// Mitsubishi GX Works2 project: L06-PLC   PLC: L06

// task 1# (event TRUE, interval 0, priority 31): 
// task 10# (event TRUE, interval 0, priority 31): 
// task 工位6（点胶A面） (event TRUE, interval 0, priority 31): 
// task 工位7（点胶B面） (event TRUE, interval 0, priority 31): 
// task 工位8 (event TRUE, interval 0, priority 31): 
// task 工位9（出料及载座升降） (event TRUE, interval 0, priority 31): 
// task 工站5（排不良） (event TRUE, interval 0, priority 31): 
// task 手动 (event TRUE, interval 0, priority 31): 手动
// task 报警 (event TRUE, interval 0, priority 31): 报警
// task 输出1 (event TRUE, interval 0, priority 31): 输出
// task 降载座工位 (event TRUE, interval 0, priority 31): 
// task 马达初始化 (event TRUE, interval 0, priority 31): 
// task 5# (event TRUE, interval 0, priority 31): 
// task 工站2（AOI测试） (event TRUE, interval 0, priority 31): 
// task 工站3（开短路测试） (event TRUE, interval 0, priority 31): 
// task 工站4（开短路测试） (event TRUE, interval 0, priority 31): 
// task 测试程序 (event TRUE, interval 0, priority 31): 
// task 4# (event TRUE, interval 0, priority 31): 
// task 1#1 (event TRUE, interval 0, priority 31): 1#主轴1
// task 2# (event TRUE, interval 0, priority 31): 2#主轴2
// task 3# (event TRUE, interval 0, priority 31): 3#模块轴3
// task 4#1 (event TRUE, interval 0, priority 31): 4#模块轴4
// task 5#1 (event TRUE, interval 0, priority 31): 5#模块轴5
// task 6# (event TRUE, interval 0, priority 31): 
// task 6#1 (event TRUE, interval 0, priority 31): 6#模块轴6
// task 7#1 (event TRUE, interval 0, priority 31): 7#模块轴7
// task 8#1 (event TRUE, interval 0, priority 31): 8#模块轴8
// task 9#1 (event TRUE, interval 0, priority 31): 9#模块轴9
// task 10#1 (event TRUE, interval 0, priority 31): 10#模块轴10
// task 11# (event TRUE, interval 0, priority 31): 
// task 12# (event TRUE, interval 0, priority 31): 
// task 马达初始化1 (event TRUE, interval 0, priority 31): 马达初始化
// task 工位10 (event TRUE, interval 0, priority 31): 
// task 7# (event TRUE, interval 0, priority 31): 
// task 8# (event TRUE, interval 0, priority 31): 
// task 9# (event TRUE, interval 0, priority 31): 
// task 初始化及工位控制 (event TRUE, interval 0, priority 31): 初始化
// task 升载座 (event TRUE, interval 0, priority 31): 
// task 工位1 (event TRUE, interval 0, priority 31): 
// task 放料马达 (event TRUE, interval 0, priority 31): 放料马达
// task 效率统计 (event TRUE, interval 0, priority 31): 效率统计
// task 易损件 (event TRUE, interval 0, priority 31): 易损件
// task 短路预警 (event TRUE, interval 0, priority 31): 
// task 短路预警1 (event TRUE, interval 0, priority 31): 
// task 短路管制 (event TRUE, interval 0, priority 31): 短路管制
// task 试机品点检 (event TRUE, interval 0, priority 31): 试机品点检
// task 11#模块轴11 (event TRUE, interval 0, priority 31): 11#模块轴11
// task 12#模块轴12 (event TRUE, interval 0, priority 31): 12#模块轴12

PROGRAM 1#主轴1
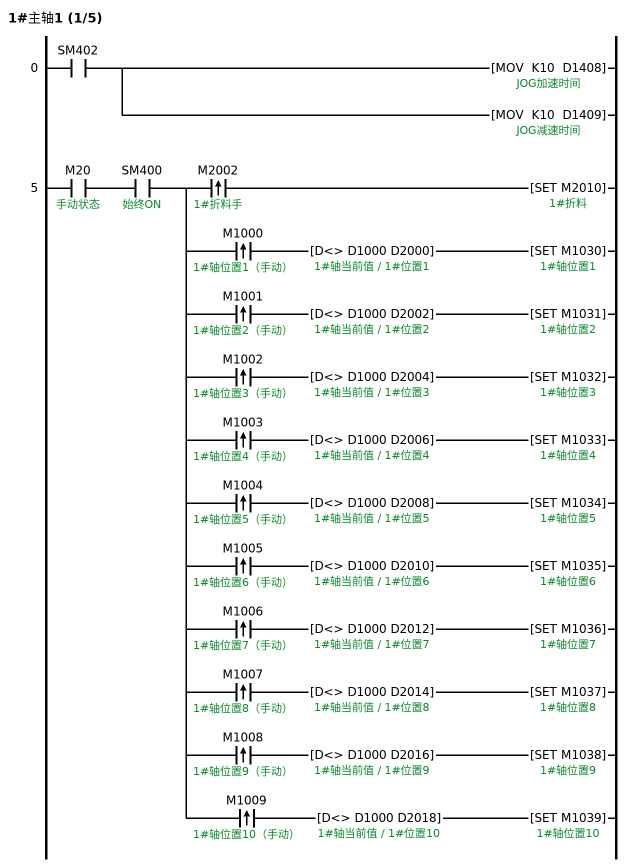
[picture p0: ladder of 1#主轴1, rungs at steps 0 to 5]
0     LD      SM402
      MOV     K10 D1408  ; JOG加速时间
      MOV     K10 D1409  ; JOG减速时间
5     LD      M20  ; 手动状态
      AND     SM400  ; 始终ON
      MPS
      ANDP    M2002  ; 1#折料手
      SET     M2010  ; 1#折料
      MRD
      ANDP    M1000  ; 1#轴位置1（手动）
      ANDD<>  D1000 D2000  ; 1#轴当前值 / 1#位置1
      SET     M1030  ; 1#轴位置1
      MRD
      ANDP    M1001  ; 1#轴位置2（手动）
      ANDD<>  D1000 D2002  ; 1#轴当前值 / 1#位置2
      SET     M1031  ; 1#轴位置2
      MRD
      ANDP    M1002  ; 1#轴位置3（手动）
      ANDD<>  D1000 D2004  ; 1#轴当前值 / 1#位置3
      SET     M1032  ; 1#轴位置3
      MRD
      ANDP    M1003  ; 1#轴位置4（手动）
      ANDD<>  D1000 D2006  ; 1#轴当前值 / 1#位置4
      SET     M1033  ; 1#轴位置4
      MRD
      ANDP    M1004  ; 1#轴位置5（手动）
      ANDD<>  D1000 D2008  ; 1#轴当前值 / 1#位置5
      SET     M1034  ; 1#轴位置5
      MRD
      ANDP    M1005  ; 1#轴位置6（手动）
      ANDD<>  D1000 D2010  ; 1#轴当前值 / 1#位置6
      SET     M1035  ; 1#轴位置6
      MRD
      ANDP    M1006  ; 1#轴位置7（手动）
      ANDD<>  D1000 D2012  ; 1#轴当前值 / 1#位置7
      SET     M1036  ; 1#轴位置7
      MRD
      ANDP    M1007  ; 1#轴位置8（手动）
      ANDD<>  D1000 D2014  ; 1#轴当前值 / 1#位置8
      SET     M1037  ; 1#轴位置8
      MRD
      ANDP    M1008  ; 1#轴位置9（手动）
      ANDD<>  D1000 D2016  ; 1#轴当前值 / 1#位置9
      SET     M1038  ; 1#轴位置9
      MPP
      ANDP    M1009  ; 1#轴位置10（手动）
      ANDD<>  D1000 D2018  ; 1#轴当前值 / 1#位置10
      SET     M1039  ; 1#轴位置10
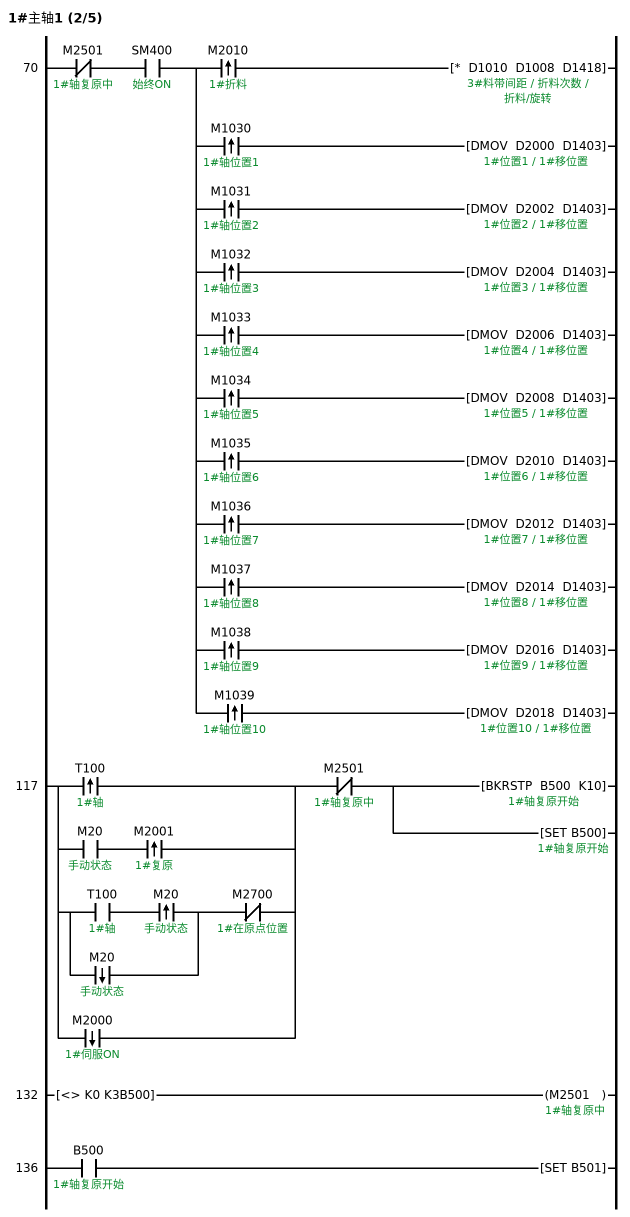
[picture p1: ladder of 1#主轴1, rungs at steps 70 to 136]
70    LDI     M2501  ; 1#轴复原中
      AND     SM400  ; 始终ON
      MPS
      ANDP    M2010  ; 1#折料
      *       D1010 D1008 D1418  ; 3#料带间距 / 折料次数 / 折料/旋转
      MRD
      ANDP    M1030  ; 1#轴位置1
      DMOV    D2000 D1403  ; 1#移位置
      MRD
      ANDP    M1031  ; 1#轴位置2
      DMOV    D2002 D1403
      MRD
      ANDP    M1032  ; 1#轴位置3
      DMOV    D2004 D1403
      MRD
      ANDP    M1033  ; 1#轴位置4
      DMOV    D2006 D1403
      MRD
      ANDP    M1034  ; 1#轴位置5
      DMOV    D2008 D1403
      MRD
      ANDP    M1035  ; 1#轴位置6
      DMOV    D2010 D1403
      MRD
      ANDP    M1036  ; 1#轴位置7
      DMOV    D2012 D1403
      MRD
      ANDP    M1037  ; 1#轴位置8
      DMOV    D2014 D1403
      MRD
      ANDP    M1038  ; 1#轴位置9
      DMOV    D2016 D1403
      MPP
      ANDP    M1039  ; 1#轴位置10
      DMOV    D2018 D1403
117   LDP     T100  ; 1#轴
      LD      M20  ; 手动状态
      ANDP    M2001  ; 1#复原
      ORB
      LD      T100  ; 1#轴
      ANDP    M20  ; 手动状态
      ORF     M20  ; 手动状态
      ANI     M2700  ; 1#在原点位置
      ORB
      ORF     M2000  ; 1#伺服ON
      ANI     M2501  ; 1#轴复原中
      BKRSTP  B500 K10  ; 1#轴复原开始
      SET     B500  ; 1#轴复原开始
132   LD<>    K0 K3B500  ; 1#轴复原开始
      OUT     M2501  ; 1#轴复原中
136   LD      B500  ; 1#轴复原开始
      SET     B501
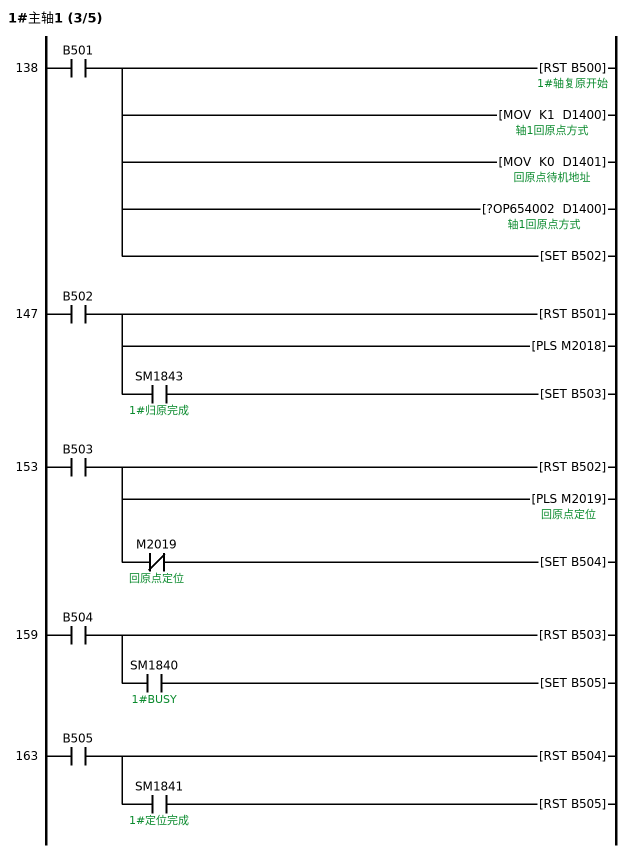
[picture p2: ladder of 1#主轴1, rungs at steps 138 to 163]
138   LD      B501
      RST     B500  ; 1#轴复原开始
      MOV     K1 D1400  ; 轴1回原点方式
      MOV     K0 D1401  ; 回原点待机地址
      ?OP654002 D1400
      SET     B502
147   LD      B502
      RST     B501
      PLS     M2018
      AND     SM1843  ; 1#归原完成
      SET     B503
153   LD      B503
      RST     B502
      PLS     M2019  ; 回原点定位
      ANI     M2019  ; 回原点定位
      SET     B504
159   LD      B504
      RST     B503
      AND     SM1840  ; 1#BUSY
      SET     B505
163   LD      B505
      RST     B504
      AND     SM1841  ; 1#定位完成
      RST     B505
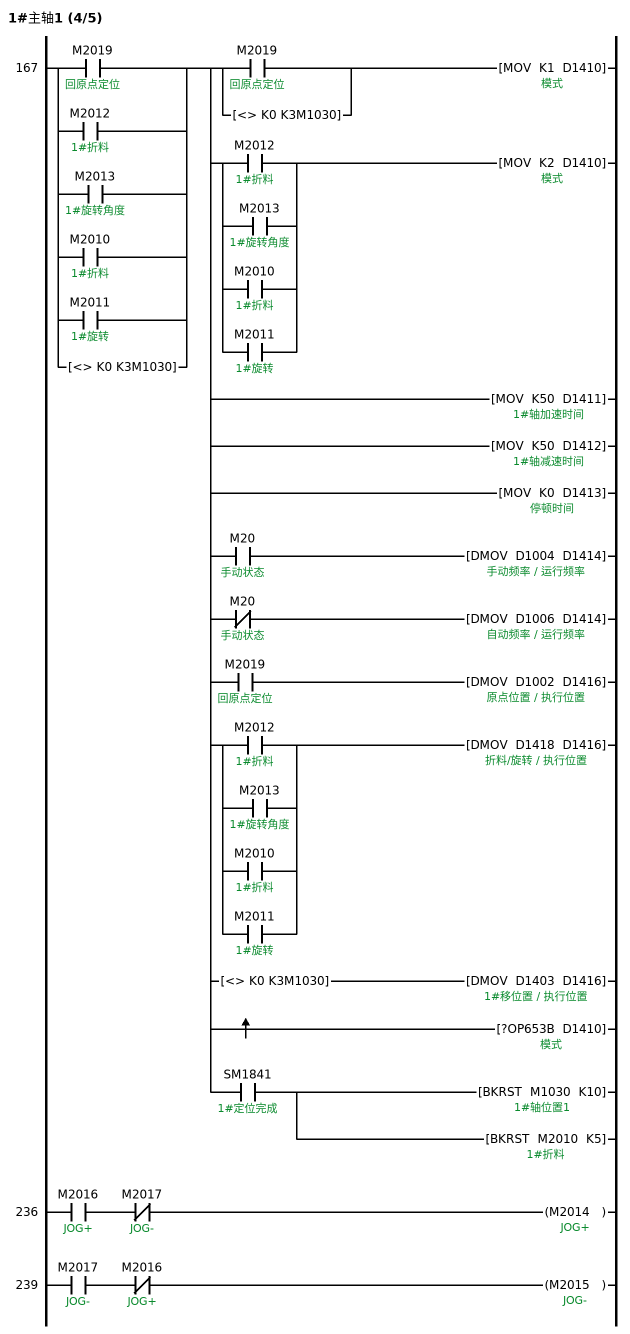
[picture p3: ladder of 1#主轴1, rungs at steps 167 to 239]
167   LD      M2019  ; 回原点定位
      OR      M2012  ; 1#折料
      OR      M2013  ; 1#旋转角度
      OR      M2010  ; 1#折料
      OR      M2011  ; 1#旋转
      OR<>    K0 K3M1030  ; 1#轴位置1
      MPS
      LD      M2019  ; 回原点定位
      OR<>    K0 K3M1030  ; 1#轴位置1
      ANB
      MOV     K1 D1410  ; 模式
      MRD
      LD      M2012  ; 1#折料
      OR      M2013  ; 1#旋转角度
      OR      M2010  ; 1#折料
      OR      M2011  ; 1#旋转
      ANB
      MOV     K2 D1410
      MPP
      MOV     K50 D1411  ; 1#轴加速时间
      MOV     K50 D1412  ; 1#轴减速时间
      MOV     K0 D1413  ; 停顿时间
      MPS
      AND     M20  ; 手动状态
      DMOV    D1004 D1414  ; 手动频率 / 运行频率
      MRD
      ANI     M20  ; 手动状态
      DMOV    D1006 D1414  ; 自动频率
      MRD
      AND     M2019  ; 回原点定位
      DMOV    D1002 D1416  ; 原点位置 / 执行位置
      MRD
      LD      M2012  ; 1#折料
      OR      M2013  ; 1#旋转角度
      OR      M2010  ; 1#折料
      OR      M2011  ; 1#旋转
      ANB
      DMOV    D1418 D1416
      MRD
      AND<>   K0 K3M1030  ; 1#轴位置1
      DMOV    D1403 D1416
      MRD
      MEP
      ?OP653B D1410
      MPP
      AND     SM1841  ; 1#定位完成
      BKRST   M1030 K10
      BKRST   M2010 K5
236   LD      M2016  ; JOG+
      ANI     M2017  ; JOG-
      OUT     M2014  ; JOG+
239   LD      M2017  ; JOG-
      ANI     M2016  ; JOG+
      OUT     M2015  ; JOG-
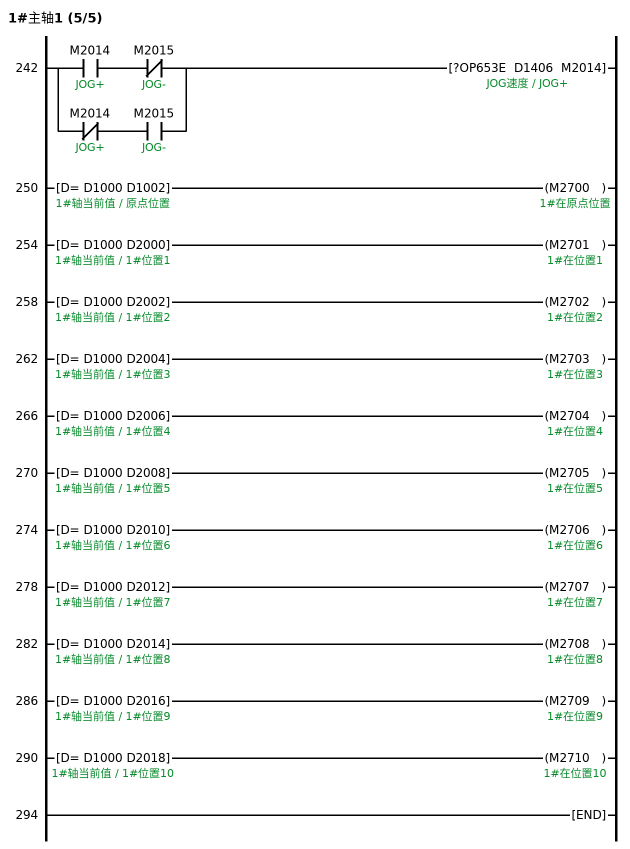
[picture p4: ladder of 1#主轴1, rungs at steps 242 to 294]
242   LD      M2014  ; JOG+
      ANI     M2015  ; JOG-
      LDI     M2014  ; JOG+
      AND     M2015  ; JOG-
      ORB
      ?OP653E D1406 M2014  ; JOG速度
250   LDD=    D1000 D1002  ; 1#轴当前值 / 原点位置
      OUT     M2700  ; 1#在原点位置
254   LDD=    D1000 D2000  ; 1#轴当前值 / 1#位置1
      OUT     M2701  ; 1#在位置1
258   LDD=    D1000 D2002  ; 1#轴当前值 / 1#位置2
      OUT     M2702  ; 1#在位置2
262   LDD=    D1000 D2004  ; 1#轴当前值 / 1#位置3
      OUT     M2703  ; 1#在位置3
266   LDD=    D1000 D2006  ; 1#轴当前值 / 1#位置4
      OUT     M2704  ; 1#在位置4
270   LDD=    D1000 D2008  ; 1#轴当前值 / 1#位置5
      OUT     M2705  ; 1#在位置5
274   LDD=    D1000 D2010  ; 1#轴当前值 / 1#位置6
      OUT     M2706  ; 1#在位置6
278   LDD=    D1000 D2012  ; 1#轴当前值 / 1#位置7
      OUT     M2707  ; 1#在位置7
282   LDD=    D1000 D2014  ; 1#轴当前值 / 1#位置8
      OUT     M2708  ; 1#在位置8
286   LDD=    D1000 D2016  ; 1#轴当前值 / 1#位置9
      OUT     M2709  ; 1#在位置9
290   LDD=    D1000 D2018  ; 1#轴当前值 / 1#位置10
      OUT     M2710  ; 1#在位置10
294   END
END_PROGRAM

PROGRAM 10#模块轴10
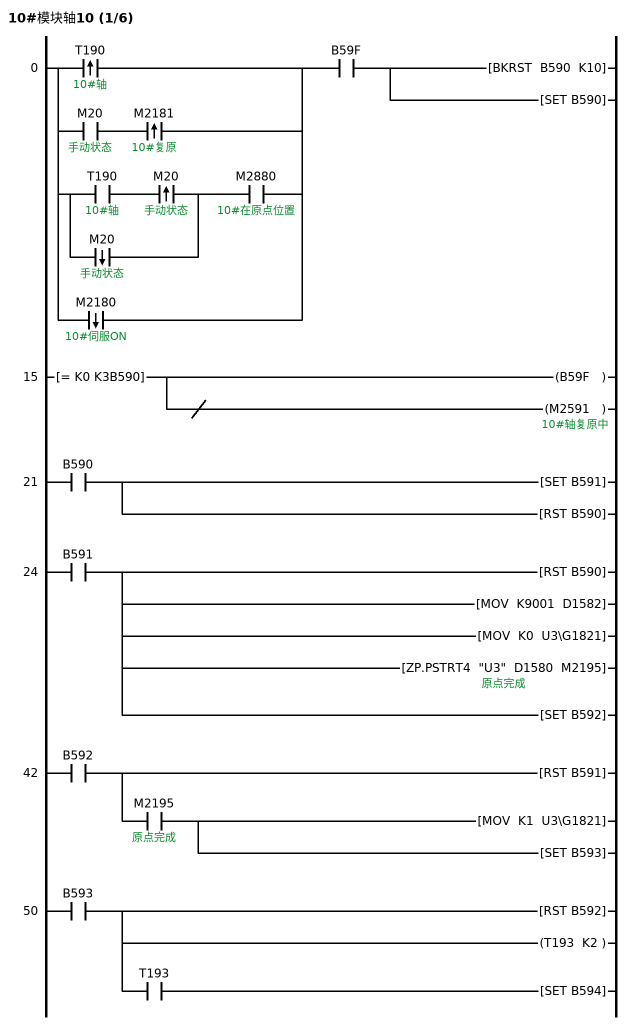
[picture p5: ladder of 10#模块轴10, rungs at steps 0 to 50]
0     LDP     T190  ; 10#轴
      LD      M20  ; 手动状态
      ANDP    M2181  ; 10#复原
      ORB
      LD      T190  ; 10#轴
      ANDP    M20  ; 手动状态
      ORF     M20  ; 手动状态
      AND     M2880  ; 10#在原点位置
      ORB
      ORF     M2180  ; 10#伺服ON
      AND     B59F
      BKRST   B590 K10
      SET     B590
15    LD=     K0 K3B590
      OUT     B59F
      INV
      OUT     M2591  ; 10#轴复原中
21    LD      B590
      SET     B591
      RST     B590
24    LD      B591
      RST     B590
      MOV     K9001 D1582
      MOV     K0 U3\G1821
      ZP.PSTRT4 "U3" D1580 M2195  ; 原点完成
      SET     B592
42    LD      B592
      RST     B591
      AND     M2195  ; 原点完成
      MOV     K1 U3\G1821
      SET     B593
50    LD      B593
      RST     B592
      OUT     T193 K2
      AND     T193
      SET     B594
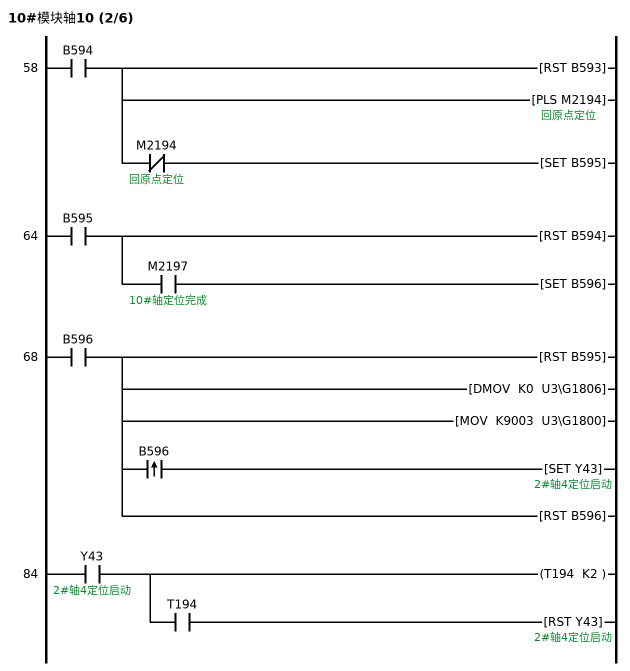
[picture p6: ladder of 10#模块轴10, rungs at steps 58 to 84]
58    LD      B594
      RST     B593
      PLS     M2194  ; 回原点定位
      ANI     M2194  ; 回原点定位
      SET     B595
64    LD      B595
      RST     B594
      AND     M2197  ; 10#轴定位完成
      SET     B596
68    LD      B596
      RST     B595
      DMOV    K0 U3\G1806
      MOV     K9003 U3\G1800
      MPS
      ANDP    B596
      SET     Y43  ; 2#轴4定位启动
      MPP
      RST     B596
84    LD      Y43  ; 2#轴4定位启动
      OUT     T194 K2
      AND     T194
      RST     Y43  ; 2#轴4定位启动
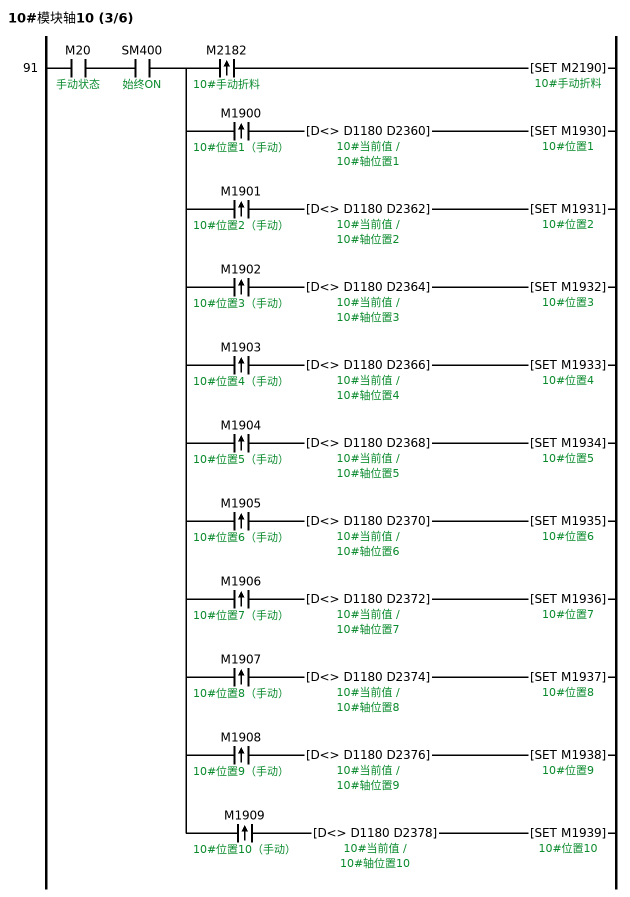
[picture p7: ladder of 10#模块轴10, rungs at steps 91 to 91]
91    LD      M20  ; 手动状态
      AND     SM400  ; 始终ON
      MPS
      ANDP    M2182  ; 10#手动折料
      SET     M2190  ; 10#手动折料
      MRD
      ANDP    M1900  ; 10#位置1（手动）
      ANDD<>  D1180 D2360  ; 10#当前值 / 10#轴位置1
      SET     M1930  ; 10#位置1
      MRD
      ANDP    M1901  ; 10#位置2（手动）
      ANDD<>  D1180 D2362  ; 10#当前值 / 10#轴位置2
      SET     M1931  ; 10#位置2
      MRD
      ANDP    M1902  ; 10#位置3（手动）
      ANDD<>  D1180 D2364  ; 10#当前值 / 10#轴位置3
      SET     M1932  ; 10#位置3
      MRD
      ANDP    M1903  ; 10#位置4（手动）
      ANDD<>  D1180 D2366  ; 10#当前值 / 10#轴位置4
      SET     M1933  ; 10#位置4
      MRD
      ANDP    M1904  ; 10#位置5（手动）
      ANDD<>  D1180 D2368  ; 10#当前值 / 10#轴位置5
      SET     M1934  ; 10#位置5
      MRD
      ANDP    M1905  ; 10#位置6（手动）
      ANDD<>  D1180 D2370  ; 10#当前值 / 10#轴位置6
      SET     M1935  ; 10#位置6
      MRD
      ANDP    M1906  ; 10#位置7（手动）
      ANDD<>  D1180 D2372  ; 10#当前值 / 10#轴位置7
      SET     M1936  ; 10#位置7
      MRD
      ANDP    M1907  ; 10#位置8（手动）
      ANDD<>  D1180 D2374  ; 10#当前值 / 10#轴位置8
      SET     M1937  ; 10#位置8
      MRD
      ANDP    M1908  ; 10#位置9（手动）
      ANDD<>  D1180 D2376  ; 10#当前值 / 10#轴位置9
      SET     M1938  ; 10#位置9
      MPP
      ANDP    M1909  ; 10#位置10（手动）
      ANDD<>  D1180 D2378  ; 10#当前值 / 10#轴位置10
      SET     M1939  ; 10#位置10
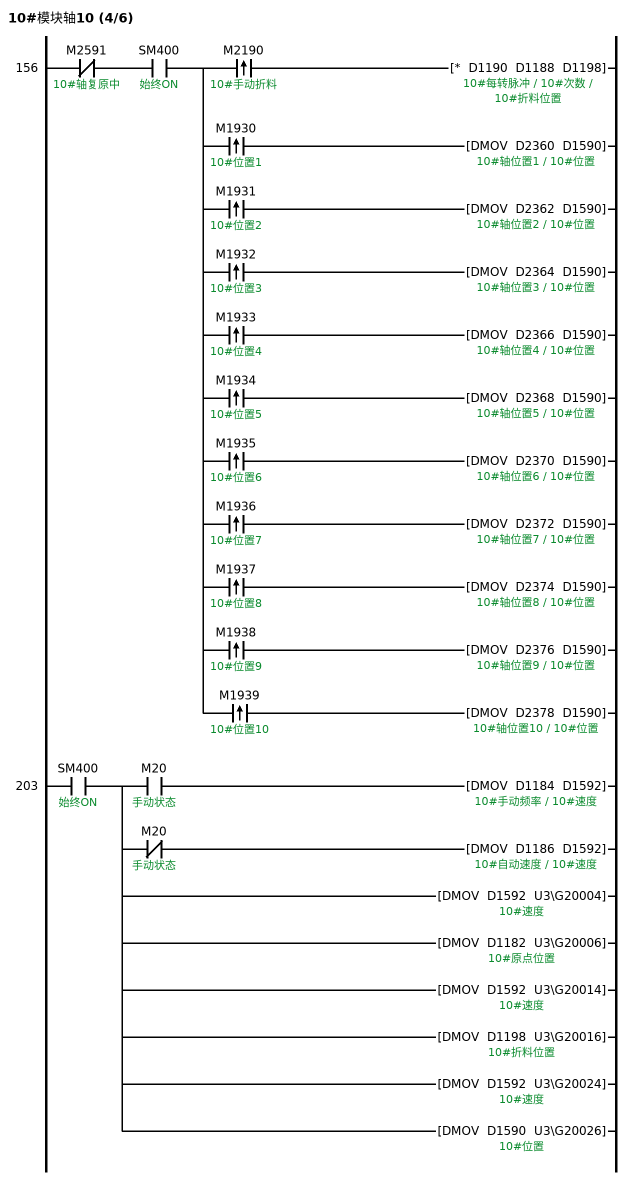
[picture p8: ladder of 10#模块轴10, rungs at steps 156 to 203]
156   LDI     M2591  ; 10#轴复原中
      AND     SM400  ; 始终ON
      MPS
      ANDP    M2190  ; 10#手动折料
      *       D1190 D1188 D1198  ; 10#每转脉冲 / 10#次数 / 10#折料位置
      MRD
      ANDP    M1930  ; 10#位置1
      DMOV    D2360 D1590  ; 10#位置
      MRD
      ANDP    M1931  ; 10#位置2
      DMOV    D2362 D1590
      MRD
      ANDP    M1932  ; 10#位置3
      DMOV    D2364 D1590
      MRD
      ANDP    M1933  ; 10#位置4
      DMOV    D2366 D1590
      MRD
      ANDP    M1934  ; 10#位置5
      DMOV    D2368 D1590
      MRD
      ANDP    M1935  ; 10#位置6
      DMOV    D2370 D1590
      MRD
      ANDP    M1936  ; 10#位置7
      DMOV    D2372 D1590
      MRD
      ANDP    M1937  ; 10#位置8
      DMOV    D2374 D1590
      MRD
      ANDP    M1938  ; 10#位置9
      DMOV    D2376 D1590
      MPP
      ANDP    M1939  ; 10#位置10
      DMOV    D2378 D1590
203   LD      SM400  ; 始终ON
      MPS
      AND     M20  ; 手动状态
      DMOV    D1184 D1592  ; 10#手动频率 / 10#速度
      MRD
      ANI     M20  ; 手动状态
      DMOV    D1186 D1592  ; 10#自动速度
      MPP
      DMOV    D1592 U3\G20004
      DMOV    D1182 U3\G20006  ; 10#原点位置
      DMOV    D1592 U3\G20014
      DMOV    D1198 U3\G20016
      DMOV    D1592 U3\G20024
      DMOV    D1590 U3\G20026
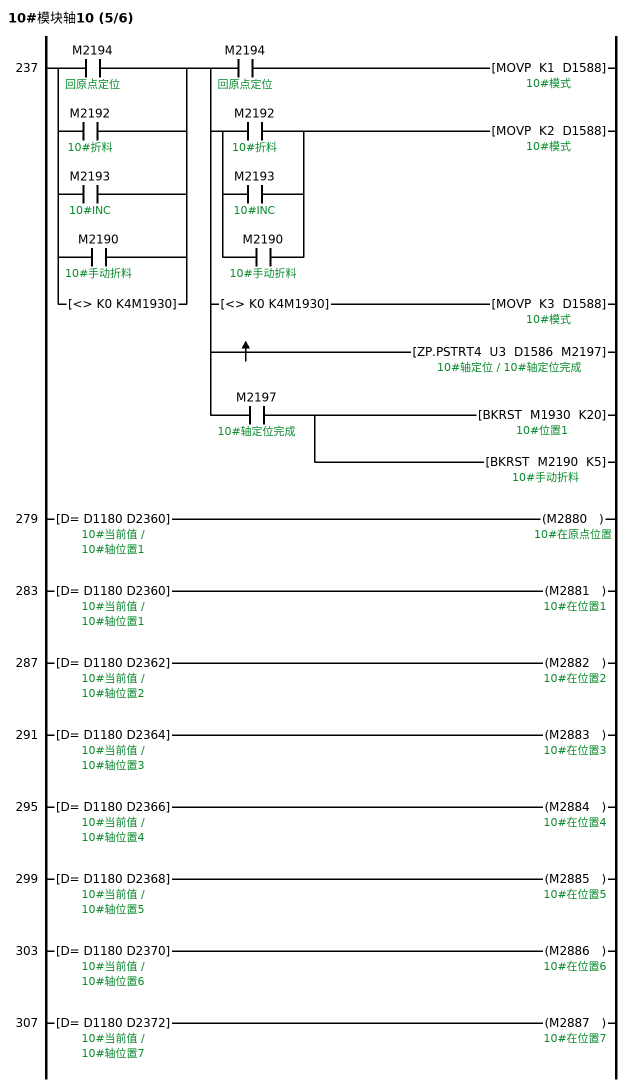
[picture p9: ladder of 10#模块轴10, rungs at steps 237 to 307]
237   LD      M2194  ; 回原点定位
      OR      M2192  ; 10#折料
      OR      M2193  ; 10#INC
      OR      M2190  ; 10#手动折料
      OR<>    K0 K4M1930  ; 10#位置1
      MPS
      AND     M2194  ; 回原点定位
      MOVP    K1 D1588  ; 10#模式
      MRD
      LD      M2192  ; 10#折料
      OR      M2193  ; 10#INC
      OR      M2190  ; 10#手动折料
      ANB
      MOVP    K2 D1588
      MRD
      AND<>   K0 K4M1930  ; 10#位置1
      MOVP    K3 D1588
      MRD
      MEP
      ZP.PSTRT4 U3 D1586 M2197  ; 10#轴定位
      MPP
      AND     M2197  ; 10#轴定位完成
      BKRST   M1930 K20
      BKRST   M2190 K5
279   LDD=    D1180 D2360  ; 10#当前值 / 10#轴位置1
      OUT     M2880  ; 10#在原点位置
283   LDD=    D1180 D2360  ; 10#当前值 / 10#轴位置1
      OUT     M2881  ; 10#在位置1
287   LDD=    D1180 D2362  ; 10#当前值 / 10#轴位置2
      OUT     M2882  ; 10#在位置2
291   LDD=    D1180 D2364  ; 10#当前值 / 10#轴位置3
      OUT     M2883  ; 10#在位置3
295   LDD=    D1180 D2366  ; 10#当前值 / 10#轴位置4
      OUT     M2884  ; 10#在位置4
299   LDD=    D1180 D2368  ; 10#当前值 / 10#轴位置5
      OUT     M2885  ; 10#在位置5
303   LDD=    D1180 D2370  ; 10#当前值 / 10#轴位置6
      OUT     M2886  ; 10#在位置6
307   LDD=    D1180 D2372  ; 10#当前值 / 10#轴位置7
      OUT     M2887  ; 10#在位置7
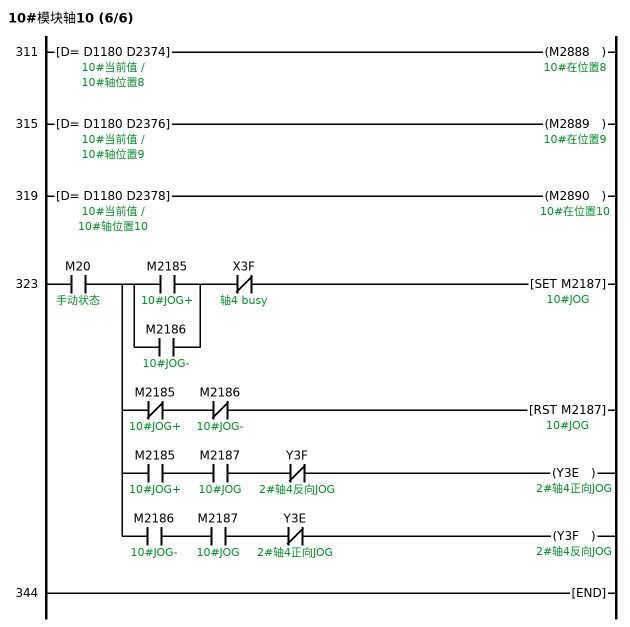
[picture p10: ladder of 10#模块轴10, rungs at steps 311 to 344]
311   LDD=    D1180 D2374  ; 10#当前值 / 10#轴位置8
      OUT     M2888  ; 10#在位置8
315   LDD=    D1180 D2376  ; 10#当前值 / 10#轴位置9
      OUT     M2889  ; 10#在位置9
319   LDD=    D1180 D2378  ; 10#当前值 / 10#轴位置10
      OUT     M2890  ; 10#在位置10
323   LD      M20  ; 手动状态
      MPS
      LD      M2185  ; 10#JOG+
      OR      M2186  ; 10#JOG-
      ANB
      ANI     X3F  ; 轴4 busy
      SET     M2187  ; 10#JOG
      MRD
      ANI     M2185  ; 10#JOG+
      ANI     M2186  ; 10#JOG-
      RST     M2187  ; 10#JOG
      MRD
      AND     M2185  ; 10#JOG+
      AND     M2187  ; 10#JOG
      ANI     Y3F  ; 2#轴4反向JOG
      OUT     Y3E  ; 2#轴4正向JOG
      MPP
      AND     M2186  ; 10#JOG-
      AND     M2187  ; 10#JOG
      ANI     Y3E  ; 2#轴4正向JOG
      OUT     Y3F  ; 2#轴4反向JOG
344   END
END_PROGRAM

PROGRAM 2#主轴2
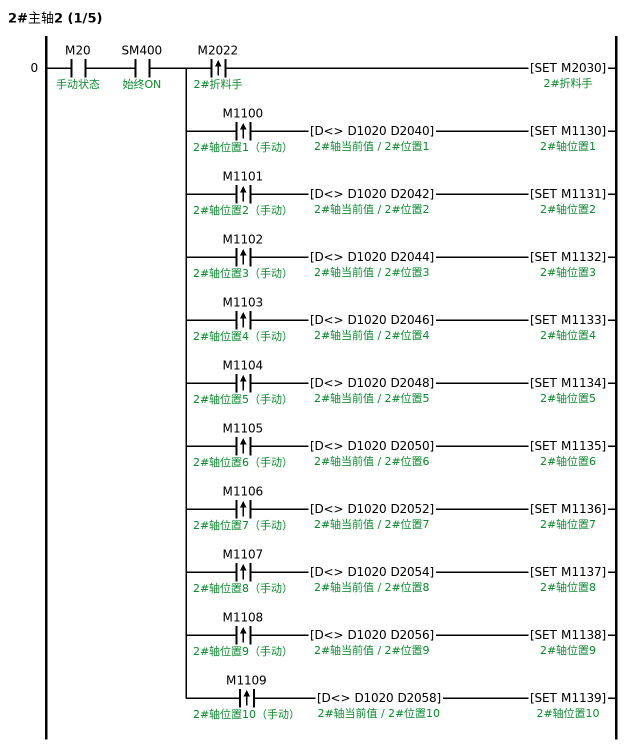
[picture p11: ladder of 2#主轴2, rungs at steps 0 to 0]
0     LD      M20  ; 手动状态
      AND     SM400  ; 始终ON
      MPS
      ANDP    M2022  ; 2#折料手
      SET     M2030  ; 2#折料手
      MRD
      ANDP    M1100  ; 2#轴位置1（手动）
      ANDD<>  D1020 D2040  ; 2#轴当前值 / 2#位置1
      SET     M1130  ; 2#轴位置1
      MRD
      ANDP    M1101  ; 2#轴位置2（手动）
      ANDD<>  D1020 D2042  ; 2#轴当前值 / 2#位置2
      SET     M1131  ; 2#轴位置2
      MRD
      ANDP    M1102  ; 2#轴位置3（手动）
      ANDD<>  D1020 D2044  ; 2#轴当前值 / 2#位置3
      SET     M1132  ; 2#轴位置3
      MRD
      ANDP    M1103  ; 2#轴位置4（手动）
      ANDD<>  D1020 D2046  ; 2#轴当前值 / 2#位置4
      SET     M1133  ; 2#轴位置4
      MRD
      ANDP    M1104  ; 2#轴位置5（手动）
      ANDD<>  D1020 D2048  ; 2#轴当前值 / 2#位置5
      SET     M1134  ; 2#轴位置5
      MRD
      ANDP    M1105  ; 2#轴位置6（手动）
      ANDD<>  D1020 D2050  ; 2#轴当前值 / 2#位置6
      SET     M1135  ; 2#轴位置6
      MRD
      ANDP    M1106  ; 2#轴位置7（手动）
      ANDD<>  D1020 D2052  ; 2#轴当前值 / 2#位置7
      SET     M1136  ; 2#轴位置7
      MRD
      ANDP    M1107  ; 2#轴位置8（手动）
      ANDD<>  D1020 D2054  ; 2#轴当前值 / 2#位置8
      SET     M1137  ; 2#轴位置8
      MRD
      ANDP    M1108  ; 2#轴位置9（手动）
      ANDD<>  D1020 D2056  ; 2#轴当前值 / 2#位置9
      SET     M1138  ; 2#轴位置9
      MPP
      ANDP    M1109  ; 2#轴位置10（手动）
      ANDD<>  D1020 D2058  ; 2#轴当前值 / 2#位置10
      SET     M1139  ; 2#轴位置10
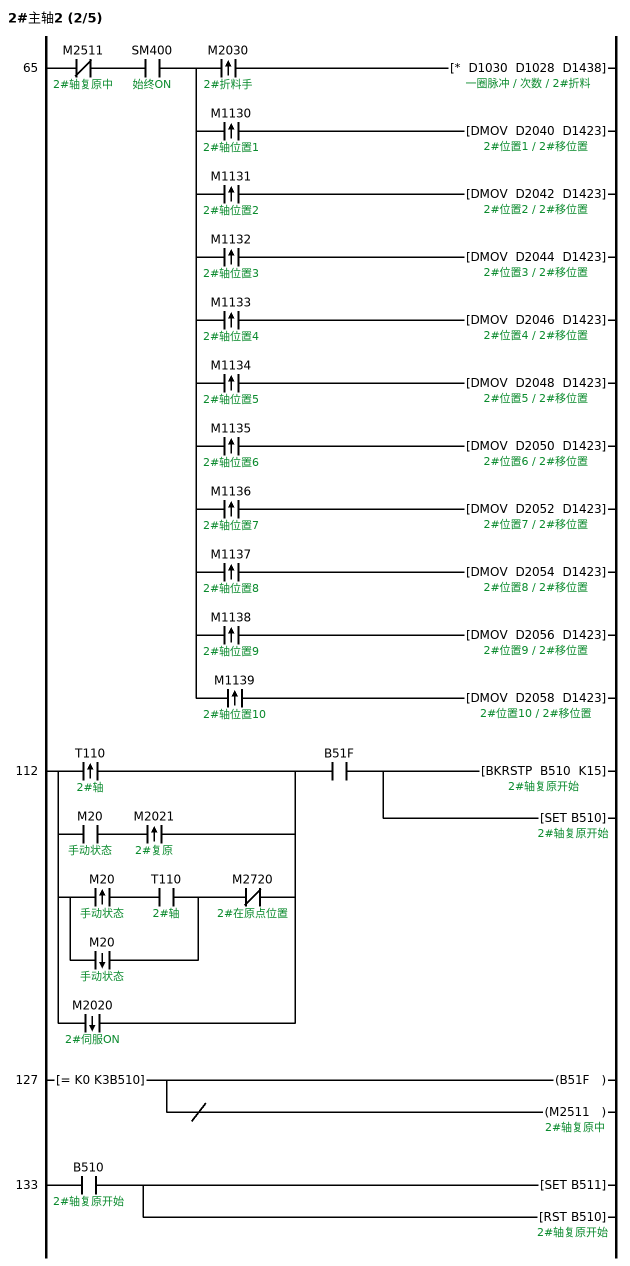
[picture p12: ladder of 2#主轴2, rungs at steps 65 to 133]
65    LDI     M2511  ; 2#轴复原中
      AND     SM400  ; 始终ON
      MPS
      ANDP    M2030  ; 2#折料手
      *       D1030 D1028 D1438  ; 一圈脉冲 / 次数 / 2#折料
      MRD
      ANDP    M1130  ; 2#轴位置1
      DMOV    D2040 D1423  ; 2#移位置
      MRD
      ANDP    M1131  ; 2#轴位置2
      DMOV    D2042 D1423
      MRD
      ANDP    M1132  ; 2#轴位置3
      DMOV    D2044 D1423
      MRD
      ANDP    M1133  ; 2#轴位置4
      DMOV    D2046 D1423
      MRD
      ANDP    M1134  ; 2#轴位置5
      DMOV    D2048 D1423
      MRD
      ANDP    M1135  ; 2#轴位置6
      DMOV    D2050 D1423
      MRD
      ANDP    M1136  ; 2#轴位置7
      DMOV    D2052 D1423
      MRD
      ANDP    M1137  ; 2#轴位置8
      DMOV    D2054 D1423
      MRD
      ANDP    M1138  ; 2#轴位置9
      DMOV    D2056 D1423
      MPP
      ANDP    M1139  ; 2#轴位置10
      DMOV    D2058 D1423
112   LDP     T110  ; 2#轴
      LD      M20  ; 手动状态
      ANDP    M2021  ; 2#复原
      ORB
      LDP     M20  ; 手动状态
      AND     T110  ; 2#轴
      ORF     M20  ; 手动状态
      ANI     M2720  ; 2#在原点位置
      ORB
      ORF     M2020  ; 2#伺服ON
      AND     B51F
      BKRSTP  B510 K15  ; 2#轴复原开始
      SET     B510  ; 2#轴复原开始
127   LD=     K0 K3B510  ; 2#轴复原开始
      OUT     B51F
      INV
      OUT     M2511  ; 2#轴复原中
133   LD      B510  ; 2#轴复原开始
      SET     B511
      RST     B510  ; 2#轴复原开始
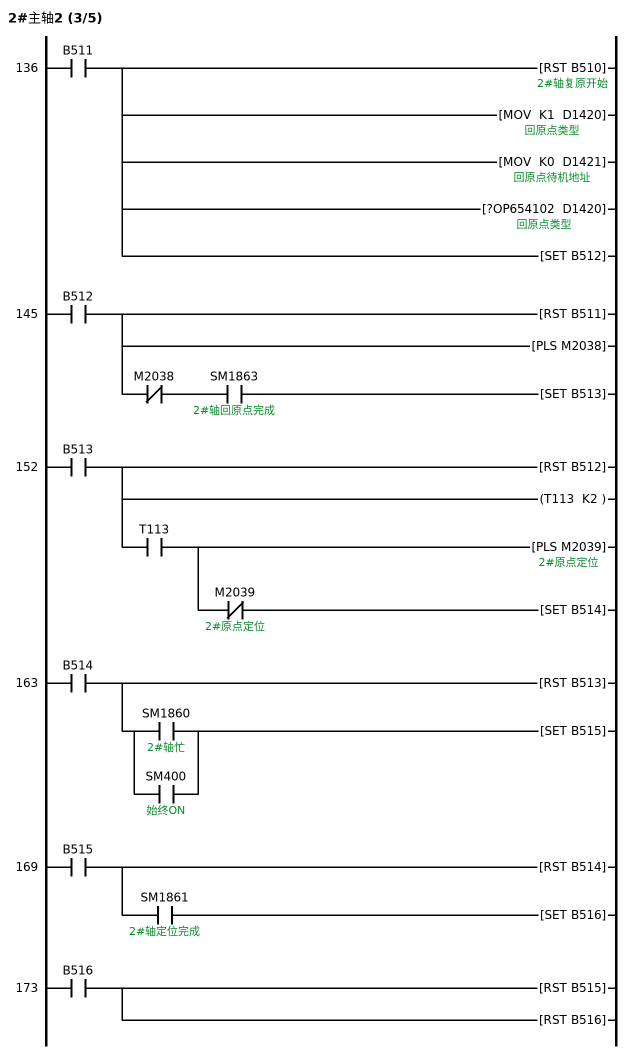
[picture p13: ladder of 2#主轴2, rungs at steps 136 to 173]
136   LD      B511
      RST     B510  ; 2#轴复原开始
      MOV     K1 D1420  ; 回原点类型
      MOV     K0 D1421  ; 回原点待机地址
      ?OP654102 D1420
      SET     B512
145   LD      B512
      RST     B511
      PLS     M2038
      ANI     M2038
      AND     SM1863  ; 2#轴回原点完成
      SET     B513
152   LD      B513
      RST     B512
      OUT     T113 K2
      AND     T113
      PLS     M2039  ; 2#原点定位
      ANI     M2039  ; 2#原点定位
      SET     B514
163   LD      B514
      RST     B513
      LD      SM1860  ; 2#轴忙
      OR      SM400  ; 始终ON
      ANB
      SET     B515
169   LD      B515
      RST     B514
      AND     SM1861  ; 2#轴定位完成
      SET     B516
173   LD      B516
      RST     B515
      RST     B516
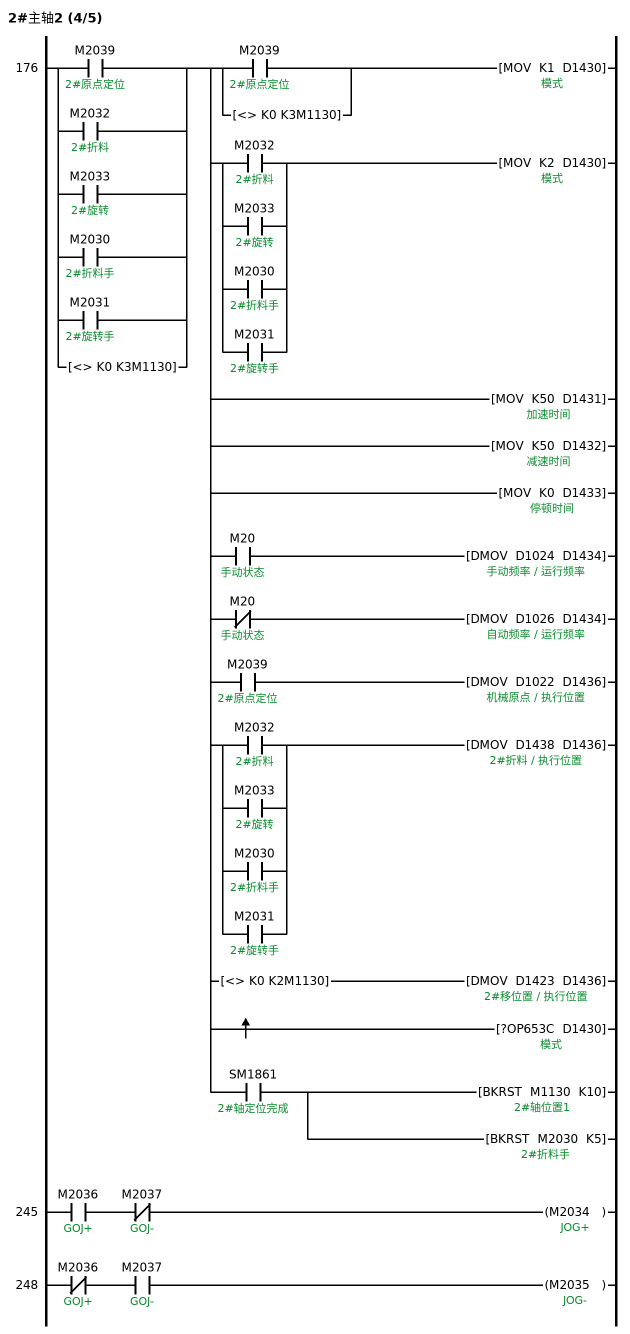
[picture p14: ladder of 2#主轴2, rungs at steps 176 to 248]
176   LD      M2039  ; 2#原点定位
      OR      M2032  ; 2#折料
      OR      M2033  ; 2#旋转
      OR      M2030  ; 2#折料手
      OR      M2031  ; 2#旋转手
      OR<>    K0 K3M1130  ; 2#轴位置1
      MPS
      LD      M2039  ; 2#原点定位
      OR<>    K0 K3M1130  ; 2#轴位置1
      ANB
      MOV     K1 D1430  ; 模式
      MRD
      LD      M2032  ; 2#折料
      OR      M2033  ; 2#旋转
      OR      M2030  ; 2#折料手
      OR      M2031  ; 2#旋转手
      ANB
      MOV     K2 D1430
      MPP
      MOV     K50 D1431  ; 加速时间
      MOV     K50 D1432  ; 减速时间
      MOV     K0 D1433  ; 停顿时间
      MPS
      AND     M20  ; 手动状态
      DMOV    D1024 D1434  ; 手动频率 / 运行频率
      MRD
      ANI     M20  ; 手动状态
      DMOV    D1026 D1434  ; 自动频率
      MRD
      AND     M2039  ; 2#原点定位
      DMOV    D1022 D1436  ; 机械原点 / 执行位置
      MRD
      LD      M2032  ; 2#折料
      OR      M2033  ; 2#旋转
      OR      M2030  ; 2#折料手
      OR      M2031  ; 2#旋转手
      ANB
      DMOV    D1438 D1436
      MRD
      AND<>   K0 K2M1130  ; 2#轴位置1
      DMOV    D1423 D1436
      MRD
      MEP
      ?OP653C D1430
      MPP
      AND     SM1861  ; 2#轴定位完成
      BKRST   M1130 K10
      BKRST   M2030 K5
245   LD      M2036  ; GOJ+
      ANI     M2037  ; GOJ-
      OUT     M2034  ; JOG+
248   LDI     M2036  ; GOJ+
      AND     M2037  ; GOJ-
      OUT     M2035  ; JOG-
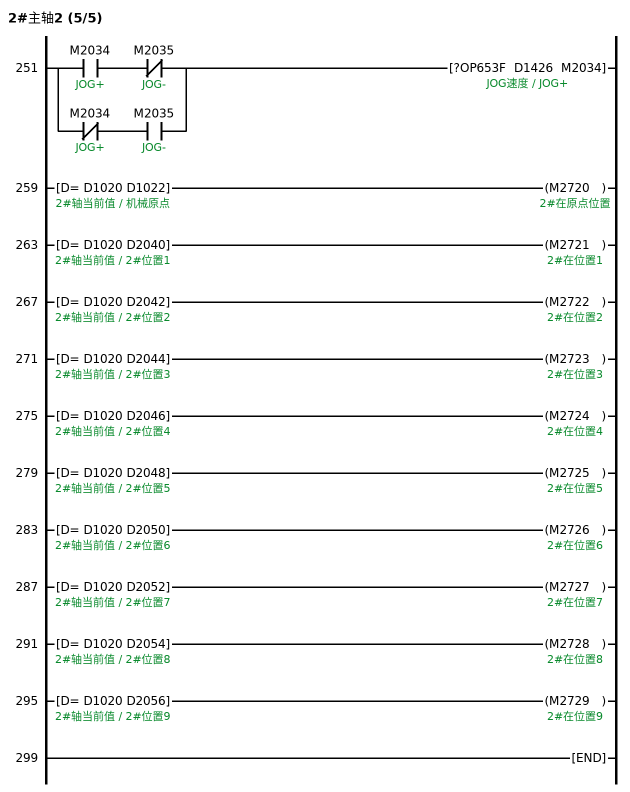
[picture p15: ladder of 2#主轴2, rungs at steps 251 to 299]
251   LD      M2034  ; JOG+
      ANI     M2035  ; JOG-
      LDI     M2034  ; JOG+
      AND     M2035  ; JOG-
      ORB
      ?OP653F D1426 M2034  ; JOG速度
259   LDD=    D1020 D1022  ; 2#轴当前值 / 机械原点
      OUT     M2720  ; 2#在原点位置
263   LDD=    D1020 D2040  ; 2#轴当前值 / 2#位置1
      OUT     M2721  ; 2#在位置1
267   LDD=    D1020 D2042  ; 2#轴当前值 / 2#位置2
      OUT     M2722  ; 2#在位置2
271   LDD=    D1020 D2044  ; 2#轴当前值 / 2#位置3
      OUT     M2723  ; 2#在位置3
275   LDD=    D1020 D2046  ; 2#轴当前值 / 2#位置4
      OUT     M2724  ; 2#在位置4
279   LDD=    D1020 D2048  ; 2#轴当前值 / 2#位置5
      OUT     M2725  ; 2#在位置5
283   LDD=    D1020 D2050  ; 2#轴当前值 / 2#位置6
      OUT     M2726  ; 2#在位置6
287   LDD=    D1020 D2052  ; 2#轴当前值 / 2#位置7
      OUT     M2727  ; 2#在位置7
291   LDD=    D1020 D2054  ; 2#轴当前值 / 2#位置8
      OUT     M2728  ; 2#在位置8
295   LDD=    D1020 D2056  ; 2#轴当前值 / 2#位置9
      OUT     M2729  ; 2#在位置9
299   END
END_PROGRAM

PROGRAM 3#模块轴3
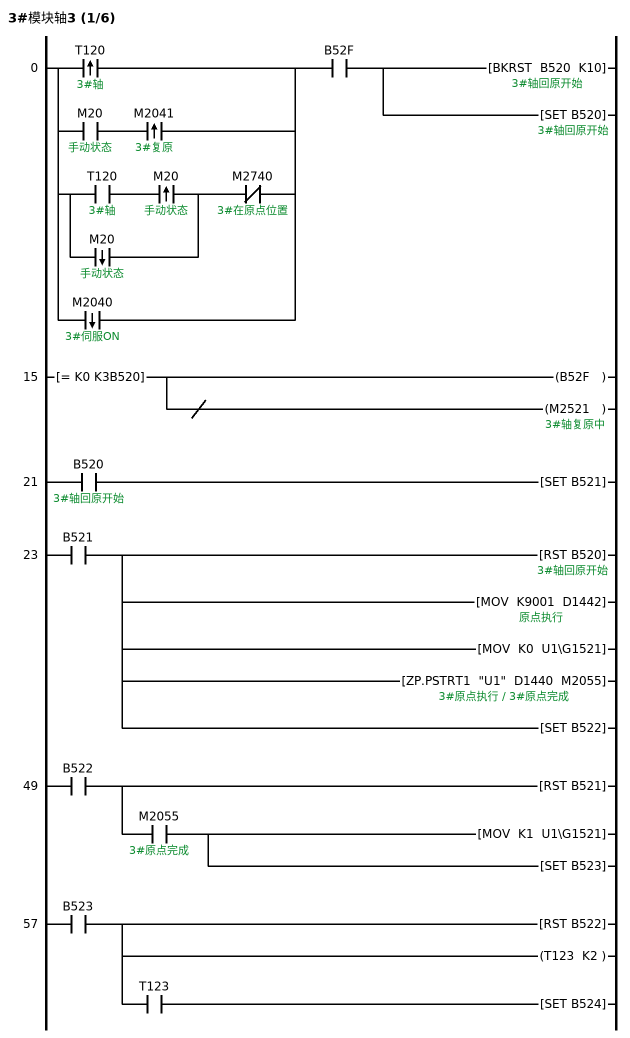
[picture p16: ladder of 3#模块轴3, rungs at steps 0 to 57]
0     LDP     T120  ; 3#轴
      LD      M20  ; 手动状态
      ANDP    M2041  ; 3#复原
      ORB
      LD      T120  ; 3#轴
      ANDP    M20  ; 手动状态
      ORF     M20  ; 手动状态
      ANI     M2740  ; 3#在原点位置
      ORB
      ORF     M2040  ; 3#伺服ON
      AND     B52F
      BKRST   B520 K10  ; 3#轴回原开始
      SET     B520  ; 3#轴回原开始
15    LD=     K0 K3B520  ; 3#轴回原开始
      OUT     B52F
      INV
      OUT     M2521  ; 3#轴复原中
21    LD      B520  ; 3#轴回原开始
      SET     B521
23    LD      B521
      RST     B520  ; 3#轴回原开始
      MOV     K9001 D1442  ; 原点执行
      MOV     K0 U1\G1521
      ZP.PSTRT1 "U1" D1440 M2055  ; 3#原点执行 / 3#原点完成
        [note] 3#轴定位启动
      SET     B522
49    LD      B522
      RST     B521
      AND     M2055  ; 3#原点完成
      MOV     K1 U1\G1521
      SET     B523
57    LD      B523
      RST     B522
      OUT     T123 K2
      AND     T123
      SET     B524
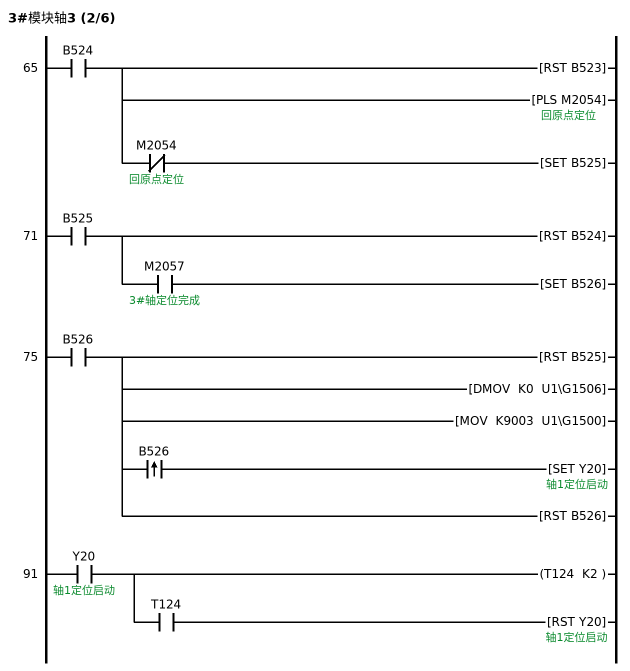
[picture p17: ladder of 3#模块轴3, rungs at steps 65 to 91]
65    LD      B524
      RST     B523
      PLS     M2054  ; 回原点定位
      ANI     M2054  ; 回原点定位
      SET     B525
71    LD      B525
      RST     B524
      AND     M2057  ; 3#轴定位完成
      SET     B526
75    LD      B526
      RST     B525
      DMOV    K0 U1\G1506
      MOV     K9003 U1\G1500
      MPS
      ANDP    B526
      SET     Y20  ; 轴1定位启动
      MPP
      RST     B526
91    LD      Y20  ; 轴1定位启动
      OUT     T124 K2
      AND     T124
      RST     Y20  ; 轴1定位启动
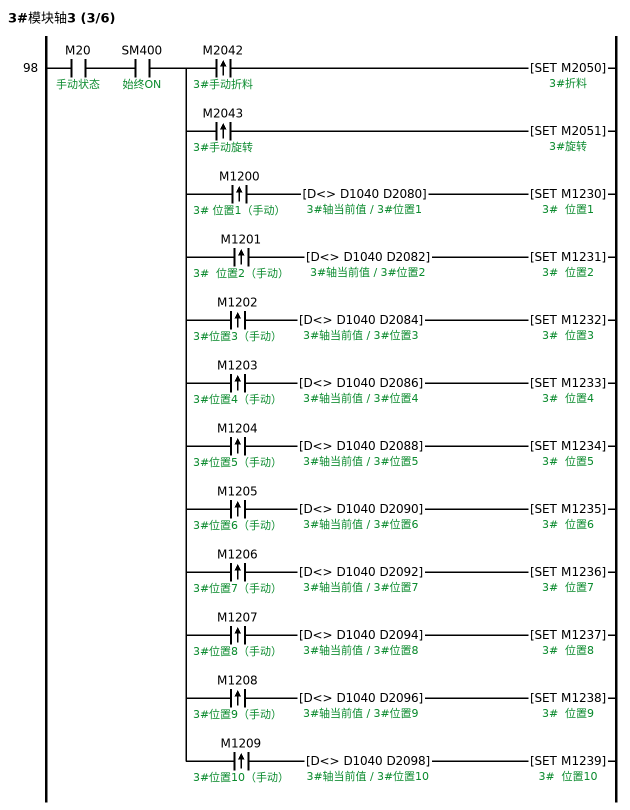
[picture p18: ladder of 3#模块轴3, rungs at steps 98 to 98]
98    LD      M20  ; 手动状态
      AND     SM400  ; 始终ON
      MPS
      ANDP    M2042  ; 3#手动折料
      SET     M2050  ; 3#折料
      MRD
      ANDP    M2043  ; 3#手动旋转
      SET     M2051  ; 3#旋转
      MRD
      ANDP    M1200  ; 3# 位置1（手动）
      ANDD<>  D1040 D2080  ; 3#轴当前值 / 3#位置1
      SET     M1230  ; 3#  位置1
      MRD
      ANDP    M1201  ; 3#  位置2（手动）
      ANDD<>  D1040 D2082  ; 3#轴当前值 / 3#位置2
      SET     M1231  ; 3#  位置2
      MRD
      ANDP    M1202  ; 3#位置3（手动）
      ANDD<>  D1040 D2084  ; 3#轴当前值 / 3#位置3
      SET     M1232  ; 3#  位置3
      MRD
      ANDP    M1203  ; 3#位置4（手动）
      ANDD<>  D1040 D2086  ; 3#轴当前值 / 3#位置4
      SET     M1233  ; 3#  位置4
      MRD
      ANDP    M1204  ; 3#位置5（手动）
      ANDD<>  D1040 D2088  ; 3#轴当前值 / 3#位置5
      SET     M1234  ; 3#  位置5
      MRD
      ANDP    M1205  ; 3#位置6（手动）
      ANDD<>  D1040 D2090  ; 3#轴当前值 / 3#位置6
      SET     M1235  ; 3#  位置6
      MRD
      ANDP    M1206  ; 3#位置7（手动）
      ANDD<>  D1040 D2092  ; 3#轴当前值 / 3#位置7
      SET     M1236  ; 3#  位置7
      MRD
      ANDP    M1207  ; 3#位置8（手动）
      ANDD<>  D1040 D2094  ; 3#轴当前值 / 3#位置8
      SET     M1237  ; 3#  位置8
      MRD
      ANDP    M1208  ; 3#位置9（手动）
      ANDD<>  D1040 D2096  ; 3#轴当前值 / 3#位置9
      SET     M1238  ; 3#  位置9
      MPP
      ANDP    M1209  ; 3#位置10（手动）
      ANDD<>  D1040 D2098  ; 3#轴当前值 / 3#位置10
      SET     M1239  ; 3#  位置10
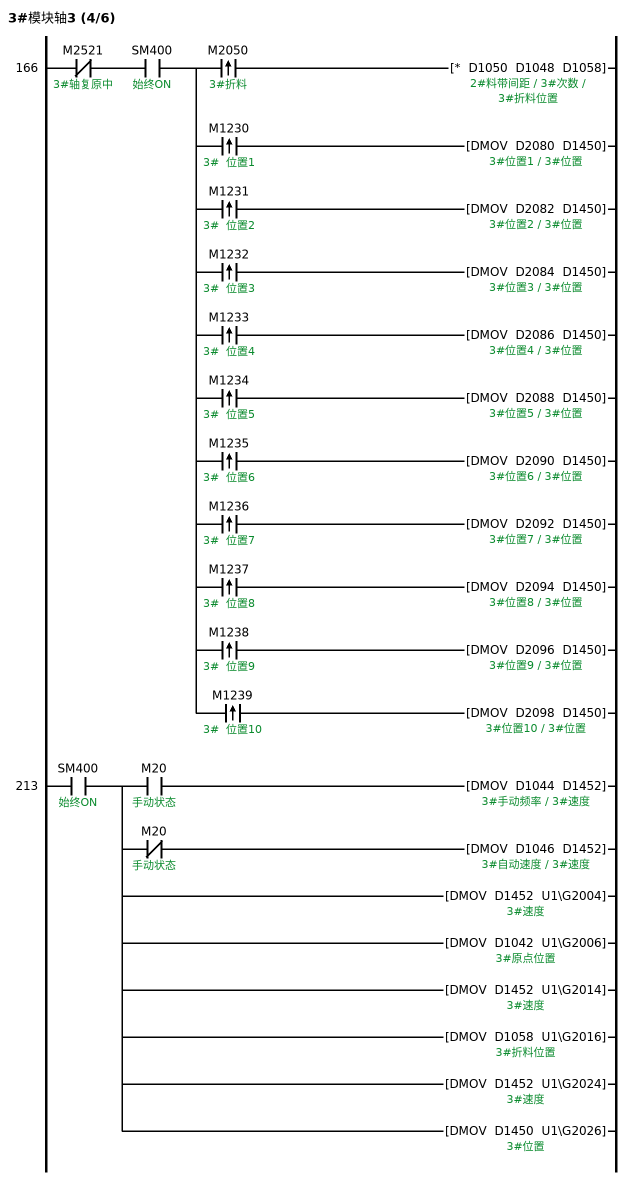
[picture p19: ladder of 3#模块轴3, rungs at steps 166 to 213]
166   LDI     M2521  ; 3#轴复原中
      AND     SM400  ; 始终ON
      MPS
      ANDP    M2050  ; 3#折料
      *       D1050 D1048 D1058  ; 2#料带间距 / 3#次数 / 3#折料位置
      MRD
      ANDP    M1230  ; 3#  位置1
      DMOV    D2080 D1450  ; 3#位置
      MRD
      ANDP    M1231  ; 3#  位置2
      DMOV    D2082 D1450
      MRD
      ANDP    M1232  ; 3#  位置3
      DMOV    D2084 D1450
      MRD
      ANDP    M1233  ; 3#  位置4
      DMOV    D2086 D1450
      MRD
      ANDP    M1234  ; 3#  位置5
      DMOV    D2088 D1450
      MRD
      ANDP    M1235  ; 3#  位置6
      DMOV    D2090 D1450
      MRD
      ANDP    M1236  ; 3#  位置7
      DMOV    D2092 D1450
      MRD
      ANDP    M1237  ; 3#  位置8
      DMOV    D2094 D1450
      MRD
      ANDP    M1238  ; 3#  位置9
      DMOV    D2096 D1450
      MPP
      ANDP    M1239  ; 3#  位置10
      DMOV    D2098 D1450
213   LD      SM400  ; 始终ON
      MPS
      AND     M20  ; 手动状态
      DMOV    D1044 D1452  ; 3#手动频率 / 3#速度
      MRD
      ANI     M20  ; 手动状态
      DMOV    D1046 D1452  ; 3#自动速度
      MPP
      DMOV    D1452 U1\G2004
      DMOV    D1042 U1\G2006  ; 3#原点位置
      DMOV    D1452 U1\G2014
      DMOV    D1058 U1\G2016
      DMOV    D1452 U1\G2024
      DMOV    D1450 U1\G2026
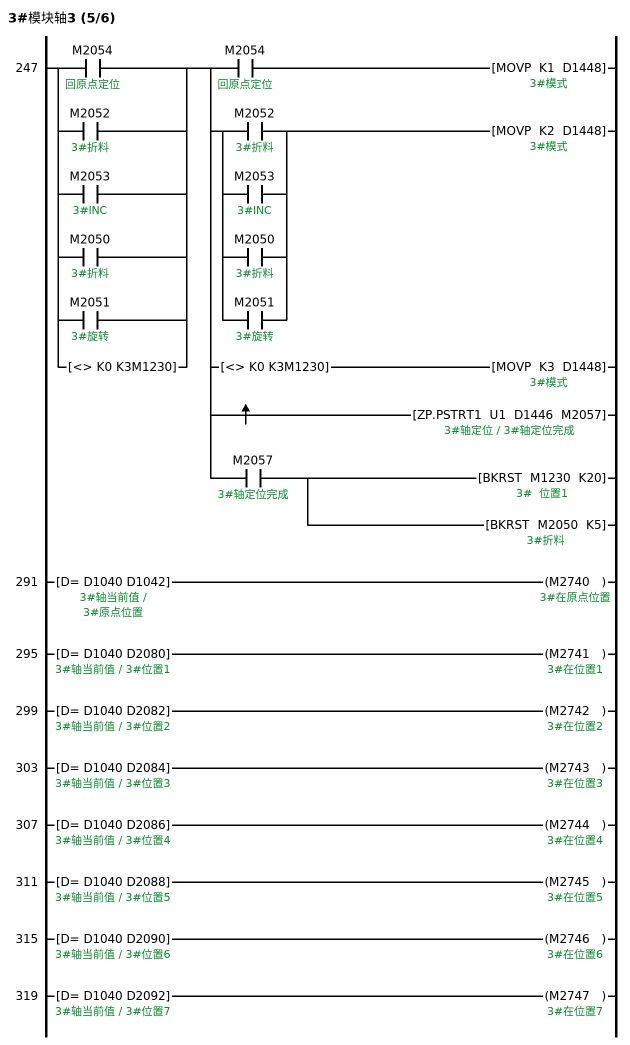
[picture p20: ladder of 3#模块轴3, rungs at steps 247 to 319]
247   LD      M2054  ; 回原点定位
      OR      M2052  ; 3#折料
      OR      M2053  ; 3#INC
      OR      M2050  ; 3#折料
      OR      M2051  ; 3#旋转
      OR<>    K0 K3M1230  ; 3#  位置1
      MPS
      AND     M2054  ; 回原点定位
      MOVP    K1 D1448  ; 3#模式
      MRD
      LD      M2052  ; 3#折料
      OR      M2053  ; 3#INC
      OR      M2050  ; 3#折料
      OR      M2051  ; 3#旋转
      ANB
      MOVP    K2 D1448
      MRD
      AND<>   K0 K3M1230  ; 3#  位置1
      MOVP    K3 D1448
      MRD
      MEP
      ZP.PSTRT1 U1 D1446 M2057  ; 3#轴定位
      MPP
      AND     M2057  ; 3#轴定位完成
      BKRST   M1230 K20
      BKRST   M2050 K5
291   LDD=    D1040 D1042  ; 3#轴当前值 / 3#原点位置
      OUT     M2740  ; 3#在原点位置
295   LDD=    D1040 D2080  ; 3#轴当前值 / 3#位置1
      OUT     M2741  ; 3#在位置1
299   LDD=    D1040 D2082  ; 3#轴当前值 / 3#位置2
      OUT     M2742  ; 3#在位置2
303   LDD=    D1040 D2084  ; 3#轴当前值 / 3#位置3
      OUT     M2743  ; 3#在位置3
307   LDD=    D1040 D2086  ; 3#轴当前值 / 3#位置4
      OUT     M2744  ; 3#在位置4
311   LDD=    D1040 D2088  ; 3#轴当前值 / 3#位置5
      OUT     M2745  ; 3#在位置5
315   LDD=    D1040 D2090  ; 3#轴当前值 / 3#位置6
      OUT     M2746  ; 3#在位置6
319   LDD=    D1040 D2092  ; 3#轴当前值 / 3#位置7
      OUT     M2747  ; 3#在位置7
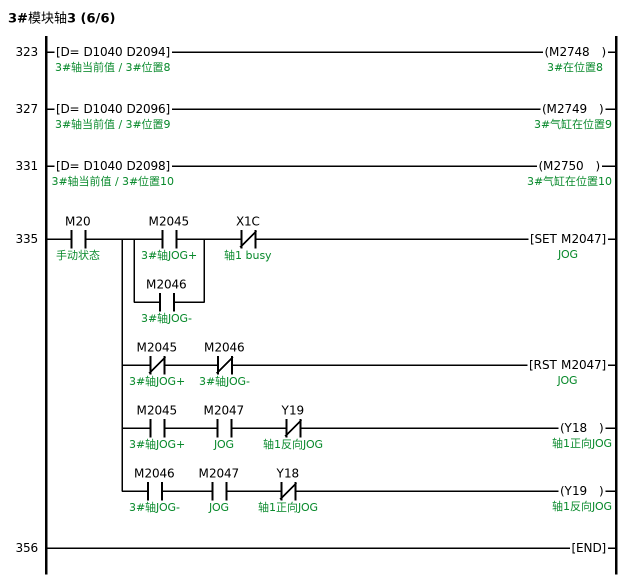
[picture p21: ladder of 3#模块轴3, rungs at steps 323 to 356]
323   LDD=    D1040 D2094  ; 3#轴当前值 / 3#位置8
      OUT     M2748  ; 3#在位置8
327   LDD=    D1040 D2096  ; 3#轴当前值 / 3#位置9
      OUT     M2749  ; 3#气缸在位置9
331   LDD=    D1040 D2098  ; 3#轴当前值 / 3#位置10
      OUT     M2750  ; 3#气缸在位置10
335   LD      M20  ; 手动状态
      MPS
      LD      M2045  ; 3#轴JOG+
      OR      M2046  ; 3#轴JOG-
      ANB
      ANI     X1C  ; 轴1 busy
      SET     M2047  ; JOG
      MRD
      ANI     M2045  ; 3#轴JOG+
      ANI     M2046  ; 3#轴JOG-
      RST     M2047  ; JOG
      MRD
      AND     M2045  ; 3#轴JOG+
      AND     M2047  ; JOG
      ANI     Y19  ; 轴1反向JOG
      OUT     Y18  ; 轴1正向JOG
      MPP
      AND     M2046  ; 3#轴JOG-
      AND     M2047  ; JOG
      ANI     Y18  ; 轴1正向JOG
      OUT     Y19  ; 轴1反向JOG
356   END
END_PROGRAM

PROGRAM 4#模块轴4
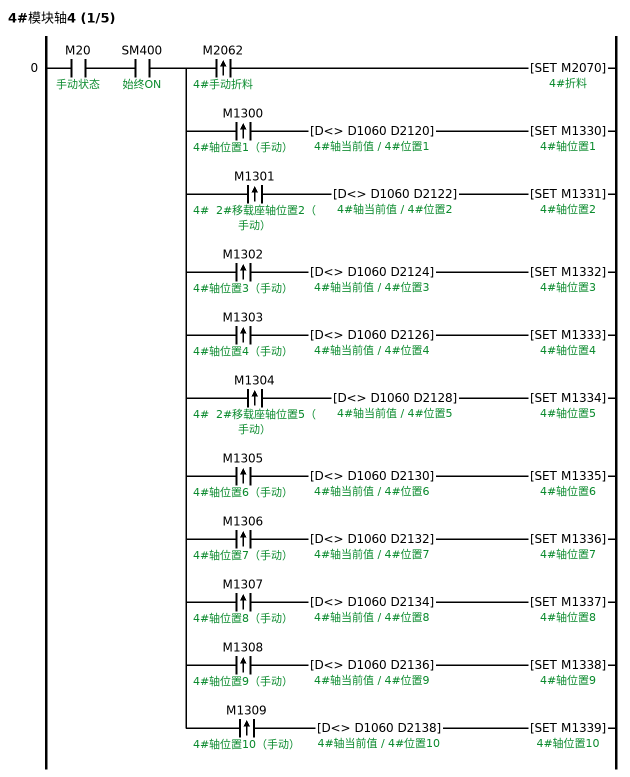
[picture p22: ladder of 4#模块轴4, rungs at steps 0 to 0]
0     LD      M20  ; 手动状态
      AND     SM400  ; 始终ON
      MPS
      ANDP    M2062  ; 4#手动折料
      SET     M2070  ; 4#折料
      MRD
      ANDP    M1300  ; 4#轴位置1（手动）
      ANDD<>  D1060 D2120  ; 4#轴当前值 / 4#位置1
      SET     M1330  ; 4#轴位置1
      MRD
      ANDP    M1301  ; 4#  2#移载座轴位置2（手动）
      ANDD<>  D1060 D2122  ; 4#轴当前值 / 4#位置2
      SET     M1331  ; 4#轴位置2
      MRD
      ANDP    M1302  ; 4#轴位置3（手动）
      ANDD<>  D1060 D2124  ; 4#轴当前值 / 4#位置3
      SET     M1332  ; 4#轴位置3
      MRD
      ANDP    M1303  ; 4#轴位置4（手动）
      ANDD<>  D1060 D2126  ; 4#轴当前值 / 4#位置4
      SET     M1333  ; 4#轴位置4
      MRD
      ANDP    M1304  ; 4#  2#移载座轴位置5（手动）
      ANDD<>  D1060 D2128  ; 4#轴当前值 / 4#位置5
      SET     M1334  ; 4#轴位置5
      MRD
      ANDP    M1305  ; 4#轴位置6（手动）
      ANDD<>  D1060 D2130  ; 4#轴当前值 / 4#位置6
      SET     M1335  ; 4#轴位置6
      MRD
      ANDP    M1306  ; 4#轴位置7（手动）
      ANDD<>  D1060 D2132  ; 4#轴当前值 / 4#位置7
      SET     M1336  ; 4#轴位置7
      MRD
      ANDP    M1307  ; 4#轴位置8（手动）
      ANDD<>  D1060 D2134  ; 4#轴当前值 / 4#位置8
      SET     M1337  ; 4#轴位置8
      MRD
      ANDP    M1308  ; 4#轴位置9（手动）
      ANDD<>  D1060 D2136  ; 4#轴当前值 / 4#位置9
      SET     M1338  ; 4#轴位置9
      MPP
      ANDP    M1309  ; 4#轴位置10（手动）
      ANDD<>  D1060 D2138  ; 4#轴当前值 / 4#位置10
      SET     M1339  ; 4#轴位置10
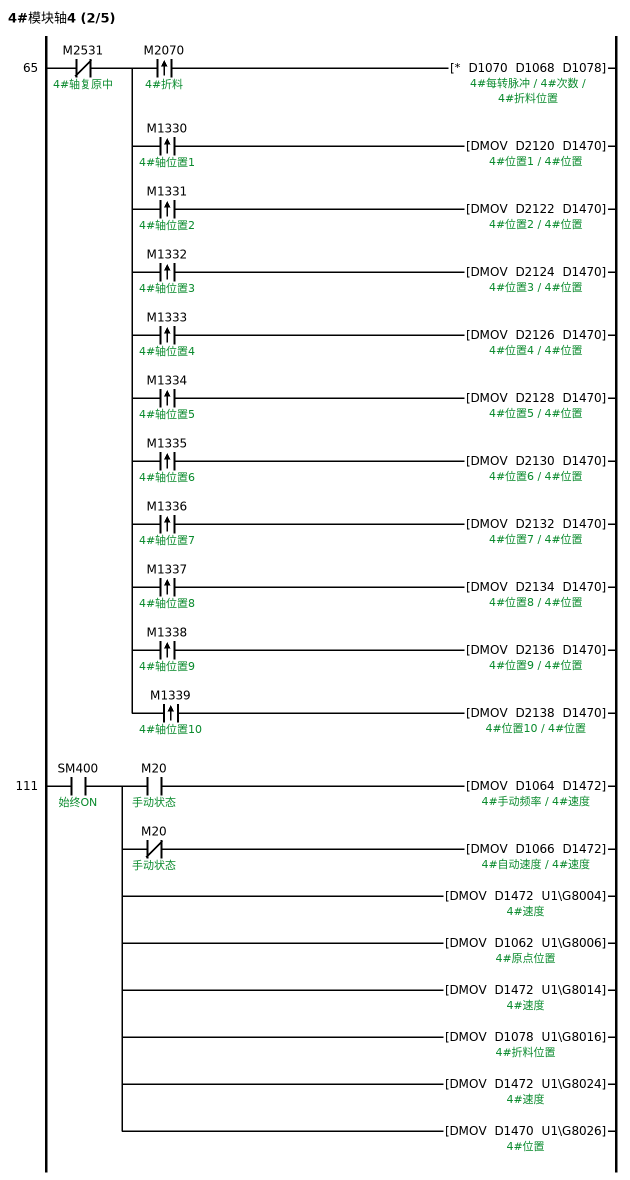
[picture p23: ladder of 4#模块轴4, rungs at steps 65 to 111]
65    LDI     M2531  ; 4#轴复原中
      MPS
      ANDP    M2070  ; 4#折料
      *       D1070 D1068 D1078  ; 4#每转脉冲 / 4#次数 / 4#折料位置
      MRD
      ANDP    M1330  ; 4#轴位置1
      DMOV    D2120 D1470  ; 4#位置
      MRD
      ANDP    M1331  ; 4#轴位置2
      DMOV    D2122 D1470
      MRD
      ANDP    M1332  ; 4#轴位置3
      DMOV    D2124 D1470
      MRD
      ANDP    M1333  ; 4#轴位置4
      DMOV    D2126 D1470
      MRD
      ANDP    M1334  ; 4#轴位置5
      DMOV    D2128 D1470
      MRD
      ANDP    M1335  ; 4#轴位置6
      DMOV    D2130 D1470
      MRD
      ANDP    M1336  ; 4#轴位置7
      DMOV    D2132 D1470
      MRD
      ANDP    M1337  ; 4#轴位置8
      DMOV    D2134 D1470
      MRD
      ANDP    M1338  ; 4#轴位置9
      DMOV    D2136 D1470
      MPP
      ANDP    M1339  ; 4#轴位置10
      DMOV    D2138 D1470
111   LD      SM400  ; 始终ON
      MPS
      AND     M20  ; 手动状态
      DMOV    D1064 D1472  ; 4#手动频率 / 4#速度
      MRD
      ANI     M20  ; 手动状态
      DMOV    D1066 D1472  ; 4#自动速度
      MPP
      DMOV    D1472 U1\G8004
      DMOV    D1062 U1\G8006  ; 4#原点位置
      DMOV    D1472 U1\G8014
      DMOV    D1078 U1\G8016
      DMOV    D1472 U1\G8024
      DMOV    D1470 U1\G8026
145   LDP     T130  ; 4#轴
      LD      M20  ; 手动状态
      ANDP    M2061  ; 4#复原
      ORB
      LDP     M20  ; 手动状态
      AND     T130  ; 4#轴
      ORF     M20  ; 手动状态
      ANI     M2760  ; 4#在原点位置
      ORB
      ORF     M2060  ; 4#伺服ON
      AND     B53F
      BKRST   B530 K10  ; 4#轴复原开始
      SET     B530  ; 4#轴复原开始
160   LD=     K0 K3B530  ; 4#轴复原开始
      OUT     B53F
      INV
      OUT     M2531  ; 4#轴复原中
166   LD      B530  ; 4#轴复原开始
      SET     B531
168   LD      B531
      RST     B530  ; 4#轴复原开始
      MOV     K9001 D1462
      MOV     K0 U1\G1621
      ZP.PSTRT2 "U1" D1460 M2075  ; 原点完成
      SET     B532
186   LD      B532
      RST     B531
      AND     M2075  ; 原点完成
      MOV     K1 U1\G1621
      SET     B533
194   LD      B533
      RST     B532
      OUT     T133 K2
      AND     T133
      SET     B534
202   LD      B534
      RST     B533
      PLS     M2074  ; 回原点定位
      ANI     M2074  ; 回原点定位
      SET     B535
208   LD      B535
      RST     B534
      AND     M2077  ; 4#定位完成
      SET     B536
212   LD      B536
      RST     B535
      DMOV    K0 U1\G1606
      MOV     K9003 U1\G1600
      MPS
      ANDP    B536
      SET     Y21  ; 轴2定位启动
      MPP
      RST     B536
228   LD      Y21  ; 轴2定位启动
      OUT     T134 K2
      AND     T134
      RST     Y21  ; 轴2定位启动
235   LD      M2074  ; 回原点定位
      OR      M2072  ; 4#折料
      OR      M2073  ; 4#INC
      OR      M2070  ; 4#折料
      OR      M2071  ; 4#旋转
      OR<>    K0 K3M1330  ; 4#轴位置1
      MPS
      AND     M2074  ; 回原点定位
      MOVP    K1 D1468  ; 4#模式
      MRD
      LD      M2072  ; 4#折料
      OR      M2073  ; 4#INC
      OR      M2070  ; 4#折料
      OR      M2071  ; 4#旋转
      ANB
      MOVP    K2 D1468
      MRD
      AND<>   K0 K3M1330  ; 4#轴位置1
      MOVP    K3 D1468
      MRD
      MEP
      ZP.PSTRT2 U1 D1466 M2077  ; 4#轴定位
      MPP
      AND     M2077  ; 4#定位完成
      BKRST   M2070 K5
      BKRST   M1330 K20
279   LDD=    D1060 D1062  ; 4#轴当前值 / 4#原点位置
      OUT     M2760  ; 4#在原点位置
283   LDD=    D1060 D2120  ; 4#轴当前值 / 4#位置1
      OUT     M2761  ; 4#在位置1
287   LDD=    D1060 D2122  ; 4#轴当前值 / 4#位置2
      OUT     M2762  ; 4#在位置2
291   LDD=    D1060 D2124  ; 4#轴当前值 / 4#位置3
      OUT     M2763  ; 4#在位置3
295   LDD=    D1060 D2126  ; 4#轴当前值 / 4#位置4
      OUT     M2764  ; 4#在位置4
299   LDD=    D1060 D2128  ; 4#轴当前值 / 4#位置5
      OUT     M2765  ; 4#在位置5
303   LDD=    D1060 D2130  ; 4#轴当前值 / 4#位置6
      OUT     M2766  ; 4#在位置6
307   LDD=    D1060 D2132  ; 4#轴当前值 / 4#位置7
      OUT     M2767  ; 4#在位置7
311   LDD=    D1060 D2134  ; 4#轴当前值 / 4#位置8
      OUT     M2768  ; 4#在位置8
315   LDD=    D1060 D2136  ; 4#轴当前值 / 4#位置9
      OUT     M2769  ; 4#在位置9
319   LDD=    D1060 D2138  ; 4#轴当前值 / 4#位置10
      OUT     M2770  ; 4#在位置10
323   LD      M20  ; 手动状态
      MPS
      LD      M2065  ; 4#轴JOG+
      OR      M2066  ; 4#轴JOG-
      ANB
      ANI     X1D  ; 轴2 busy
      SET     M2067  ; 4#JOG
      MRD
      ANI     M2065  ; 4#轴JOG+
      ANI     M2066  ; 4#轴JOG-
      RST     M2067  ; 4#JOG
      MRD
      AND     M2065  ; 4#轴JOG+
      AND     M2067  ; 4#JOG
      ANI     Y1B  ; 轴2反向JOG
      OUT     Y1A  ; 轴2正向JOG
      MPP
      AND     M2066  ; 4#轴JOG-
      AND     M2067  ; 4#JOG
      ANI     Y1A  ; 轴2正向JOG
      OUT     Y1B  ; 轴2反向JOG
344   END
END_PROGRAM

PROGRAM 5#模块轴5
0     LD      M20  ; 手动状态
      MPS
      ANDP    M2082  ; 5#手动折料
      SET     M2090  ; 5#折料
      MRD
      ANDP    M1400  ; 5#位置1（手动）
      ANDD<>  D1080 D2160  ; 5#轴当前值 / 5#轴位置1
      SET     M1430  ; 5#轴位置1
      MRD
      ANDP    M1401  ; 5#位置2（手动）
      ANDD<>  D1080 D2162  ; 5#轴当前值 / 5#轴位置2
      SET     M1431  ; 5#轴位置2
      MRD
      ANDP    M1402  ; 5#位置3（手动）
      ANDD<>  D1080 D2164  ; 5#轴当前值 / 5#轴位置3
      SET     M1432  ; 5#轴位置3
      MRD
      ANDP    M1403  ; 5#位置4（手动）
      ANDD<>  D1080 D2166  ; 5#轴当前值 / 5#轴位置4
      SET     M1433  ; 5#轴位置4
      MRD
      ANDP    M1404  ; 5#位置5（手动）
      ANDD<>  D1080 D2168  ; 5#轴当前值 / 5#轴位置5
      SET     M1434  ; 5#轴位置5
      MRD
      ANDP    M1405  ; 5#位置6（手动）
      ANDD<>  D1080 D2170  ; 5#轴当前值 / 5#轴位置6
      SET     M1435  ; 5#轴位置6
      MRD
      ANDP    M1406  ; 5#位置7（手动）
      ANDD<>  D1080 D2172  ; 5#轴当前值 / 5#轴位置7
      SET     M1436  ; 5#轴位置7
      MRD
      ANDP    M1407  ; 5#位置8（手动）
      ANDD<>  D1080 D2174  ; 5#轴当前值 / 5#轴位置8
      SET     M1437  ; 5#轴位置8
      MRD
      ANDP    M1408  ; 5#位置9（手动）
      ANDD<>  D1080 D2176  ; 5#轴当前值 / 5#轴位置9
      SET     M1438  ; 5#轴位置9
      MPP
      ANDP    M1409  ; 5#位置10（手动）
      ANDD<>  D1080 D2178  ; 5#轴当前值 / 5#轴位置10
      SET     M1439  ; 5#轴位置10
64    LDI     M2541  ; 5#轴复原中
      MPS
      ANDP    M2090  ; 5#折料
      *       D1090 D1088 D1098  ; 5#每转脉冲 / 5#次数 / 5#折料
      MRD
      ANDP    M1430  ; 5#轴位置1
      DMOV    D2160 D1490  ; 5#位置
      MRD
      ANDP    M1431  ; 5#轴位置2
      DMOV    D2162 D1490
      MRD
      ANDP    M1432  ; 5#轴位置3
      DMOV    D2164 D1490
      MRD
      ANDP    M1433  ; 5#轴位置4
      DMOV    D2166 D1490
      MRD
      ANDP    M1434  ; 5#轴位置5
      DMOV    D2168 D1490
      MRD
      ANDP    M1435  ; 5#轴位置6
      DMOV    D2170 D1490
      MRD
      ANDP    M1436  ; 5#轴位置7
      DMOV    D2172 D1490
      MRD
      ANDP    M1437  ; 5#轴位置8
      DMOV    D2174 D1490
      MRD
      ANDP    M1438  ; 5#轴位置9
      DMOV    D2176 D1490
      MPP
      ANDP    M1439  ; 5#轴位置10
      DMOV    D2178 D1490
110   LD      SM400  ; 始终ON
      MPS
      AND     M20  ; 手动状态
      DMOV    D1084 D1492  ; 5#手动频率 / 5#速度
      MRD
      ANI     M20  ; 手动状态
      DMOV    D1086 D1492  ; 5#自动速度
      MPP
      DMOV    D1492 U1\G14004
      DMOV    D1082 U1\G14006  ; 5#原点位置
      DMOV    D1492 U1\G14014
      DMOV    D1098 U1\G14016
      DMOV    D1492 U1\G14024
      DMOV    D1490 U1\G14026
144   LDP     T140  ; 5#轴
      LD      M20  ; 手动状态
      ANDP    M2081  ; 5#复原
      ORB
      LD      T140  ; 5#轴
      ANDP    M20  ; 手动状态
      ORF     M20  ; 手动状态
      ANI     M2780  ; 5#在原点位置
      ORB
      ORF     M2080  ; 5#伺服ON
      AND     B54F
      BKRST   B540 K10  ; 5#轴复原开始
      SET     B540  ; 5#轴复原开始
159   LD=     K0 K3B540  ; 5#轴复原开始
      OUT     B54F
      INV
      OUT     M2541  ; 5#轴复原中
165   LD      B540  ; 5#轴复原开始
      SET     B541
      RST     B540  ; 5#轴复原开始
168   LD      B541
      RST     B540  ; 5#轴复原开始
      MOV     K9001 D1482
      MOV     K0 U1\G1721
      ZP.PSTRT3 "U1" D1480 M2095  ; 原点完成
      SET     B542
186   LD      B542
      RST     B541
      AND     M2095  ; 原点完成
      MOV     K1 U1\G1721
      SET     B543
194   LD      B543
      RST     B542
      OUT     T143 K2
      AND     T143
      SET     B544
202   LD      B544
      RST     B543
      PLS     M2094  ; 回原点定位
      ANI     M2094  ; 回原点定位
      SET     B545
208   LD      B545
      RST     B544
      AND     M2097  ; 5#轴定位完成
      SET     B546
212   LD      B546
      RST     B545
      DMOV    K0 U1\G1706
      MOV     K9003 U1\G1700
      MPS
      ANDP    B546
      SET     Y22  ; 轴+3定位启动
      MPP
      RST     B546
228   LD      Y22  ; 轴+3定位启动
      OUT     T144 K2
      AND     T144
      RST     Y22  ; 轴+3定位启动
235   LD      M2094  ; 回原点定位
      OR      M2092  ; 5#折料
      OR      M2093  ; 5#INC
      OR      M2090  ; 5#折料
      OR      M2091  ; 5#旋转
      OR<>    K0 K3M1430  ; 5#轴位置1
      MPS
      AND     M2094  ; 回原点定位
      MOVP    K1 D1488  ; 5#模式
      MRD
      LD      M2092  ; 5#折料
      OR      M2093  ; 5#INC
      OR      M2090  ; 5#折料
      OR      M2091  ; 5#旋转
      ANB
      MOVP    K2 D1488
      MRD
      AND<>   K0 K3M1430  ; 5#轴位置1
      MOVP    K3 D1488
      MRD
      MEP
      ZP.PSTRT3 U1 D1486 M2097  ; 5#轴定位
      MPP
      AND     M2097  ; 5#轴定位完成
      BKRST   M2090 K5
      BKRST   M1430 K20
279   LDD=    D1080 D1082  ; 5#轴当前值 / 5#原点位置
      OUT     M2780  ; 5#在原点位置
283   LDD=    D1080 D2160  ; 5#轴当前值 / 5#轴位置1
      OUT     M2781  ; 5#在位置1
287   LDD=    D1080 D2162  ; 5#轴当前值 / 5#轴位置2
      OUT     M2782  ; 5#在位置2
291   LDD=    D1080 D2164  ; 5#轴当前值 / 5#轴位置3
      OUT     M2783  ; 5#在位置3
295   LDD=    D1080 D2166  ; 5#轴当前值 / 5#轴位置4
      OUT     M2784  ; 5#在位置4
299   LDD=    D1080 D2168  ; 5#轴当前值 / 5#轴位置5
      OUT     M2785  ; 5#在位置5
303   LDD=    D1080 D2170  ; 5#轴当前值 / 5#轴位置6
      OUT     M2786  ; 5#在位置6
307   LDD=    D1080 D2172  ; 5#轴当前值 / 5#轴位置7
      OUT     M2787  ; 5#在位置7
311   LDD=    D1080 D2174  ; 5#轴当前值 / 5#轴位置8
      OUT     M2788  ; 5#在位置8
315   LDD=    D1080 D2176  ; 5#轴当前值 / 5#轴位置9
      OUT     M2789  ; 5#在位置9
319   LDD=    D1080 D2178  ; 5#轴当前值 / 5#轴位置10
      OUT     M2790  ; 5#在位置10
323   LD      M20  ; 手动状态
      MPS
      LD      M2085  ; 5#JOG+
      OR      M2086  ; 5#JOG-
      ANB
      ANI     X1E  ; 轴3 busy
      SET     M2087  ; 5#JOG
      MRD
      ANI     M2085  ; 5#JOG+
      ANI     M2086  ; 5#JOG-
      RST     M2087  ; 5#JOG
      MRD
      AND     M2085  ; 5#JOG+
      AND     M2087  ; 5#JOG
      ANI     Y1D  ; 轴3反向JOG
      OUT     Y1C  ; 轴3正向JOG
      MPP
      AND     M2086  ; 5#JOG-
      AND     M2087  ; 5#JOG
      ANI     Y1C  ; 轴3正向JOG
      OUT     Y1D  ; 轴3反向JOG
344   END
END_PROGRAM

PROGRAM 6#模块轴6
0     LD      M20  ; 手动状态
      MPS
      ANDP    M2102  ; 6#手动折料
      SET     M2110  ; 6#折料
      MRD
      ANDP    M1500  ; 6#轴位置1（手动）
      ANDD<>  D1100 D2200  ; 6#轴当前值 / 6#轴位置1
      SET     M1530  ; 6#轴位置1
      MRD
      ANDP    M1501  ; 6#轴位置2（手动）
      ANDD<>  D1100 D2202  ; 6#轴当前值 / 6#轴位置2
      SET     M1531  ; 6#轴位置2
      MRD
      ANDP    M1502  ; 6#轴位置3（手动）
      ANDD<>  D1100 D2204  ; 6#轴当前值 / 6#轴位置3
      SET     M1532  ; 6#轴位置3
      MRD
      ANDP    M1503  ; 6#轴位置4（手动）
      ANDD<>  D1100 D2206  ; 6#轴当前值 / 6#轴位置4
      SET     M1533  ; 6#轴位置4
      MRD
      ANDP    M1504  ; 6#轴位置5（手动）
      ANDD<>  D1100 D2208  ; 6#轴当前值 / 6#轴位置5
      SET     M1534  ; 6#轴位置5
      MRD
      ANDP    M1505  ; 6#轴位置6（手动）
      ANDD<>  D1100 D2210  ; 6#轴当前值 / 6#轴位置6
      SET     M1535  ; 6#轴位置6
      MRD
      ANDP    M1506  ; 6#轴位置7（手动）
      ANDD<>  D1100 D2212  ; 6#轴当前值 / 6#轴位置7
      SET     M1536  ; 6#轴位置7
      MRD
      ANDP    M1507  ; 6#轴位置8（手动）
      ANDD<>  D1100 D2214  ; 6#轴当前值 / 6#轴位置8
      SET     M1537  ; 6#轴位置8
      MRD
      ANDP    M1508  ; 6#轴位置9（手动）
      ANDD<>  D1100 D2216  ; 6#轴当前值 / 6#轴位置9
      SET     M1538  ; 6#轴位置9
      MPP
      ANDP    M1509  ; 6#轴位置10（手动）
      ANDD<>  D1100 D2218  ; 6#轴当前值 / 6#轴位置10
      SET     M1540  ; 6#轴位置11
64    LDI     M2551  ; 6#轴复原中
      AND     SM400  ; 始终ON
      MPS
      ANDP    M2110  ; 6#折料
      *       D1110 D1108 D1118  ; 6#每转脉冲 / 6#次数 / 6#折料位置
      MRD
      ANDP    M1530  ; 6#轴位置1
      DMOV    D2200 D1510  ; 6#位置
      MRD
      ANDP    M1531  ; 6#轴位置2
      DMOV    D2202 D1510
      MRD
      ANDP    M1532  ; 6#轴位置3
      DMOV    D2204 D1510
      MRD
      ANDP    M1533  ; 6#轴位置4
      DMOV    D2206 D1510
      MRD
      ANDP    M1534  ; 6#轴位置5
      DMOV    D2208 D1510
      MRD
      ANDP    M1535  ; 6#轴位置6
      DMOV    D2210 D1510
      MRD
      ANDP    M1536  ; 6#轴位置7
      DMOV    D2212 D1510
      MRD
      ANDP    M1535  ; 6#轴位置6
      DMOV    D2214 D1510
      MRD
      ANDP    M1538  ; 6#轴位置9
      DMOV    D2216 D1510
      MPP
      ANDP    M1539  ; 6#轴位置10
      DMOV    D2218 D1510
111   LD      SM400  ; 始终ON
      MPS
      AND     M20  ; 手动状态
      DMOV    D1104 D1512  ; 6#手动频率 / 6#速度
      MRD
      ANI     M20  ; 手动状态
      DMOV    D1106 D1512  ; 6#自动速度
      MPP
      DMOV    D1512 U1\G20004
      DMOV    D1102 U1\G20006  ; 6#原点位置
      DMOV    D1512 U1\G20014
      DMOV    D1118 U1\G20016
      DMOV    D1512 U1\G20024
      DMOV    D1510 U1\G20026
145   LDP     T150  ; 6#轴
      LD      M20  ; 手动状态
      ANDP    M2101  ; 6#复原
      ORB
      LD      T150  ; 6#轴
      ANDP    M20  ; 手动状态
      ORF     M20  ; 手动状态
      ANI     M2800  ; 6#在原点位置
      ORB
      ORF     M2100  ; 6#伺服ON
      AND     B55F
      BKRST   B550 K10  ; 6#轴复原开始
      SET     B550  ; 6#轴复原开始
160   LD=     K0 K3B550  ; 6#轴复原开始
      OUT     B55F
      INV
      OUT     M2551  ; 6#轴复原中
166   LD      B550  ; 6#轴复原开始
      SET     B551
      RST     B550  ; 6#轴复原开始
169   LD      B551
      RST     B550  ; 6#轴复原开始
      MOV     K9001 D1502  ; 位置2
      MOV     K0 U1\G1821
      ZP.PSTRT4 "U1" D1500 M2115  ; 位置1 / 原点完成
      SET     B552
187   LD      B552
      RST     B551
      AND     M2115  ; 原点完成
      MOV     K1 U1\G1821
      SET     B553
195   LD      B553
      RST     B552
      OUT     T153 K2
      AND     T153
      SET     B554
203   LD      B554
      RST     B553
      PLS     M2114  ; 回原点定位
      ANI     M2114  ; 回原点定位
      SET     B555
209   LD      B555
      RST     B554
      AND     M2117  ; 6#轴定位完成
      SET     B556
213   LD      B556
      RST     B555
      DMOV    K0 U1\G1806
      MOV     K9003 U1\G1800
      MPS
      ANDP    B556
      SET     Y23  ; 轴4定位启动
      MPP
      RST     B556
229   LD      Y23  ; 轴4定位启动
      OUT     T154 K2
      AND     T154
      RST     Y23  ; 轴4定位启动
236   LD      M2114  ; 回原点定位
      OR      M2112  ; 6#折料
      OR      M2113  ; 6#INC
      OR      M2110  ; 6#折料
      OR      M2111  ; 6#手动旋转
      OR<>    K0 K2M1530  ; 6#轴位置1
      MPS
      AND     M2114  ; 回原点定位
      MOVP    K1 D1508  ; 6#模式
      MRD
      LD      M2112  ; 6#折料
      OR      M2113  ; 6#INC
      OR      M2110  ; 6#折料
      OR      M2111  ; 6#手动旋转
      ANB
      MOVP    K2 D1508
      MRD
      AND<>   K0 K2M1530  ; 6#轴位置1
      MOVP    K3 D1508
      MRD
      MEP
      ZP.PSTRT4 U1 D1506 M2117  ; 6#轴定位
      MPP
      AND     M2117  ; 6#轴定位完成
      BKRST   M1530 K20
      BKRST   M2110 K5
280   LDD=    D1100 D1102  ; 6#轴当前值 / 6#原点位置
      OUT     M2800  ; 6#在原点位置
284   LDD=    D1100 D2200  ; 6#轴当前值 / 6#轴位置1
      OUT     M2801  ; 6#在位置1
288   LDD=    D1100 D2202  ; 6#轴当前值 / 6#轴位置2
      OUT     M2802  ; 6#在位置2
292   LDD=    D1100 D2204  ; 6#轴当前值 / 6#轴位置3
      OUT     M2803  ; 6#在位置3
296   LDD=    D1100 D2206  ; 6#轴当前值 / 6#轴位置4
      OUT     M2804  ; 6#在位置4
300   LDD=    D1100 D2208  ; 6#轴当前值 / 6#轴位置5
      OUT     M2805  ; 6#在位置5
304   LDD=    D1100 D2210  ; 6#轴当前值 / 6#轴位置6
      OUT     M2806  ; 6#在位置6
308   LDD=    D1100 D2212  ; 6#轴当前值 / 6#轴位置7
      OUT     M2807  ; 6#在位置7
312   LDD=    D1100 D2214  ; 6#轴当前值 / 6#轴位置8
      OUT     M2808  ; 6#在位置8
316   LDD=    D1100 D2216  ; 6#轴当前值 / 6#轴位置9
      OUT     M2809  ; 6#在位置9
320   LDD=    D1100 D2218  ; 6#轴当前值 / 6#轴位置10
      OUT     M2810  ; 6#在位置10
324   LD      M20  ; 手动状态
      MPS
      LD      M2105  ; 6#JOG+
      OR      M2106  ; 6#JOG-
      ANB
      ANI     X1F  ; 轴4 busy
      SET     M2107  ; 6#JOG
      MRD
      ANI     M2105  ; 6#JOG+
      ANI     M2106  ; 6#JOG-
      RST     M2107  ; 6#JOG
      MRD
      AND     M2105  ; 6#JOG+
      AND     M2107  ; 6#JOG
      ANI     Y1F  ; 轴4反向JOG
      OUT     Y1E  ; 轴4正向JOG
      MPP
      AND     M2106  ; 6#JOG-
      AND     M2107  ; 6#JOG
      ANI     Y1E  ; 轴4正向JOG
      OUT     Y1F  ; 轴4反向JOG
345   END
END_PROGRAM

PROGRAM 7#模块轴7
0     LDP     T160  ; 7#轴
      LD      M20  ; 手动状态
      ANDP    M2121  ; 7#复原
      ORB
      LD      T160  ; 7#轴
      ANDP    M20  ; 手动状态
      ORF     M20  ; 手动状态
      ANI     M2820  ; 7#在原点位置
      ORB
      ORF     M2120  ; 7#伺服ON
      AND     B56F
      BKRST   B560 K10  ; 7#轴复原开始
      SET     B560  ; 7#轴复原开始
15    LD=     K0 K3B560  ; 7#轴复原开始
      OUT     B56F
      INV
      OUT     M2561  ; 7#轴复原中
21    LD      B560  ; 7#轴复原开始
      SET     B561
      RST     B560  ; 7#轴复原开始
24    LD      B561
      RST     B560  ; 7#轴复原开始
      MOV     K9001 D1522
      MOV     K0 U3\G1521
      ZP.PSTRT1 "U3" D1520 M2135  ; 原点完成
      SET     B562
42    LD      B562
      RST     B561
      AND     M2135  ; 原点完成
      MOV     K1 U3\G1521
      SET     B563
50    LD      B563
      RST     B562
      OUT     T163 K2
      AND     T163
      SET     B564
58    LD      B564
      RST     B563
      PLS     M2134  ; 回原点定位
      ANI     M2134  ; 回原点定位
      SET     B565
64    LD      B565
      RST     B564
      AND     M2137  ; 7#轴定位完成
      SET     B566
68    LD      B566
      RST     B565
      DMOV    K0 U3\G1506
      MOV     K9003 U3\G1500
      MPS
      ANDP    B566
      SET     Y40  ; 2#轴1定位启动
      MPP
      RST     B566
84    LD      Y40  ; 2#轴1定位启动
      OUT     T164 K2
      AND     T164
      RST     Y40  ; 2#轴1定位启动
91    LD      M20  ; 手动状态
      AND     SM400  ; 始终ON
      MPS
      AND     M2122  ; 7#手动折料
      SET     M2130  ; 7#折料
      MRD
      ANDP    M1600  ; 7#轴位置1（手动）
      ANDD<>  D1120 D2240  ; 7#当前值 / 7#轴位置1
      SET     M1630  ; 7#轴位置1
      MRD
      ANDP    M1601  ; 7#轴位置2（手动）
      ANDD<>  D1120 D2242  ; 7#当前值 / 7#轴位置2
      SET     M1631  ; 7#轴位置2
      MRD
      ANDP    M1602  ; 7#轴位置3（手动）
      ANDD<>  D1120 D2244  ; 7#当前值 / 7#轴位置3
      SET     M1632  ; 7#轴位置3
      MRD
      ANDP    M1603  ; 7#轴位置4（手动）
      ANDD<>  D1120 D2246  ; 7#当前值 / 7#轴位置4
      SET     M1633  ; 7#轴位置4
      MRD
      ANDP    M1604  ; 7#轴位置5（手动）
      ANDD<>  D1120 D2248  ; 7#当前值 / 7#轴位置5
      SET     M1634  ; 7#轴位置5
      MRD
      ANDP    M1605  ; 7#轴位置6（手动）
      ANDD<>  D1120 D2250  ; 7#当前值 / 7#轴位置6
      SET     M1635  ; 7#轴位置6
      MRD
      ANDP    M1606  ; 7#轴位置7（手动）
      ANDD<>  D1120 D2252  ; 7#当前值 / 7#轴位置7
      SET     M1636  ; 7#轴位置7
      MRD
      ANDP    M1607  ; 7#轴位置8（手动）
      ANDD<>  D1120 D2254  ; 7#当前值 / 7#轴位置8
      SET     M1637  ; 7#轴位置8
      MRD
      ANDP    M1608  ; 7#轴位置9（手动）
      ANDD<>  D1120 D2256  ; 7#当前值 / 7#轴位置9
      SET     M1638  ; 7#轴位置9
      MPP
      ANDP    M1609  ; 7#轴位置10（手动）
      ANDD<>  D1120 D2258  ; 7#当前值 / 7#轴位置10
      SET     M1639  ; 7#轴位置10
156   LDI     M2561  ; 7#轴复原中
      MPS
      ANDP    M2130  ; 7#折料
      *       D1130 D1128 D1138  ; 7#每转脉冲 / 7#次数 / 7#折料位置
      MRD
      ANDP    M1630  ; 7#轴位置1
      DMOV    D2240 D1530  ; 7#位置
      MRD
      ANDP    M1631  ; 7#轴位置2
      DMOV    D2242 D1530
      MRD
      ANDP    M1632  ; 7#轴位置3
      DMOV    D2244 D1530
      MRD
      ANDP    M1633  ; 7#轴位置4
      DMOV    D2246 D1530
      MRD
      ANDP    M1634  ; 7#轴位置5
      DMOV    D2248 D1530
      MRD
      ANDP    M1635  ; 7#轴位置6
      DMOV    D2250 D1530
      MRD
      ANDP    M1636  ; 7#轴位置7
      DMOV    D2252 D1530
      MRD
      ANDP    M1637  ; 7#轴位置8
      DMOV    D2254 D1530
      MRD
      ANDP    M1638  ; 7#轴位置9
      DMOV    D2256 D1530
      MPP
      ANDP    M1639  ; 7#轴位置10
      DMOV    D2258 D1530
202   LD      SM400  ; 始终ON
      MPS
      AND     M20  ; 手动状态
      DMOV    D1124 D1532  ; 7#手动频率 / 7#速度
      MRD
      ANI     M20  ; 手动状态
      DMOV    D1126 D1532  ; 7#自动速度
      MPP
      DMOV    D1532 U3\G2004
      DMOV    D1122 U3\G2006  ; 7#原点位置
      DMOV    D1532 U3\G2014
      DMOV    D1138 U3\G2016
      DMOV    D1532 U3\G2024
      DMOV    D1530 U3\G2026
236   LD      M2134  ; 回原点定位
      OR      M2132  ; 7#折料
      OR      M2133  ; 7#INC
      OR      M2130  ; 7#折料
      OR      M2131  ; 7#手动旋转
      OR<>    K0 K3M1630  ; 7#轴位置1
      MPS
      AND     M2134  ; 回原点定位
      MOVP    K1 D1528  ; 7#模式
      MRD
      LD      M2132  ; 7#折料
      OR      M2133  ; 7#INC
      OR      M2130  ; 7#折料
      OR      M2131  ; 7#手动旋转
      ANB
      MOVP    K2 D1528
      MRD
      AND<>   K0 K3M1630  ; 7#轴位置1
      MOVP    K3 D1528
      MRD
      MEP
      ZP.PSTRT1 U3 D1526 M2137  ; 7#轴定位
      MPP
      AND     M2137  ; 7#轴定位完成
      BKRST   M1630 K20
      BKRST   M2130 K5
280   LDD=    D1120 D1122  ; 7#当前值 / 7#原点位置
      OUT     M2820  ; 7#在原点位置
284   LDD=    D1120 D2240  ; 7#当前值 / 7#轴位置1
      OUT     M2821  ; 7#在位置1
288   LDD=    D1120 D2242  ; 7#当前值 / 7#轴位置2
      OUT     M2822  ; 7#在位置2
292   LDD=    D1120 D2244  ; 7#当前值 / 7#轴位置3
      OUT     M2823  ; 7#在位置3
296   LDD=    D1120 D2246  ; 7#当前值 / 7#轴位置4
      OUT     M2824  ; 7#在位置4
300   LDD=    D1120 D2248  ; 7#当前值 / 7#轴位置5
      OUT     M2825  ; 7#在位置5
304   LDD=    D1120 D2250  ; 7#当前值 / 7#轴位置6
      OUT     M2826  ; 7#在位置6
308   LDD=    D1120 D2252  ; 7#当前值 / 7#轴位置7
      OUT     M2827  ; 7#在位置7
312   LDD=    D1120 D2254  ; 7#当前值 / 7#轴位置8
      OUT     M2828  ; 7#在位置8
316   LDD=    D1120 D2256  ; 7#当前值 / 7#轴位置9
      OUT     M2829  ; 7#在位置9
320   LDD=    D1120 D2258  ; 7#当前值 / 7#轴位置10
      OUT     M2830  ; 7#在位置10
324   LD      M20  ; 手动状态
      MPS
      LD      M2125  ; 7#JOG+
      OR      M2126  ; 7#JOG-
      ANB
      ANI     X3C  ; 轴1 busy
      SET     M2127  ; 7#JOG
      MRD
      ANI     M2125  ; 7#JOG+
      ANI     M2126  ; 7#JOG-
      RST     M2127  ; 7#JOG
      MRD
      AND     M2125  ; 7#JOG+
      AND     M2127  ; 7#JOG
      ANI     Y39  ; 2#轴1反向JOG
      OUT     Y38  ; 2#轴1正向JOG
      MPP
      AND     M2126  ; 7#JOG-
      AND     M2127  ; 7#JOG
      ANI     Y38  ; 2#轴1正向JOG
      OUT     Y39  ; 2#轴1反向JOG
345   END
END_PROGRAM

PROGRAM 8#模块轴8
0     LD      M20  ; 手动状态
      AND     SM400  ; 始终ON
      MPS
      ANDP    M2142  ; 8#手动折料
      SET     M2150  ; 8#折料
      MRD
      ANDP    M1700  ; 8#轴位置1（手动）
      ANDD<>  D1140 D2280  ; 8#轴当前值 / 8#轴位置1
      SET     M1730  ; 8#轴位置1
      MRD
      ANDP    M1701  ; 8#轴位置2（手动）
      ANDD<>  D1140 D2282  ; 8#轴当前值 / 8#轴位置2
      SET     M1731  ; 8#轴位置2
      MRD
      ANDP    M1702  ; 8#轴位置3（手动）
      ANDD<>  D1140 D2284  ; 8#轴当前值 / 8#轴位置3
      SET     M1732  ; 8#轴位置3
      MRD
      ANDP    M1703  ; 8#轴位置4（手动）
      ANDD<>  D1140 D2286  ; 8#轴当前值 / 8#轴位置4
      SET     M1733  ; 8#轴位置4
      MRD
      ANDP    M1704  ; 8#轴位置5（手动）
      ANDD<>  D1140 D2288  ; 8#轴当前值 / 8#轴位置5
      SET     M1734  ; 8#轴位置5
      MRD
      ANDP    M1705  ; 8#轴位置6（手动）
      ANDD<>  D1140 D2290  ; 8#轴当前值 / 8#轴位置6
      SET     M1735  ; 8#轴位置6
      MRD
      ANDP    M1706  ; 8#轴位置7（手动）
      ANDD<>  D1140 D2292  ; 8#轴当前值 / 8#轴位置7
      SET     M1736  ; 8#轴位置7
      MRD
      ANDP    M1707  ; 8#轴位置8（手动）
      ANDD<>  D1140 D2294  ; 8#轴当前值 / 8#轴位置8
      SET     M1737  ; 8#轴位置8
      MRD
      ANDP    M1708  ; 8#轴位置9（手动）
      ANDD<>  D1140 D2296  ; 8#轴当前值 / 8#轴位置9
      SET     M1738  ; 8#轴位置9
      MPP
      ANDP    M1709  ; 8#轴位置10（手动）
      ANDD<>  D1140 D2298  ; 8#轴当前值 / 8#轴位置10
      SET     M1739  ; 8#轴位置10
65    LDI     M2571  ; 8#轴复原中
      AND     SM400  ; 始终ON
      MPS
      ANDP    M2150  ; 8#折料
      *       D1150 D1148 D1158  ; 8#每转脉冲 / 8#次数 / 8#折料位置
      MRD
      ANDP    M1730  ; 8#轴位置1
      DMOV    D2280 D1550  ; 8#位置
      MRD
      ANDP    M1731  ; 8#轴位置2
      DMOV    D2282 D1550
      MRD
      ANDP    M1732  ; 8#轴位置3
      DMOV    D2284 D1550
      MRD
      ANDP    M1733  ; 8#轴位置4
      DMOV    D2286 D1550
      MRD
      ANDP    M1734  ; 8#轴位置5
      DMOV    D2288 D1550
      MRD
      ANDP    M1735  ; 8#轴位置6
      DMOV    D2290 D1550
      MRD
      ANDP    M1736  ; 8#轴位置7
      DMOV    D2292 D1550
      MRD
      ANDP    M1737  ; 8#轴位置8
      DMOV    D2294 D1550
      MRD
      ANDP    M1738  ; 8#轴位置9
      DMOV    D2296 D1550
      MPP
      ANDP    M1739  ; 8#轴位置10
      DMOV    D2298 D1550
112   LD      SM400  ; 始终ON
      MPS
      AND     M20  ; 手动状态
      DMOV    D1144 D1552  ; 8#手动频率 / 8#速度
      MRD
      ANI     M20  ; 手动状态
      DMOV    D1146 D1552  ; 8#自动速度
      MPP
      DMOV    D1552 U3\G8004
      DMOV    D1142 U3\G8006  ; 8#原点位置
      DMOV    D1552 U3\G8014
      DMOV    D1158 U3\G8016
      DMOV    D1552 U3\G8024
      DMOV    D1550 U3\G8026
146   LDP     T170  ; 8#轴
      LD      M20  ; 手动状态
      ANDP    M2141  ; 8#复原
      ORB
      LD      T170  ; 8#轴
      ANDP    M20  ; 手动状态
      ORF     M20  ; 手动状态
      ANI     M2840  ; 8#在原点位置
      ORB
      ORF     M2140  ; 8#伺服ON
      AND     B57F
      BKRST   B570 K10  ; 8#轴复原开始
      SET     B570  ; 8#轴复原开始
161   LD=     K0 K3B570  ; 8#轴复原开始
      OUT     B57F
      INV
      OUT     M2571  ; 8#轴复原中
167   LD      B570  ; 8#轴复原开始
      SET     B571
      RST     B570  ; 8#轴复原开始
170   LD      B571
      RST     B570  ; 8#轴复原开始
      MOV     K9001 D1542
      MOV     K0 U3\G1621
      ZP.PSTRT2 "U3" D1540 M2155  ; 原点完成
      SET     B572
188   LD      B572
      RST     B571
      AND     M2155  ; 原点完成
      MOV     K1 U3\G1621
      SET     B573
196   LD      B573
      RST     B572
      OUT     T173 K2
      AND     T173
      SET     B574
204   LD      B574
      RST     B573
      PLS     M2154  ; 回原点定位
      ANI     M2154  ; 回原点定位
      SET     B575
210   LD      B575
      RST     B574
      AND     M2157  ; 8#轴定位完成标志
      SET     B576
214   LD      B576
      RST     B575
      DMOV    K0 U3\G1606
      MOV     K9003 U3\G1600
      MPS
      ANDP    B576
      SET     Y41  ; 2#轴2定位启动
      MPP
      RST     B576
230   LD      Y41  ; 2#轴2定位启动
      OUT     T174 K2
      AND     T174
      RST     Y41  ; 2#轴2定位启动
237   LD      M2154  ; 回原点定位
      OR      M2152  ; 8#折料
      OR      M2153  ; 8#INC
      OR      M2150  ; 8#折料
      OR      M2151  ; 8#手动旋转
      OR<>    K0 K3M1730  ; 8#轴位置1
      MPS
      AND     M2154  ; 回原点定位
      MOVP    K1 D1548  ; 8#模式
      MRD
      LD      M2152  ; 8#折料
      OR      M2153  ; 8#INC
      OR      M2150  ; 8#折料
      OR      M2151  ; 8#手动旋转
      ANB
      MOVP    K2 D1548
      MRD
      AND<>   K0 K3M1730  ; 8#轴位置1
      MOVP    K3 D1548
      MRD
      MEP
      ZP.PSTRT2 U3 D1546 M2157  ; 8#轴定位
      MPP
      AND     M2157  ; 8#轴定位完成标志
      BKRST   M1730 K20
      BKRST   M2150 K5
281   LDD=    D1140 D2280  ; 8#轴当前值 / 8#轴位置1
      OUT     M2840  ; 8#在原点位置
285   LDD=    D1140 D2280  ; 8#轴当前值 / 8#轴位置1
      OUT     M2841  ; 8#在位置1
289   LDD=    D1140 D2282  ; 8#轴当前值 / 8#轴位置2
      OUT     M2842  ; 8#在位置2
293   LDD=    D1140 D2284  ; 8#轴当前值 / 8#轴位置3
      OUT     M2843  ; 8#在位置3
297   LDD=    D1140 D2286  ; 8#轴当前值 / 8#轴位置4
      OUT     M2844  ; 8#在位置4
301   LDD=    D1140 D2288  ; 8#轴当前值 / 8#轴位置5
      OUT     M2845  ; 8#在位置5
305   LDD=    D1140 D2290  ; 8#轴当前值 / 8#轴位置6
      OUT     M2846  ; 8#在位置6
309   LDD=    D1140 D2292  ; 8#轴当前值 / 8#轴位置7
      OUT     M2847  ; 8#在位置7
313   LDD=    D1140 D2294  ; 8#轴当前值 / 8#轴位置8
      OUT     M2848  ; 8#在位置8
317   LDD=    D1140 D2296  ; 8#轴当前值 / 8#轴位置9
      OUT     M2849  ; 8#在位置9
321   LDD=    D1140 D2298  ; 8#轴当前值 / 8#轴位置10
      OUT     M2850  ; 8#在位置10
325   LD      M20  ; 手动状态
      MPS
      LD      M2145  ; 8#JOG+
      OR      M2146  ; 8#JOG-
      ANB
      ANI     X3D  ; 轴2 busy
      SET     M2147  ; 8#JOG
      MRD
      ANI     M2145  ; 8#JOG+
      ANI     M2146  ; 8#JOG-
      RST     M2147  ; 8#JOG
      MRD
      AND     M2145  ; 8#JOG+
      AND     M2147  ; 8#JOG
      ANI     Y3B  ; 2#轴2反向JOG
      OUT     Y3A  ; 2#轴2正向JOG
      MPP
      AND     M2146  ; 8#JOG-
      AND     M2147  ; 8#JOG
      ANI     Y3A  ; 2#轴2正向JOG
      OUT     Y3B  ; 2#轴2反向JOG
346   END
END_PROGRAM

PROGRAM 9#模块轴9
0     LD      M20  ; 手动状态
      AND     SM400  ; 始终ON
      MPS
      ANDP    M2162  ; 9#折料（手动）
      SET     M2170  ; 9#轴折料
      MRD
      ANDP    M1800  ; 9#轴位置1（手动）
      ANDD<>  D1160 D2320  ; 9#当前值 / 9#轴位置1
      SET     M1830  ; 9#轴位置1
      MRD
      ANDP    M1801  ; 9#轴位置2（手动）
      ANDD<>  D1160 D2322  ; 9#当前值 / 9#轴位置2
      SET     M1831  ; 9#轴位置2
      MRD
      ANDP    M1802  ; 9#轴位置3（手动）
      ANDD<>  D1160 D2324  ; 9#当前值 / 9#轴位置3
      SET     M1832  ; 9#轴位置3
      MRD
      ANDP    M1803  ; 9#轴位置4（手动）
      ANDD<>  D1160 D2326  ; 9#当前值 / 9#轴位置4
      SET     M1833  ; 9#轴位置4
      MRD
      ANDP    M1804  ; 9#轴位置5（手动）
      ANDD<>  D1160 D2328  ; 9#当前值 / 9#轴位置5
      SET     M1834  ; 9#轴位置5
      MRD
      ANDP    M1805  ; 9#轴位置6（手动）
      ANDD<>  D1160 D2330  ; 9#当前值 / 9#轴位置6
      SET     M1835  ; 9#轴位置6
      MRD
      ANDP    M1806  ; 9#轴位置7（手动）
      ANDD<>  D1160 D2332  ; 9#当前值 / 9#轴位置7
      SET     M1836  ; 9#轴位置7
      MRD
      ANDP    M1807  ; 9#轴位置8（手动）
      ANDD<>  D1160 D2334  ; 9#当前值 / 9#轴位置8
      SET     M1837  ; 9#轴位置8
      MRD
      ANDP    M1808  ; 9#轴位置9（手动）
      ANDD<>  D1160 D2336  ; 9#当前值 / 9#轴位置9
      SET     M1838  ; 9#轴位置9
      MPP
      ANDP    M1809  ; 9#轴位置10（手动）
      ANDD<>  D1160 D2338  ; 9#当前值 / 9#轴位置10
      SET     M1839  ; 9#轴位置10
65    LDI     M2581  ; 9#轴复原中
      AND     SM400  ; 始终ON
      MPS
      ANDP    M2170  ; 9#轴折料
      *       D1170 D1168 D1178  ; 9#每转脉冲 / 9#次数 / 9#折料位置
      MRD
      ANDP    M1830  ; 9#轴位置1
      DMOV    D2320 D1570  ; 9#位置
      MRD
      ANDP    M1831  ; 9#轴位置2
      DMOV    D2322 D1570
      MRD
      ANDP    M1832  ; 9#轴位置3
      DMOV    D2324 D1570
      MRD
      ANDP    M1833  ; 9#轴位置4
      DMOV    D2326 D1570
      MRD
      ANDP    M1834  ; 9#轴位置5
      DMOV    D2328 D1570
      MRD
      ANDP    M1835  ; 9#轴位置6
      DMOV    D2330 D1570
      MRD
      ANDP    M1836  ; 9#轴位置7
      DMOV    D2332 D1570
      MRD
      ANDP    M1837  ; 9#轴位置8
      DMOV    D2334 D1570
      MRD
      ANDP    M1838  ; 9#轴位置9
      DMOV    D2336 D1570
      MPP
      ANDP    M1839  ; 9#轴位置10
      DMOV    D2338 D1570
112   LD      SM400  ; 始终ON
      MPS
      AND     M20  ; 手动状态
      DMOV    D1164 D1572  ; 9#手动频率 / 9#速度
      MRD
      ANI     M20  ; 手动状态
      DMOV    D1166 D1572  ; 9#自动速度
      MPP
      DMOV    D1572 U3\G14004
      DMOV    D1162 U3\G14006  ; 9#原点位置
      DMOV    D1572 U3\G14014
      DMOV    D1178 U3\G14016
      DMOV    D1572 U3\G14024
      DMOV    D1570 U3\G14026
146   LDP     T180  ; 9#轴
      LD      M20  ; 手动状态
      ANDP    M2161  ; 9#复原
      ORB
      LD      T180  ; 9#轴
      ANDP    M20  ; 手动状态
      ORF     M20  ; 手动状态
      AND     M2860  ; 9#在原点位置
      ORB
      ORF     M2160  ; 9#伺服ON
      AND     B58F
      BKRST   B580 K10  ; 9#轴复原开始
      SET     B580  ; 9#轴复原开始
161   LD=     K0 K3B580  ; 9#轴复原开始
      OUT     B58F
      INV
      OUT     M2581  ; 9#轴复原中
167   LD      B580  ; 9#轴复原开始
      SET     B581
      RST     B580  ; 9#轴复原开始
170   LD      B581
      RST     B580  ; 9#轴复原开始
      MOV     K9001 D1562
      MOV     K0 U3\G1721
      ZP.PSTRT3 "U3" D1560 M2175  ; 原点完成
      SET     B582
188   LD      B582
      RST     B581
      AND     M2175  ; 原点完成
      MOV     K1 U3\G1721
      SET     B583
196   LD      B583
      RST     B582
      OUT     T183 K2
      AND     T183
      SET     B584
204   LD      B584
      RST     B583
      PLS     M2174  ; 回原点定位
      ANI     M2174  ; 回原点定位
      SET     B585
210   LD      B585
      RST     B584
      AND     M2177  ; 9+轴定位完成
      SET     B586
214   LD      B586
      RST     B585
      DMOV    K0 U3\G1706
      MOV     K9003 U3\G1700
      MPS
      ANDP    B586
      SET     Y42  ; 2#轴+3定位启动
      MPP
      RST     B586
230   LD      Y42  ; 2#轴+3定位启动
      OUT     T184 K2
      AND     T184
      RST     Y42  ; 2#轴+3定位启动
237   LD      M2174  ; 回原点定位
      OR      M2172  ; 9#折料
      OR      M2173  ; 9#INC
      OR      M2170  ; 9#轴折料
      OR      M2171  ; 9#手动旋转
      OR<>    K0 K4M1830  ; 9#轴位置1
      MPS
      AND     M2174  ; 回原点定位
      MOVP    K1 D1568  ; 9#模式
      MRD
      LD      M2172  ; 9#折料
      OR      M2173  ; 9#INC
      OR      M2170  ; 9#轴折料
      OR      M2171  ; 9#手动旋转
      ANB
      MOVP    K2 D1568
      MRD
      AND<>   K0 K4M1830  ; 9#轴位置1
      MOVP    K3 D1568
      MRD
      MEP
      ZP.PSTRT3 U3 D1566 M2177  ; 9#轴定位
      MPP
      AND     M2177  ; 9+轴定位完成
      BKRST   M1830 K20
      BKRST   M2170 K5
281   LDD=    D1160 D2320  ; 9#当前值 / 9#轴位置1
      OUT     M2860  ; 9#在原点位置
285   LDD=    D1160 D2320  ; 9#当前值 / 9#轴位置1
      OUT     M2861  ; 9#在位置1
289   LDD=    D1160 D2322  ; 9#当前值 / 9#轴位置2
      OUT     M2862  ; 9#在位置2
293   LDD=    D1160 D2324  ; 9#当前值 / 9#轴位置3
      OUT     M2863  ; 9#在位置3
297   LDD=    D1160 D2326  ; 9#当前值 / 9#轴位置4
      OUT     M2864  ; 9#在位置4
301   LDD=    D1160 D2328  ; 9#当前值 / 9#轴位置5
      OUT     M2865  ; 9#在位置5
305   LDD=    D1160 D2330  ; 9#当前值 / 9#轴位置6
      OUT     M2866  ; 9#在位置6
309   LDD=    D1160 D2332  ; 9#当前值 / 9#轴位置7
      OUT     M2867  ; 9#在位置7
313   LDD=    D1160 D2334  ; 9#当前值 / 9#轴位置8
      OUT     M2868  ; 9#在位置8
317   LDD=    D1160 D2336  ; 9#当前值 / 9#轴位置9
      OUT     M2869  ; 9#在位置9
321   LDD=    D1160 D2338  ; 9#当前值 / 9#轴位置10
      OUT     M2870  ; 9#在位置10
325   LD      M20  ; 手动状态
      MPS
      LD      M2165  ; 9#轴JOG+
      OR      M2166  ; 9#轴JOG-
      ANB
      ANI     X3E  ; 轴3 busy
      SET     M2167  ; 9#轴JOG
      MRD
      ANI     M2165  ; 9#轴JOG+
      ANI     M2166  ; 9#轴JOG-
      RST     M2167  ; 9#轴JOG
      MRD
      AND     M2165  ; 9#轴JOG+
      AND     M2167  ; 9#轴JOG
      ANI     Y3D  ; 2#轴3反向JOG
      OUT     Y3C  ; 2#轴3正向JOG
      MPP
      AND     M2166  ; 9#轴JOG-
      AND     M2167  ; 9#轴JOG
      ANI     Y3C  ; 2#轴3正向JOG
      OUT     Y3D  ; 2#轴3反向JOG
346   END
END_PROGRAM

PROGRAM 初始化
0     LD      X100
      OUT     M600  ; 气缸1-0
2     LD      X101
      OUT     M800  ; 气缸1-1
4     LD      X102
      OUT     M601  ; 气缸2-0
6     LD      X103
      OUT     M801  ; 气缸2-1
8     LD      X104
      OUT     M602  ; 气缸3-0
10    LD      X105
      OUT     M802  ; 气缸3-1
12    LD      X106
      OUT     M603  ; 气缸4-0
14    LD      X107
      OUT     M803  ; 气缸4-1
16    LD      X108
      OUT     M604  ; 气缸5-0
18    LD      X109
      OUT     M804  ; 气缸5-1
20    LD      X10A
      OUT     M605  ; 气缸6-0
22    LD      X10B
      OUT     M805  ; 气缸6-1
24    LD      X10C
      OUT     M606  ; 气缸7-0
26    LD      X10D
      OUT     M806  ; 气缸7-1
28    LD      X10E
      OUT     M607  ; 气缸8-0
30    LD      X10F
      OUT     M807  ; 气缸8-1
32    LD      X110
      OUT     M608  ; 气缸9-0
34    LD      X111
      OUT     M808  ; 气缸9-1
36    LD      X112
      OUT     M609  ; 气缸10-0
38    LD      X113
      OUT     M809  ; 气缸10-1
40    LD      X114
      OUT     M610  ; 气缸11-0
42    LD      X115
      OUT     M810  ; 气缸11-1
44    LD      X116
      OUT     M611  ; 气缸12-0
46    LD      X117
      OUT     M811  ; 气缸12-1
48    LD      X118
      OUT     M612  ; 气缸13-0
50    LD      X119
      OUT     M812  ; 气缸13-1
52    LD      X11A
      OUT     M613  ; 气缸14-0
54    LD      X11B
      OUT     M813  ; 气缸14-1
56    LD      X11C
      OUT     M614  ; 气缸15-0
58    LD      X11D
      OUT     M814  ; 气缸15-1
60    LD      X11E
      OUT     M615  ; 气缸16-0
62    LD      X11F
      OUT     M815  ; 气缸16-1
64    LD      X120
      OUT     M616  ; 气缸17-0
66    LD      X121
      OUT     M816  ; 气缸17-1
68    LD      X122
      OUT     M617  ; 气缸18-0
70    LD      X123
      OUT     M817  ; 气缸18-1
72    LD      X124
      OUT     M618  ; 气缸19-0
74    LD      X125
      OUT     M818  ; 气缸19-1
76    LD      X126
      OUT     M619  ; 气缸20-0
78    LD      X127
      OUT     M819  ; 气缸20-1
80    LD      X128
      OUT     M620  ; 气缸21-0
82    LD      X129
      OUT     M621  ; 气缸22-0
84    LD      X12A
      OUT     M622  ; 气缸23-0
86    LD      X12B
      OUT     M623  ; 气缸24-0
88    LD      X12C
      OUT     M624  ; 气缸25-0
90    LD      X12D
      OUT     M625  ; 气缸26-0
92    LD      X12E
      OUT     M626  ; 气缸27-0
94    LD      X12F
      OUT     M627  ; 气缸28-0
96    LD      X130
      OUT     M628  ; 气缸29-0
; 按钮转换
104   LD      X131
      OUT     M15  ; 启动（外部按钮）
106   LD      X132
      OUT     M16  ; 停止（外部按钮）
108   LD      X133
      OUT     M17  ; 急停（外部按钮）
; 屏蔽开关
116   LDP     L350
      FF      L550
119   LDP     L351
      FF      L551
122   LDP     L352
      FF      L552
125   LDP     L353
      FF      L553
128   LDP     L354
      FF      L554
131   LDP     L355
      FF      L555
134   LDP     L356
      FF      L556
137   LDP     L357
      FF      L557
140   LDP     L358
      FF      L558
143   LDP     L359
      FF      L559
146   LDP     L360
      FF      L560
149   LDP     L361
      FF      L561
152   LDP     L362
      FF      L562
155   LDP     L363
      FF      L563
158   LDP     L364
      FF      L564
161   LDP     L365
      FF      L565
164   LDP     L366
      FF      L566
167   LDP     L367
      FF      L567
170   LDP     L368
      FF      L568
173   LDP     L369
      FF      L569
176   LDP     L370
      FF      L570
179   LDP     L371
      FF      L571
182   LDP     L372
      FF      L572
185   LDP     L373
      FF      L573
188   LDP     L374
      FF      L574
191   LDP     L375
      FF      L575
194   LDP     L376
      FF      L576
197   LDP     L377
      FF      L577
200   LDP     L378
      FF      L578
203   LDP     L379
      FF      L579
206   LD      SM402
      BKRST   B10 K2000
      SET     B10
211   LD      B10
      ORI     M17  ; 急停（外部按钮）
      MPS
      LDP     B10
      ORI     M17  ; 急停（外部按钮）
      ANB
      SET     B20  ; 初始化1
      SET     B30  ; 初始化2
      SET     B40  ; 初始化3
      SET     B50  ; 初始化4
      SET     B60  ; 初始化5
      SET     B70  ; 初始化6
      MPP
      ANI     B20  ; 初始化1
      ANI     B21
      ANI     B30  ; 初始化2
      ANI     B31
      ANI     B40  ; 初始化3
      ANI     B41
      ANI     B50  ; 初始化4
      ANI     B51
      ANI     B60  ; 初始化5
      ANI     B61
      ANI     B70  ; 初始化6
      ANI     B71
      RST     B10
; 工位2复位
244   LD      B20  ; 初始化1
      BKRST   B200 K550  ; 升载座工位启动
      RST     B20  ; 初始化1
249   LD      B30  ; 初始化2
      RST     B30  ; 初始化2
; 工位4复位
258   LD      B40  ; 初始化3
      RST     B40  ; 初始化3
260   LD      B50  ; 初始化4
      RST     B50  ; 初始化4
262   LD      M10  ; 手动
      ANI     M11  ; 单动
      ANI     M12  ; 自动
      OR      SM402
      ORI     M17  ; 急停（外部按钮）
      SET     M20  ; 手动状态
      RST     M21  ; 单动状态
      RST     M22  ; 自动状态
270   LD      M11  ; 单动
      ANI     M10  ; 手动
      ANI     M12  ; 自动
      SET     M21  ; 单动状态
      RST     M20  ; 手动状态
      RST     M22  ; 自动状态
276   LD      M12  ; 自动
      ANI     M10  ; 手动
      ANI     M11  ; 单动
      SET     M22  ; 自动状态
      RST     M20  ; 手动状态
      RST     M21  ; 单动状态
282   LDP     M13  ; 启动(触摸屏)
      ORP     M15  ; 启动（外部按钮）
      LD      M21  ; 单动状态
      OR      M22  ; 自动状态
      ANB
      ANI     M20  ; 手动状态
      SET     M23  ; 启动
      SET     M25  ; 启动2
      RST     M24  ; 停止
291   LDP     M13  ; 启动(触摸屏)
      ORP     M15  ; 启动（外部按钮）
      MPS
      LD      M21  ; 单动状态
      OR      M22  ; 自动状态
      ANB
      ANI     M20  ; 手动状态
      SET     M23  ; 启动
      SET     M25  ; 启动2
      SET     M26  ; 启动3
      RST     M24  ; 停止
      MPP
      SET     M27  ; 入料马达启停
304   LDI     M0  ; 报警
      ANI     M20  ; 手动状态
      MPS
      AND=    K1M4 K0  ; 单动脉冲
      ANI     M14  ; 停止(触摸屏)
      ANI     M20  ; 手动状态
      ANI     M16  ; 停止（外部按钮）
      AND     M17  ; 急停（外部按钮）
      INV
      RST     M23  ; 启动
      SET     M24  ; 停止
      MRD
      INV
      RST     M25  ; 启动2
      MPP
      INV
      RST     M26  ; 启动3
323   LDI     M14  ; 停止(触摸屏)
      ANI     M16  ; 停止（外部按钮）
      AND     M17  ; 急停（外部按钮）
      INV
      RST     M27  ; 入料马达启停
328   END
END_PROGRAM

PROGRAM 手动
0     LD      M20  ; 手动状态
      AND     M17  ; 急停（外部按钮）
      ANI     M9  ; 总气阀开关（ON为关）
      MC      N0 M18
5     LDP     M18
      SET     B10
7     LDP     M3000  ; 气缸1（手动）
      FF      M4000  ; 气缸1（输出）
10    LDP     M3001  ; 气缸2（手动）
      FF      M4001  ; 气缸2（输出）
13    LDP     M3002  ; 气缸3（手动）
      FF      M4002  ; 气缸3（输出）
16    LDP     M3003  ; 气缸4（手动）
      FF      M4003  ; 气缸4（输出）
19    LDP     M3004  ; 气缸5（手动）
      FF      M4004  ; 气缸5（输出）
22    LDP     M3005  ; 气缸6（手动）
      FF      M4005  ; 气缸6（输出）
25    LDP     M3006  ; 气缸7（手动）
      FF      M4006  ; 气缸7（输出）
28    LDP     M3007  ; 气缸8（手动）
      FF      M4007  ; 气缸8（输出）
31    LDP     M3008  ; 气缸9（手动）
      FF      M4008  ; 气缸9（输出）
34    LDP     M3009  ; 气缸10（手动）
      FF      M4009  ; 气缸10（输出）
37    LDP     M3010  ; 气缸11（手动）
      FF      M4010  ; 气缸11（输出）
40    LDP     M3011  ; 气缸12（手动）
      FF      M4011  ; 气缸12（输出）
43    LDP     M3012  ; 气缸13（手动）
      FF      M4012  ; 气缸13（输出）
46    LDP     M3015  ; 气缸16（手动）
      FF      M4015  ; 气缸16（输出）
49    LDP     M3016  ; 气缸17（手动）
      FF      M4016  ; 气缸17（输出）
52    LDP     M3017  ; 气缸18（手动）
      FF      M4017  ; 气缸18（输出）
55    LDP     M3018  ; 气缸19（手动）
      FF      M4018  ; 气缸19（输出）
58    LDP     M3019  ; 气缸20（手动）
      FF      M4019  ; 气缸20（输出）
61    LDP     M3020  ; 气缸21（手动）
      FF      M4020  ; 气缸21（输出）
64    LDP     M3021  ; 气缸22（手动）
      FF      M4021  ; 气缸22（输出）
67    LDP     M3022  ; 气缸23（手动）
      FF      M4022  ; 气缸23（输出）
70    LDP     M3023  ; 气缸24（手动）
      FF      M4023  ; 气缸24（输出）
73    LDP     M3024  ; 气缸25（手动）
      FF      M4024  ; 气缸25（输出）
76    LDP     M3025  ; 气缸26（手动）
      FF      M4025  ; 气缸26（输出）
79    LDP     M3028  ; 气缸29（手动）
      FF      M4028  ; 气缸29（输出）
82    LDP     M3029  ; 气缸30（手动）
      FF      M4029  ; 气缸30（输出）
85    LDP     M3030  ; 气缸31（手动）
      FF      M4030  ; 气缸31（输出）
88    LDP     M3031  ; 气缸32（手动）
      FF      M4031  ; 气缸32（输出）
91    LDP     M3032  ; 气缸33（手动）
      FF      M4032  ; 气缸33（输出）
94    LDP     M3033  ; 气缸34（手动）
      FF      M4033  ; 气缸34（输出）
97    LDP     M3034  ; 气缸35（手动）
      FF      M4034  ; 气缸35（输出）
100   LDP     M3035  ; 气缸36（手动）
      FF      M4035  ; 气缸36（输出）
103   LDP     M3036  ; 气缸37（手动）
      FF      M4036  ; 气缸37（输出）
106   LDP     M3037  ; 气缸38（手动）
      FF      M4037  ; 气缸38（输出）
109   LDP     M3038  ; 气缸39（手动）
      FF      M4038  ; 气缸39（输出）
112   LDP     M3039  ; 气缸40（手动）
      FF      M4039  ; 气缸40（输出）
115   LDP     M3040  ; 气缸41（手动）
      FF      M4040  ; 气缸41（输出）
118   LDP     M3041  ; 气缸42（手动）
      FF      M4041  ; 气缸42（输出）
121   LDP     M3042  ; 气缸43（手动）
      FF      M4042  ; 气缸43（输出）
124   LDP     M3043  ; 气缸44（手动）
      FF      M4043  ; 气缸44（输出）
127   MCR     N0
128   END
END_PROGRAM

PROGRAM 报警
0     LDI     M4000  ; 气缸1（输出）
      AND     M600  ; 气缸1-0
      ANI     M800  ; 气缸1-1
      LD      M4000  ; 气缸1（输出）
      ANI     M600  ; 气缸1-0
      AND     M800  ; 气缸1-1
      ORB
      INV
      OUT     T1000 K20
      AND     T1000
      SET     M5000  ; 气缸1异常！
14    LDI     M4001  ; 气缸2（输出）
      AND     M601  ; 气缸2-0
      ANI     M801  ; 气缸2-1
      LD      M4001  ; 气缸2（输出）
      ANI     M601  ; 气缸2-0
      AND     M801  ; 气缸2-1
      ORB
      INV
      OUT     T1001 K20
      AND     T1001
      SET     M5001  ; 气缸2异常！
28    LDI     M4002  ; 气缸3（输出）
      AND     M602  ; 气缸3-0
      ANI     M802  ; 气缸3-1
      LD      M4002  ; 气缸3（输出）
      ANI     M602  ; 气缸3-0
      AND     M802  ; 气缸3-1
      ORB
      INV
      OUT     T1002 K30
      AND     T1002
      SET     M5002  ; 气缸3异常！
42    LDI     M4003  ; 气缸4（输出）
      AND     M603  ; 气缸4-0
      ANI     M803  ; 气缸4-1
      LD      M4003  ; 气缸4（输出）
      ANI     M603  ; 气缸4-0
      AND     M803  ; 气缸4-1
      ORB
      INV
      OUT     T1003 K20
      AND     T1003
      SET     M5003  ; 气缸4异常！
56    LDI     M4004  ; 气缸5（输出）
      AND     M604  ; 气缸5-0
      ANI     M804  ; 气缸5-1
      LD      M4004  ; 气缸5（输出）
      ANI     M604  ; 气缸5-0
      AND     M804  ; 气缸5-1
      ORB
      INV
      OUT     T1004 K20
      AND     T1004
      SET     M5004  ; 气缸5异常！
70    LDI     M4005  ; 气缸6（输出）
      AND     M605  ; 气缸6-0
      ANI     M805  ; 气缸6-1
      LD      M4005  ; 气缸6（输出）
      ANI     M605  ; 气缸6-0
      AND     M805  ; 气缸6-1
      ORB
      INV
      OUT     T1005 K20
      AND     T1005
      SET     M5005  ; 气缸6异常！
84    LDI     M4006  ; 气缸7（输出）
      AND     M606  ; 气缸7-0
      ANI     M806  ; 气缸7-1
      LD      M4006  ; 气缸7（输出）
      ANI     M606  ; 气缸7-0
      AND     M806  ; 气缸7-1
      ORB
      INV
      OUT     T1006 K20
      AND     T1006
      SET     M5006  ; 气缸7异常！
98    LDI     M4007  ; 气缸8（输出）
      AND     M607  ; 气缸8-0
      ANI     M807  ; 气缸8-1
      LD      M4007  ; 气缸8（输出）
      ANI     M607  ; 气缸8-0
      AND     M807  ; 气缸8-1
      ORB
      INV
      OUT     T1007 K20
      AND     T1007
      SET     M5007  ; 气缸8异常！
112   LDI     M4008  ; 气缸9（输出）
      AND     M608  ; 气缸9-0
      ANI     M808  ; 气缸9-1
      LD      M4008  ; 气缸9（输出）
      ANI     M608  ; 气缸9-0
      AND     M808  ; 气缸9-1
      ORB
      INV
      OUT     T1008 K20
      AND     T1008
      SET     M5008  ; 气缸9异常！
126   LDI     M4009  ; 气缸10（输出）
      AND     M609  ; 气缸10-0
      ANI     M809  ; 气缸10-1
      LD      M4009  ; 气缸10（输出）
      ANI     M609  ; 气缸10-0
      AND     M809  ; 气缸10-1
      ORB
      INV
      OUT     T1009 K20
      AND     T1009
      SET     M5009  ; 气缸10异常！
140   LDI     M4010  ; 气缸11（输出）
      AND     M610  ; 气缸11-0
      ANI     M810  ; 气缸11-1
      LD      M4010  ; 气缸11（输出）
      ANI     M610  ; 气缸11-0
      AND     M810  ; 气缸11-1
      ORB
      INV
      OUT     T1010 K20
      AND     T1010
      SET     M5010  ; 气缸11异常！
154   LDI     M4011  ; 气缸12（输出）
      AND     M611  ; 气缸12-0
      ANI     M811  ; 气缸12-1
      LD      M4011  ; 气缸12（输出）
      ANI     M611  ; 气缸12-0
      AND     M811  ; 气缸12-1
      ORB
      INV
      OUT     T1011 K20
      AND     T1011
      SET     M5011  ; 气缸12异常！
168   LDI     M4012  ; 气缸13（输出）
      AND     M612  ; 气缸13-0
      ANI     M812  ; 气缸13-1
      LD      M4012  ; 气缸13（输出）
      ANI     M612  ; 气缸13-0
      AND     M812  ; 气缸13-1
      ORB
      INV
      OUT     T1012 K20
      AND     T1012
      SET     M5012  ; 气缸13异常！
182   LDI     M4013  ; 气缸14（输出）
      AND     M613  ; 气缸14-0
      ANI     M813  ; 气缸14-1
      LD      M4013  ; 气缸14（输出）
      ANI     M613  ; 气缸14-0
      AND     M813  ; 气缸14-1
      ORB
      INV
      OUT     T1013 K20
      AND     T1013
      SET     M5013  ; 气缸14异常！
196   LDI     M4014  ; 气缸15（输出）
      AND     M614  ; 气缸15-0
      ANI     M814  ; 气缸15-1
      LD      M4014  ; 气缸15（输出）
      ANI     M614  ; 气缸15-0
      AND     M814  ; 气缸15-1
      ORB
      INV
      OUT     T1014 K20
      AND     T1014
      SET     M5014  ; 气缸15异常！
210   LDI     M4015  ; 气缸16（输出）
      ANI     M615  ; 气缸16-0
      LD      M2781  ; 5#在位置1
      AND     M4015  ; 气缸16（输出）
      ANI     M815  ; 气缸16-1
      ORB
      LD      M2782  ; 5#在位置2
      AND     M4015  ; 气缸16（输出）
      ANI     X136
      ORB
      OUT     T1015 K20
      AND     T1015
      SET     M5015  ; 气缸16异常！
226   LDI     M4016  ; 气缸17（输出）
      AND     M616  ; 气缸17-0
      ANI     M816  ; 气缸17-1
      LD      M4041  ; 气缸42（输出）
      ANI     M641  ; 气缸42-0
      AND     M841  ; 气缸42-1
      ORB
      INV
      OUT     T1016 K20
      AND     T1016
      SET     M5016  ; 气缸17异常！
240   LDI     M4017  ; 气缸18（输出）
      AND     M617  ; 气缸18-0
      ANI     M817  ; 气缸18-1
      LD      M4017  ; 气缸18（输出）
      ANI     M617  ; 气缸18-0
      AND     M817  ; 气缸18-1
      ORB
      INV
      OUT     T1017 K20
      AND     T1017
      SET     M5017  ; 气缸18异常！
254   LDI     M4018  ; 气缸19（输出）
      AND     M618  ; 气缸19-0
      ANI     M818  ; 气缸19-1
      LD      M4018  ; 气缸19（输出）
      ANI     M618  ; 气缸19-0
      AND     M818  ; 气缸19-1
      ORB
      INV
      OUT     T1018 K20
      AND     T1018
      SET     M5018  ; 气缸19异常！
268   LDI     M4019  ; 气缸20（输出）
      AND     M619  ; 气缸20-0
      ANI     M819  ; 气缸20-1
      LD      M4019  ; 气缸20（输出）
      ANI     M619  ; 气缸20-0
      AND     M819  ; 气缸20-1
      ORB
      INV
      OUT     T1019 K20
      AND     T1019
      SET     M5019  ; 气缸20异常！
282   LDI     M4020  ; 气缸21（输出）
      AND     M630  ; 气缸31-0
      ANI     M830  ; 气缸31-1
      LD      M4020  ; 气缸21（输出）
      ANI     M630  ; 气缸31-0
      AND     M830  ; 气缸31-1
      ORB
      INV
      OUT     T1020 K20
      AND     T1020
      SET     M5020  ; 气缸21异常！
296   LDI     M4021  ; 气缸22（输出）
      AND     M631  ; 气缸32-0
      ANI     M831  ; 气缸32-1
      LD      M4021  ; 气缸22（输出）
      ANI     M631  ; 气缸32-0
      AND     M831  ; 气缸32-1
      ORB
      INV
      OUT     T1021 K20
      AND     T1021
      SET     M5021  ; 气缸22异常！
310   LDI     M4022  ; 气缸23（输出）
      AND     M632  ; 气缸33-0
      ANI     M832  ; 气缸33-1
      LD      M4022  ; 气缸23（输出）
      ANI     M632  ; 气缸33-0
      AND     M832  ; 气缸33-1
      ORB
      INV
      OUT     T1022 K20
      AND     T1022
      SET     M5022  ; 气缸23异常！
324   LDI     M4023  ; 气缸24（输出）
      AND     M633  ; 气缸34-0
      ANI     M833  ; 气缸34-1
      LD      M4023  ; 气缸24（输出）
      ANI     M633  ; 气缸34-0
      AND     M833  ; 气缸34-1
      ORB
      INV
      OUT     T1023 K20
      AND     T1023
      SET     M5023  ; 气缸24异常！
338   LDI     M4024  ; 气缸25（输出）
      AND     M634  ; 气缸35-0
      ANI     M834  ; 气缸35-1
      LD      M4024  ; 气缸25（输出）
      ANI     M634  ; 气缸35-0
      AND     M834  ; 气缸35-1
      ORB
      INV
      OUT     T1024 K20
      AND     T1024
      SET     M5024  ; 气缸25异常！
352   LDI     M4025  ; 气缸26（输出）
      AND     M635  ; 气缸36-0
      ANI     M835  ; 气缸36-1
      LD      M4025  ; 气缸26（输出）
      ANI     M635  ; 气缸36-0
      AND     M835  ; 气缸36-1
      ORB
      INV
      OUT     T1025 K20
      AND     T1025
      SET     M5025  ; 气缸26异常！
366   LDI     M4026  ; 气缸27（输出）
      AND     M636  ; 气缸37-0
      ANI     M836  ; 气缸37-1
      LD      M4026  ; 气缸27（输出）
      ANI     M636  ; 气缸37-0
      AND     M836  ; 气缸37-1
      ORB
      INV
      OUT     T1026 K20
      AND     T1026
      SET     M5026  ; 气缸27异常！
380   LDI     M4027  ; 气缸28（输出）
      AND     M637  ; 气缸38-0
      ANI     M837  ; 气缸38-1
      LD      M4027  ; 气缸28（输出）
      ANI     M637  ; 气缸38-0
      AND     M837  ; 气缸38-1
      ORB
      INV
      OUT     T1027 K20
      AND     T1027
      SET     M5027  ; 气缸28异常！
394   LDI     M4028  ; 气缸29（输出）
      AND     M638  ; 气缸39-0
      ANI     M838  ; 气缸39-1
      LD      M4028  ; 气缸29（输出）
      ANI     M638  ; 气缸39-0
      AND     M838  ; 气缸39-1
      ORB
      INV
      OUT     T1028 K20
      AND     T1028
      SET     M5028  ; 气缸29异常！
408   LDI     M4029  ; 气缸30（输出）
      AND     M639  ; 气缸40-0
      ANI     M839  ; 气缸40-1
      LD      M4029  ; 气缸30（输出）
      ANI     M639  ; 气缸40-0
      AND     M839  ; 气缸40-1
      ORB
      INV
      OUT     T1029 K20
      AND     T1029
      SET     M5029  ; 气缸30异常！
422   LDI     M4030  ; 气缸31（输出）
      AND     M640  ; 气缸41-0
      ANI     M840  ; 气缸41-1
      LD      M4030  ; 气缸31（输出）
      ANI     M640  ; 气缸41-0
      AND     M840  ; 气缸41-1
      ORB
      INV
      OUT     T1030 K20
      AND     T1030
      SET     M5030  ; 气缸31异常！
436   LDI     M4031  ; 气缸32（输出）
      AND     M641  ; 气缸42-0
      ANI     M841  ; 气缸42-1
      LD      M4031  ; 气缸32（输出）
      ANI     M641  ; 气缸42-0
      AND     M841  ; 气缸42-1
      ORB
      INV
      OUT     T1031 K20
      AND     T1031
      SET     M5031  ; 气缸32异常！
450   LDI     M4032  ; 气缸33（输出）
      AND     M642  ; 气缸43-0
      ANI     M842  ; 气缸43-1
      LD      M4032  ; 气缸33（输出）
      ANI     M642  ; 气缸43-0
      AND     M842  ; 气缸43-1
      ORB
      INV
      MPS
      ANI     SM400  ; 始终ON
      OUT     T1032 K20
      MPP
      AND     T1032
      SET     M5032  ; 气缸33异常！
467   LDI     M4033  ; 气缸34（输出）
      AND     M643  ; 气缸44-0
      ANI     M843  ; 气缸44-1
      LD      M4033  ; 气缸34（输出）
      ANI     M643  ; 气缸44-0
      AND     M843  ; 气缸44-1
      ORB
      INV
      OUT     T1033 K20
      AND     T1033
      SET     M5033  ; 气缸34异常！
481   LDI     M4034  ; 气缸35（输出）
      AND     M644  ; 气缸45-0
      ANI     M844  ; 气缸45-1
      LD      M4034  ; 气缸35（输出）
      ANI     M644  ; 气缸45-0
      AND     M844  ; 气缸45-1
      ORB
      INV
      OUT     T1034 K20
      AND     T1034
      SET     M5034  ; 气缸35异常！
495   LDI     M4035  ; 气缸36（输出）
      AND     M645  ; 气缸46-0
      ANI     M845  ; 气缸46-1
      LD      M4035  ; 气缸36（输出）
      ANI     M645  ; 气缸46-0
      AND     M845  ; 气缸46-1
      ORB
      INV
      OUT     T1035 K20
      AND     T1035
      SET     M5035  ; 气缸36异常！
509   LDI     M4036  ; 气缸37（输出）
      AND     M646  ; 气缸47-0
      ANI     M846  ; 气缸47-1
      LD      M4036  ; 气缸37（输出）
      ANI     M646  ; 气缸47-0
      AND     M846  ; 气缸47-1
      ORB
      INV
      OUT     T1036 K20
      AND     T1036
      SET     M5036  ; 气缸37异常！
523   LDI     M4037  ; 气缸38（输出）
      AND     M647  ; 气缸48-0
      ANI     M847  ; 气缸48-1
      LD      M4037  ; 气缸38（输出）
      ANI     M647  ; 气缸48-0
      AND     M847  ; 气缸48-1
      ORB
      INV
      OUT     T1037 K20
      AND     T1037
      SET     M5037  ; 气缸38异常！
537   LDI     M4038  ; 气缸39（输出）
      AND     M648  ; 气缸49-0
      ANI     M848  ; 气缸49-1
      LD      M4038  ; 气缸39（输出）
      ANI     M648  ; 气缸49-0
      AND     M848  ; 气缸49-1
      ORB
      INV
      OUT     T1038 K20
      AND     T1038
      SET     M5038  ; 气缸39异常！
551   LDI     M4039  ; 气缸40（输出）
      AND     M649  ; 气缸50-0
      ANI     M849
      LD      M4039  ; 气缸40（输出）
      ANI     M649  ; 气缸50-0
      AND     M849
      ORB
      INV
      OUT     T1039 K20
      AND     T1039
      SET     M5039  ; 气缸40异常！
565   LDI     M4040  ; 气缸41（输出）
      AND     M640  ; 气缸41-0
      ANI     M840  ; 气缸41-1
      LD      M4040  ; 气缸41（输出）
      ANI     M640  ; 气缸41-0
      AND     M840  ; 气缸41-1
      ORB
      INV
      OUT     T1040 K20
      AND     T1040
      SET     M5040  ; 气缸41异常！
579   LDI     M4041  ; 气缸42（输出）
      AND     M641  ; 气缸42-0
      ANI     M841  ; 气缸42-1
      LD      M4041  ; 气缸42（输出）
      ANI     M641  ; 气缸42-0
      AND     M841  ; 气缸42-1
      ORB
      INV
      OUT     T1041 K20
      AND     T1041
      SET     M5041  ; 气缸42异常！
593   LDI     M4042  ; 气缸43（输出）
      AND     M642  ; 气缸43-0
      ANI     M842  ; 气缸43-1
      LD      M4042  ; 气缸43（输出）
      ANI     M642  ; 气缸43-0
      AND     M842  ; 气缸43-1
      ORB
      INV
      OUT     T1042 K20
      AND     T1042
      SET     M5042  ; 气缸43异常！
607   LDI     M4043  ; 气缸44（输出）
      AND     M643  ; 气缸44-0
      ANI     M843  ; 气缸44-1
      LD      M4043  ; 气缸44（输出）
      ANI     M643  ; 气缸44-0
      AND     M843  ; 气缸44-1
      ORB
      INV
      OUT     T1043 K20
      AND     T1043
      SET     M5043  ; 气缸44异常！
621   LD      SM400  ; 始终ON
      MPS
      AND>=   D970 D980  ; 不良盒1计数 / 不良盒1设置
      SET     M5100  ; 1#不良品盒满！
      MOV     K0 D970
      MRD
      AND>=   D972 D982  ; 不良盒2计数 / 不良盒2设置
      SET     M5101  ; 2#不良品盒满！
      MOV     K0 D972
      MRD
      AND>=   D974 D984  ; 不良盒3计数 / 不良盒3设置
      SET     M5102  ; 3#不良品盒满！
      MOV     K0 D974
      MRD
      AND>=   D976 D986  ; 不良盒4计数 / 不良盒4设置
      SET     M5103  ; 4#不良品盒满！
      MOV     K0 D976
      MPP
      AND>=   D978 D988  ; 不良盒5计数 / 不良盒5设置
      SET     M5104  ; 5#不良品盒满！
      MOV     K0 D978
657   LDD<>   K0 K8M5000  ; 气缸1异常！
      ORD<>   K0 K8M5030  ; 气缸31异常！
      ORD<>   K0 K8M5060
      ORD<>   K0 K8M5090
      ORD<>   K0 K8M5100  ; 1#不良品盒满！
      ORD<>   K0 K8M5130  ; 1#马达驱动器报警！
      ORD<>   K0 K8M5160  ; 11#马达未激磁！
      ORD<>   K0 K8M5190  ; 易损件11保养周期到！
      OR<>    K0 K1M5250
      OUT     M0  ; 报警
693   LD      M16  ; 停止（外部按钮）
      OUT     T197 K5
698   LD      M1  ; 报警清除
      OR      T197
      BKRST   M5000 K300
703   LD      B10
      OUT     M5176  ; 程序初始化中...
705   LD      SM52
      OUT     M5330  ; PLC电池压力低
707   END
END_PROGRAM

PROGRAM 输出
VAR
  KD910 : DINT;
END_VAR
0     LD      M4000  ; 气缸1（输出）
      OUT     Y200
2     LD      M4001  ; 气缸2（输出）
      OUT     Y201
4     LD      M4002  ; 气缸3（输出）
      OUT     Y202
6     LD      M4003  ; 气缸4（输出）
      OUT     Y203
8     LD      M4004  ; 气缸5（输出）
      OUT     Y204
10    LD      M4005  ; 气缸6（输出）
      OUT     Y205
12    LD      M4006  ; 气缸7（输出）
      OUT     Y206
14    LD      M4007  ; 气缸8（输出）
      OUT     Y207
16    LD      M4008  ; 气缸9（输出）
      OUT     Y208
18    LD      M4009  ; 气缸10（输出）
      OUT     Y209
20    LD      M4010  ; 气缸11（输出）
      OUT     Y20A
22    LD      M4011  ; 气缸12（输出）
      OUT     Y20B
24    LD      M4012  ; 气缸13（输出）
      OUT     Y20C
26    LD      M4013  ; 气缸14（输出）
      OUT     Y20D
28    LD      M4014  ; 气缸15（输出）
      OUT     Y20E
30    LD      M4015  ; 气缸16（输出）
      OUT     Y20F
32    LD      M4016  ; 气缸17（输出）
      OUT     Y210
34    LD      M4017  ; 气缸18（输出）
      OUT     Y211
36    LD      M4018  ; 气缸19（输出）
      OUT     Y212
38    LD      M4019  ; 气缸20（输出）
      OUT     Y213
40    LD      M4020  ; 气缸21（输出）
      OUT     Y21B
42    LD      M4021  ; 气缸22（输出）
      OUT     Y21C
44    LD      M4022  ; 气缸23（输出）
      OUT     Y222
46    LD      M4023  ; 气缸24（输出）
      OUT     Y223
48    LD      M4024  ; 气缸25（输出）
      OUT     Y224
50    LD      M4025  ; 气缸26（输出）
      OUT     Y225
52    LD      M4026  ; 气缸27（输出）
      OUT     Y226
54    LD      M4027  ; 气缸28（输出）
      OUT     Y227
56    LD      M4028  ; 气缸29（输出）
      OUT     Y228
58    LD      M4029  ; 气缸30（输出）
      OUT     Y229
60    LD      M4030  ; 气缸31（输出）
      OUT     Y22A
62    LD      M4031  ; 气缸32（输出）
      OUT     Y22B
64    LD      M4032  ; 气缸33（输出）
      OUT     Y22C
66    LD      M4033  ; 气缸34（输出）
      OUT     Y22D
68    LD      M4034  ; 气缸35（输出）
      OUT     Y22E
70    LD      M4035  ; 气缸36（输出）
      OUT     Y22F
72    LD      M4036  ; 气缸37（输出）
      OUT     Y230
74    LD      M4037  ; 气缸38（输出）
      OUT     Y231
76    LD      M4038  ; 气缸39（输出）
      OUT     Y232
78    LD      M4039  ; 气缸40（输出）
      OUT     Y233
80    LD      M4040  ; 气缸41（输出）
      OUT     Y234
82    LD      M4041  ; 气缸42（输出）
      OUT     Y235
84    LD      M4042  ; 气缸43（输出）
      OUT     Y21A
86    LD      M4043  ; 气缸44（输出）
      OUT     Y236
88    LD      SM400  ; 始终ON
      MPS
      AND     M2
      MOV     T0 D1334  ; M/CT
      MPP
      AND     M23  ; 启动
      ANI     M2
      OUTH    T0 K9999
100   LD      SM400  ; 始终ON
      AND     M2
      DINCP   D1300  ; 总产能
      DINCP   D1310  ; 当前产能
      DINCP   D11000  ; 当天产能
108   LD      M0  ; 报警
      OUT     M30  ; 红灯
110   LDI     M23  ; 启动
      ANI     M0  ; 报警
      OUT     M31  ; 黄灯
113   LD      M23  ; 启动
      ANI     M0  ; 报警
      OUT     M32  ; 绿灯
116   LD      M0  ; 报警
      MPS
      ANI     T196
      AND     SM412
      OUT     M33  ; 蜂鸣器
      MRD
      AND<    D1330 K20
      MOV     K20 D1330
      MPP
      OUT     T196 D1330
132   LD      SM400  ; 始终ON
      MPS
      ANDD=   K0 K8M3000  ; 气缸1（手动）
      ANDD=   K0 K8M3032  ; 气缸33（手动）
      ANDD=   K0 K8M3064
      OUT     M37
      MRD
      ANI     M1  ; 报警清除
      AND=    K0 K1M13  ; 启动(触摸屏)
      ANI     M23  ; 启动
      OUT     M38
      MRD
      AND<    D1322 K50
      MOV     K50 D1322
      MRD
      AND     M37
      AND     M38
      OUT     T198 D1322  ; 附件停机延时
      MPP
      AND     M17  ; 急停（外部按钮）
      ANI     T198  ; 附件停机延时
      OUT     M39  ; 附件停机
171   LDI     M9  ; 总气阀开关（ON为关）
      AND     M17  ; 急停（外部按钮）
      OUT     Y229
      INV
      OUT     M5077  ; 气阀关闭
176   END
END_PROGRAM

PROGRAM 马达初始化
0     LD      M17  ; 急停（外部按钮）
      AND     SM400  ; 始终ON
      MPS
      INV
      BKRST   B500 K200  ; 1#轴复原开始
      MRD
      ANI     M2000  ; 1#伺服ON
      INV
      OUT     M5120  ; 1#马达未激磁！
      MRD
      ANI     M2020  ; 2#伺服ON
      INV
      OUT     M5121  ; 2#马达未激磁！
      MRD
      ANI     M2040  ; 3#伺服ON
      INV
      OUT     M5122  ; 3#马达未激磁！
      MRD
      ANI     M2060  ; 4#伺服ON
      INV
      OUT     M5123  ; 4#马达未激磁！
      MRD
      ANI     M2080  ; 5#伺服ON
      INV
      OUT     M5124  ; 5#马达未激磁！
      MRD
      ANI     M2100  ; 6#伺服ON
      INV
      OUT     M5125  ; 6#马达未激磁！
      MRD
      ANI     M2120  ; 7#伺服ON
      INV
      OUT     M5126  ; 7#马达未激磁！
      MRD
      ANI     M2140  ; 8#伺服ON
      INV
      OUT     M5127  ; 8#马达未激磁！
      MRD
      ANI     M2160  ; 9#伺服ON
      INV
      OUT     M5128  ; 9#马达未激磁！
      MRD
      ANI     M2180  ; 10#伺服ON
      INV
      OUT     M5129  ; 10#马达未激磁！
      MRD
      ANI     M2200  ; 11#伺服ON
      INV
      OUT     M5160  ; 11#马达未激磁！
      MRD
      ANI     M2220  ; 12#伺服ON
      INV
      OUT     M5161  ; 12#马达未激磁！
      MPP
      OUT     Y10  ; LD75P4-CM
      OUT     Y30  ; 2#LD75P4-CM
      OUT     Y60  ; 3#LD75P4-CM
59    LD      SM403
      ANI     M17  ; 急停（外部按钮）
      ?OP6542
      ?OP6543
      OUT     Y14  ; 3#轴停止
      OUT     Y15  ; 4#轴停止
      OUT     Y16  ; 5#轴停止
      OUT     Y17  ; 6#轴停止
      OUT     Y34  ; 7#轴停止
      OUT     Y35  ; 8#轴停止
      OUT     Y36  ; 9#轴停止
      OUT     Y37  ; 10轴停止
      OUT     Y64  ; 11#轴停止
      OUT     Y65  ; 12#轴停止
73    LD      SM400  ; 始终ON
      DMOV    SD1840 D1000  ; 1#轴当前值
      DMOV    SD1860 D1020  ; 2#轴当前值
      DMOV    U1\G800 D1040  ; 3#轴当前值
      DMOV    U1\G900 D1060  ; 4#轴当前值
      DMOV    U1\G1000 D1080  ; 5#轴当前值
      DMOV    U1\G1100 D1100  ; 6#轴当前值
      DMOV    U3\G800 D1120  ; 7#当前值
      DMOV    U3\G900 D1140  ; 8#轴当前值
      DMOV    U3\G1000 D1160  ; 9#当前值
      DMOV    U3\G1100 D1180  ; 10#当前值
110   LD      SM400  ; 始终ON
      MOV     SD1845 D1014  ; 1#轴出错
      MOV     SD1865 D1034  ; 2#轴出错码
      MOV     U1\G806 D1054  ; 3#轴出错码
      MOV     U1\G906 D1074  ; 4#轴出错码
      MOV     U1\G1006 D1094  ; 5#轴出错码
      MOV     U1\G1106 D1114  ; 6#轴出错码
      MOV     U3\G806 D1134  ; 7#轴出错码
      MOV     U3\G906 D1154  ; 8#轴出错码
      MOV     U3\G1006 D1174  ; 9#轴出错码
      MOV     U3\G1106 D1194  ; 10#轴出错码
      MOV     U6\G806 D1214  ; 11#轴出错码
      MOV     U6\G906 D1234  ; 12#轴出错码
155   LD      SM400  ; 始终ON
      MOV     SD1846 D1016  ; 1#轴有效M码
      MOV     SD1866 D1036  ; 2#有效M码
      MOV     U1\G808 D1056  ; 3#有效M码
      MOV     U1\G908 D1076  ; 4#有效M码
      MOV     U1\G1008 D1096  ; 5#有效M码
      MOV     U1\G1108 D1116  ; 6#有效M码
      MOV     U3\G808 D1136  ; 7#有效M码
      MOV     U3\G908 D1156  ; 8#有效M码
      MOV     U3\G1008 D1176  ; 9#有效M码
      MOV     U3\G1108 D1196  ; 10#有效M码
      MOV     U6\G808 D1216  ; 11#有效M码
      MOV     U6\G908 D1236  ; 12#有效M码
200   LD      X14  ; 3#轴代码on
      MOV     K1 U1\G1504
205   LD      X15  ; 4#轴代码on
      MOV     K1 U1\G1604
210   LD      X16  ; 5#轴代码on
      MOV     K1 U1\G1704
215   LD      X17  ; 6#轴代码on
      MOV     K1 U1\G1804
220   LD      X34  ; 7#轴代码on
      MOV     K1 U3\G1504
225   LD      X35  ; 8#轴代码on
      MOV     K1 U3\G1604
230   LD      X36  ; 9#轴代码on
      MOV     K1 U3\G1704
235   LD      X37  ; 10#轴代码on
      MOV     K1 U3\G1804
240   LD      X64  ; 11#轴代码on
      MOV     K1 U6\G1504
245   LD      X65  ; 12#轴代码on
      MOV     K1 U6\G1604
250   LD      M1  ; 报警清除
      OR      M16  ; 停止（外部按钮）
      OUT     SM1850
      OUT     SM1870
      MOV     K1 U1\G1502
      MOV     K1 U1\G1602
      MOV     K1 U1\G1702
      MOV     K1 U1\G1802
      MOV     K1 U3\G1502
      MOV     K1 U3\G1602
      MOV     K1 U3\G1702
      MOV     K1 U3\G1802
      MOV     K1 U6\G1502
      MOV     K1 U6\G1602
294   LD      SM400  ; 始终ON
      MPS
      ANI     SM400  ; 始终ON
      OUT     M5130  ; 1#马达驱动器报警！
      MRD
      ANI     SM400  ; 始终ON
      OUT     M5131  ; 2#马达驱动器报警！
      MRD
      ANI     SM400  ; 始终ON
      OUT     M5132  ; 3#马达驱动器报警！
      MRD
      ANI     X139
      OUT     M5133  ; 4#马达驱动器报警！
      MRD
      ANI     X13A
      OUT     M5134  ; 5#马达驱动器报警！
      MRD
      ANI     X13B
      OUT     M5135  ; 6#马达驱动器报警！
      MRD
      ANI     X13C
      OUT     M5136  ; 7#马达驱动器报警！
      MRD
      ANI     X13D
      OUT     M5137  ; 8#马达驱动器报警！
      MRD
      ANI     X13E
      OUT     M5138  ; 9#马达驱动器报警！
      MRD
      ANI     SM400  ; 始终ON
      OUT     M5139  ; 10#马达驱动器报警！
      MRD
      ANI     X19E
      OUT     M5162  ; 11#马达驱动器报警！
      MPP
      ANI     X19F
      OUT     M5163  ; 12#马达驱动器报警！
331   LD      SM400  ; 始终ON
      MPS
      LD<>    D1014 K0  ; 1#轴出错
      OR      X0C  ; 一般输入
      ANB
      OUT     M5140  ; 1#轴出错异常！
      MRD
      LD<>    D1034 K0  ; 2#轴出错码
      OR      X0D  ; 一般输入
      ANB
      OUT     M5141  ; 2#轴出错异常！
      MRD
      AND<>   D1054 K0  ; 3#轴出错码
      OUT     M5142  ; 3#轴出错异常！
      MRD
      AND<>   D1074 K0  ; 4#轴出错码
      OUT     M5143  ; 4#轴出错异常！
      MRD
      AND<>   D1094 K0  ; 5#轴出错码
      OUT     M5144  ; 5#轴出错异常！
      MRD
      AND<>   D1114 K0  ; 6#轴出错码
      OUT     M5145  ; 6#轴出错异常！
      MRD
      AND<>   D1134 K0  ; 7#轴出错码
      OUT     M5146  ; 7#轴出错异常！
      MRD
      AND<>   D1154 K0  ; 8#轴出错码
      OUT     M5147  ; 8#轴出错异常！
      MRD
      AND<>   D1174 K0  ; 9#轴出错码
      OUT     M5148  ; 9#轴出错异常！
      MRD
      AND<>   D1194 K0  ; 10#轴出错码
      OUT     M5149  ; 10#轴出错异常！
      MRD
      AND<>   D1214 K0  ; 11#轴出错码
      OUT     M5164  ; 11#轴出错异常！
      MPP
      AND<>   D1234 K0  ; 12#轴出错码
      OUT     M5165  ; 12#轴出错异常！
396   LD      SM400  ; 始终ON
      MPS
      AND     M2501  ; 1#轴复原中
      OUT     M5150  ; 1#马达复原中...
      MRD
      AND     M2511  ; 2#轴复原中
      OUT     M5151  ; 2#马达复原中...
      MRD
      AND     M2521  ; 3#轴复原中
      OUT     M5152  ; 3#马达复原中...
      MRD
      AND     M2531  ; 4#轴复原中
      OUT     M5153  ; 4#马达复原中...
      MRD
      AND     M2541  ; 5#轴复原中
      OUT     M5154  ; 5#马达复原中...
      MRD
      AND     M2551  ; 6#轴复原中
      OUT     M5155  ; 6#马达复原中...
      MRD
      AND     M2561  ; 7#轴复原中
      OUT     M5156  ; 7#马达复原中...
      MRD
      AND     M2571  ; 8#轴复原中
      OUT     M5157  ; 8#马达复原中...
      MRD
      AND     M2581  ; 9#轴复原中
      OUT     M5158  ; 9#马达复原中...
      MRD
      AND     M2591  ; 10#轴复原中
      OUT     M5159  ; 10#马达复原中...
      MRD
      AND     M2601  ; 11#轴复原中
      OUT     M5166  ; 11#马达复原中...
      MPP
      AND     M2611  ; 12#轴复原中
      OUT     M5167  ; 12#马达复原中...
433   LD      SM400  ; 始终ON
      AND     M17  ; 急停（外部按钮）
      OUT     T100 K10  ; 1#轴
      OUT     T110 K10  ; 2#轴
      OUT     T120 K10  ; 3#轴
      OUT     T130 K10  ; 4#轴
      OUT     T140 K10  ; 5#轴
      OUT     T150 K10  ; 6#轴
      OUT     T160 K10  ; 7#轴
      OUT     T170 K10  ; 8#轴
      OUT     T180 K10  ; 9#轴
      OUT     T190 K10  ; 10#轴
      OUT     T175 K10  ; 11轴
      OUT     T185 K10  ; 12轴
483   LD      SM400  ; 始终ON
      DMOV    D1456 U1\G1518  ; 3#JOG速度 / 3#JOG速度
      DMOV    D1476 U1\G1618  ; 4#JOG速度 / 4#JOG速度
      DMOV    D1496 U1\G1718  ; 5#JOG速度 / 5#JOG速度
      DMOV    D1516 U1\G1818  ; 6#JOG速度 / 6#JOG速度
      DMOV    D1536 U3\G1518  ; 7#JOG速度 / 7#JOG速度
      DMOV    D1556 U3\G1618  ; 8#JOG速度 / 8#JOG速度
      DMOV    D1576 U3\G1718  ; 9#JOG速度 / 9#JOG速度
      DMOV    D1596 U3\G1818  ; 10#JOG速度 / 10#JOG速度
      DMOV    D1616 U6\G1518  ; 11#JOG速度 / 11#JOG速度
      DMOV    D1636 U6\G1618  ; 12#JOG速度 / 12#JOG速度
524   END
END_PROGRAM

PROGRAM 放料马达
; 铁壳放料马达
8     LD      SM400  ; 始终ON
      MPS
      AND     L500
      OUT     M910
      MRD
      AND     X157
      OUT     M920
      MRD
      AND     M930
      OUT     Y22B
      MPP
      AND     M940
      OUT     M5250
21    LD      SM400  ; 始终ON
      MPS
      AND     M2
      ANI     M920
      AND<>   K0 D900  ; 总产量
      INC     D910  ; 设定产量
      MRD
      ANI     M920
      OUT     T70 K5
      MRD
      LD      T70
      OR      M930
      ANB
      ANI     T71
      MPS
      ANI     M940
      ANI     M910
      ANI     T72
      AND     M17  ; 急停（外部按钮）
      OUT     M930
      MPP
      ANI     T70
      OUT     T71 K10
      MRD
      ANI     M920
      OUT     T72 K50
      AND     T72
      AND>=   D910 D900  ; 设定产量 / 总产量
      SET     M940
      MPP
      LD      M920
      OR      M910
      ANB
      RST     M940
      RST     D910  ; 设定产量
71    LD      SM400  ; 始终ON
      MPS
      AND     L501
      OUT     M911
      MRD
      AND     X158
      OUT     M921
      MRD
      AND     M931
      OUT     Y22C
      MPP
      AND     M941
      OUT     M5254
84    LD      SM400  ; 始终ON
      MPS
      AND     M2
      ANI     M921
      AND<>   K0 D901
      INC     D911
      MRD
      ANI     M921
      OUT     T73 K3
      MRD
      ANI     M911
      ANI     M941
      AND     M17  ; 急停（外部按钮）
      OUT     Y22D
      MRD
      LD      T73
      OR      M931
      ANB
      ANI     T74
      MPS
      ANI     M911
      ANI     M941
      ANI     T75
      AND     M17  ; 急停（外部按钮）
      OUT     M931
      MPP
      ANI     T73
      OUT     T74 K2
      MRD
      ANI     M921
      OUT     T75 K50
      AND     T75
      AND>=   D911 D901
      SET     M941
      MPP
      LD      M921
      OR      M911
      ANB
      RST     M941
      RST     D911
139   END
END_PROGRAM

PROGRAM 效率统计
0     LD      M23  ; 启动
      AND     SM400  ; 始终ON
      MPS
      AND>=   D10100 K1  ; 气缸个数设定
      AND     M5000  ; 气缸1异常！
      INCP    D10000  ; 气缸1报警计数
      MRD
      AND>=   D10100 K2  ; 气缸个数设定
      AND     M5001  ; 气缸2异常！
      INCP    D10001  ; 气缸2报警计数
      MRD
      AND>=   D10100 K3  ; 气缸个数设定
      AND     M5002  ; 气缸3异常！
      INCP    D10002  ; 气缸3报警计数
      MRD
      AND>=   D10100 K4  ; 气缸个数设定
      AND     M5003  ; 气缸4异常！
      INCP    D10003  ; 气缸4报警计数
      MRD
      AND>=   D10100 K5  ; 气缸个数设定
      AND     M5004  ; 气缸5异常！
      INCP    D10004  ; 气缸5报警计数
      MRD
      AND>=   D10100 K6  ; 气缸个数设定
      AND     M5005  ; 气缸6异常！
      INCP    D10005  ; 气缸6报警计数
      MRD
      AND>=   D10100 K7  ; 气缸个数设定
      AND     M5006  ; 气缸7异常！
      INCP    D10006  ; 气缸7报警计数
      MPP
      AND>=   D10100 K8  ; 气缸个数设定
      AND     M5007  ; 气缸8异常！
      INCP    D10007  ; 气缸8报警计数
58    LD      M23  ; 启动
      AND     SM400  ; 始终ON
      MPS
      AND>=   D10100 K9  ; 气缸个数设定
      AND     M5008  ; 气缸9异常！
      INCP    D10008  ; 气缸9报警计数
      MRD
      AND>=   D10100 K10  ; 气缸个数设定
      AND     M5009  ; 气缸10异常！
      INCP    D10009  ; 气缸10报警计数
      MRD
      AND>=   D10100 K11  ; 气缸个数设定
      AND     M5010  ; 气缸11异常！
      INCP    D10010  ; 气缸11报警计数
      MRD
      AND>=   D10100 K12  ; 气缸个数设定
      AND     M5011  ; 气缸12异常！
      INCP    D10011  ; 气缸12报警计数
      MRD
      AND>=   D10100 K13  ; 气缸个数设定
      AND     M5012  ; 气缸13异常！
      INCP    D10012  ; 气缸13报警计数
      MRD
      AND>=   D10100 K14  ; 气缸个数设定
      AND     M5013  ; 气缸14异常！
      INCP    D10013  ; 气缸14报警计数
      MRD
      AND>=   D10100 K15  ; 气缸个数设定
      AND     M5014  ; 气缸15异常！
      INCP    D10014  ; 气缸15报警计数
      MPP
      AND>=   D10100 K16  ; 气缸个数设定
      AND     M5015  ; 气缸16异常！
      INCP    D10015  ; 气缸16报警计数
116   LD      M23  ; 启动
      AND     SM400  ; 始终ON
      MPS
      AND>=   D10100 K17  ; 气缸个数设定
      AND     M5016  ; 气缸17异常！
      INCP    D10016  ; 气缸17报警计数
      MRD
      AND>=   D10100 K18  ; 气缸个数设定
      AND     M5017  ; 气缸18异常！
      INCP    D10017  ; 气缸18报警计数
      MRD
      AND>=   D10100 K19  ; 气缸个数设定
      AND     M5018  ; 气缸19异常！
      INCP    D10018  ; 气缸19报警计数
      MRD
      AND>=   D10100 K20  ; 气缸个数设定
      AND     M5019  ; 气缸20异常！
      INCP    D10019  ; 气缸20报警计数
      MRD
      AND>=   D10100 K21  ; 气缸个数设定
      AND     M5020  ; 气缸21异常！
      INCP    D10020  ; 气缸21报警计数
      MRD
      AND>=   D10100 K22  ; 气缸个数设定
      AND     M5021  ; 气缸22异常！
      INCP    D10021  ; 气缸22报警计数
      MRD
      AND>=   D10100 K23  ; 气缸个数设定
      AND     M5022  ; 气缸23异常！
      INCP    D10022  ; 气缸23报警计数
      MPP
      AND>=   D10100 K24  ; 气缸个数设定
      AND     M5023  ; 气缸24异常！
      INCP    D10023  ; 气缸24报警计数
174   LD      M23  ; 启动
      AND     SM400  ; 始终ON
      MPS
      AND>=   D10100 K25  ; 气缸个数设定
      AND     M5024  ; 气缸25异常！
      INCP    D10024  ; 气缸25报警计数
      MRD
      AND>=   D10100 K26  ; 气缸个数设定
      AND     M5025  ; 气缸26异常！
      INCP    D10025  ; 气缸26报警计数
      MRD
      AND>=   D10100 K27  ; 气缸个数设定
      AND     M5026  ; 气缸27异常！
      INCP    D10026  ; 气缸27报警计数
      MRD
      AND>=   D10100 K28  ; 气缸个数设定
      AND     M5027  ; 气缸28异常！
      INCP    D10027  ; 气缸28报警计数
      MRD
      AND>=   D10100 K29  ; 气缸个数设定
      AND     M5028  ; 气缸29异常！
      INCP    D10028  ; 气缸29报警计数
      MRD
      AND>=   D10100 K30  ; 气缸个数设定
      AND     M5029  ; 气缸30异常！
      INCP    D10029  ; 气缸30报警计数
      MRD
      AND>=   D10100 K31  ; 气缸个数设定
      AND     M5030  ; 气缸31异常！
      INCP    D10030  ; 气缸31报警计数
      MPP
      AND>=   D10100 K32  ; 气缸个数设定
      AND     M5031  ; 气缸32异常！
      INCP    D10031  ; 气缸32报警计数
232   LD      M23  ; 启动
      AND     SM400  ; 始终ON
      MPS
      AND>=   D10100 K33  ; 气缸个数设定
      AND     M5032  ; 气缸33异常！
      INCP    D10032  ; 气缸33报警计数
      MRD
      AND>=   D10100 K34  ; 气缸个数设定
      AND     M5040  ; 气缸41异常！
      INCP    D10033  ; 气缸34报警计数
      MRD
      AND>=   D10100 K35  ; 气缸个数设定
      AND     M5041  ; 气缸42异常！
      INCP    D10034  ; 气缸35报警计数
      MRD
      AND>=   D10100 K36  ; 气缸个数设定
      AND     M5042  ; 气缸43异常！
      INCP    D10035  ; 气缸36报警计数
      MRD
      AND>=   D10100 K37  ; 气缸个数设定
      AND     M5043  ; 气缸44异常！
      INCP    D10036  ; 气缸37报警计数
      MRD
      AND>=   D10100 K38  ; 气缸个数设定
      AND     M5044  ; 气缸45异常！
      INCP    D10037  ; 气缸38报警计数
      MRD
      AND>=   D10100 K39  ; 气缸个数设定
      AND     M5045  ; 气缸46异常！
      INCP    D10038  ; 气缸39报警计数
      MPP
      AND>=   D10100 K40  ; 气缸个数设定
      AND     M5046  ; 气缸47异常！
      INCP    D10039  ; 气缸40报警计数
290   LD      M23  ; 启动
      AND     SM400  ; 始终ON
      MPS
      AND>=   D10100 K41  ; 气缸个数设定
      AND     M5047  ; 气缸48异常！
      INCP    D10040  ; 气缸41报警计数
      MRD
      AND>=   D10100 K42  ; 气缸个数设定
      AND     M5048  ; 气缸49异常！
      INCP    D10041  ; 气缸42报警计数
      MRD
      AND>=   D10100 K43  ; 气缸个数设定
      AND     M5049
      INCP    D10042  ; 气缸43报警计数
      MRD
      AND>=   D10100 K44  ; 气缸个数设定
      AND     M5050
      INCP    D10043  ; 气缸44报警计数
      MRD
      AND>=   D10100 K45  ; 气缸个数设定
      AND     M5051
      INCP    D10044  ; 气缸45报警计数
      MRD
      AND>=   D10100 K46  ; 气缸个数设定
      AND     M5052
      INCP    D10045  ; 气缸46报警计数
      MRD
      AND>=   D10100 K47  ; 气缸个数设定
      AND     M5053
      INCP    D10046  ; 气缸47报警计数
      MPP
      AND>=   D10100 K48  ; 气缸个数设定
      AND     M5054
      INCP    D10047  ; 气缸48报警计数
348   LD      M23  ; 启动
      AND     SM400  ; 始终ON
      MPS
      AND>=   D10100 K49  ; 气缸个数设定
      AND     M5055
      INCP    D10048  ; 气缸49报警计数
      MRD
      AND>=   D10100 K50  ; 气缸个数设定
      AND     M5056
      INCP    D10049  ; 气缸50报警计数
      MRD
      AND>=   D10100 K51  ; 气缸个数设定
      AND     M5057
      INCP    D10050  ; 气缸51报警计数
      MRD
      AND>=   D10100 K52  ; 气缸个数设定
      AND     M5058
      INCP    D10051  ; 气缸52报警计数
      MRD
      AND>=   D10100 K53  ; 气缸个数设定
      AND     M5059
      INCP    D10052  ; 气缸53报警计数
      MRD
      AND>=   D10100 K54  ; 气缸个数设定
      AND     M5060
      INCP    D10053  ; 气缸54报警计数
      MRD
      AND>=   D10100 K55  ; 气缸个数设定
      AND     M5063
      INCP    D10054  ; 气缸55报警计数
      MPP
      AND>=   D10100 K56  ; 气缸个数设定
      AND     M5064
      INCP    D10055  ; 气缸56报警计数
406   LD      M23  ; 启动
      AND     SM400  ; 始终ON
      MPS
      AND>=   D10100 K57  ; 气缸个数设定
      AND     M5065
      INCP    D10056  ; 气缸57报警计数
      MRD
      AND>=   D10100 K58  ; 气缸个数设定
      AND     M5066
      INCP    D10057  ; 气缸58报警计数
      MRD
      AND>=   D10100 K59  ; 气缸个数设定
      AND     M5067
      INCP    D10058  ; 气缸59报警计数
      MRD
      AND>=   D10100 K60  ; 气缸个数设定
      AND     M5068
      INCP    D10059  ; 气缸60报警计数
      MRD
      AND>=   D10100 K61  ; 气缸个数设定
      AND     M5069
      INCP    D10060  ; 气缸61报警计数
      MRD
      AND>=   D10100 K62  ; 气缸个数设定
      AND     M5250
      INCP    D10061  ; 气缸62报警计数
      MRD
      AND>=   D10100 K63  ; 气缸个数设定
      AND     M5251
      ANI     SM400  ; 始终ON
      INCP    D10062  ; 气缸63报警计数
      MPP
      AND>=   D10100 K64  ; 气缸个数设定
      AND     M5252
      INCP    D10063  ; 气缸64报警计数
465   LD      M23  ; 启动
      AND     SM400  ; 始终ON
      MPS
      AND>=   D10100 K65  ; 气缸个数设定
      AND     M5253
      INCP    D10064  ; 气缸65报警计数
      MRD
      AND>=   D10100 K66  ; 气缸个数设定
      AND     M5033  ; 气缸34异常！
      INCP    D10065  ; 气缸66报警计数
      MRD
      AND>=   D10100 K67  ; 气缸个数设定
      ANI     SM400  ; 始终ON
      INCP    D10066  ; 气缸67报警计数
      MRD
      AND>=   D10100 K68  ; 气缸个数设定
      ANI     SM400  ; 始终ON
      INCP    D10067  ; 气缸68报警计数
      MRD
      AND>=   D10100 K69  ; 气缸个数设定
      ANI     SM400  ; 始终ON
      INCP    D10068  ; 气缸69报警计数
      MRD
      AND>=   D10100 K70  ; 气缸个数设定
      ANI     SM400  ; 始终ON
      INCP    D10069  ; 气缸70报警计数
      MRD
      AND>=   D10100 K71  ; 气缸个数设定
      ANI     SM400  ; 始终ON
      INCP    D10070  ; 气缸71报警计数
      MPP
      AND>=   D10100 K72  ; 气缸个数设定
      ANI     SM400  ; 始终ON
      INCP    D10071  ; 气缸72报警计数
523   LD      M23  ; 启动
      AND     SM400  ; 始终ON
      MPS
      AND>=   D10100 K73  ; 气缸个数设定
      ANI     SM400  ; 始终ON
      INCP    D10072  ; 气缸73报警计数
      MRD
      AND>=   D10100 K74  ; 气缸个数设定
      ANI     SM400  ; 始终ON
      INCP    D10073  ; 气缸74报警计数
      MRD
      AND>=   D10100 K75  ; 气缸个数设定
      ANI     SM400  ; 始终ON
      INCP    D10074  ; 气缸75报警计数
      MRD
      AND>=   D10100 K76  ; 气缸个数设定
      ANI     SM400  ; 始终ON
      INCP    D10075  ; 气缸76报警计数
      MRD
      AND>=   D10100 K77  ; 气缸个数设定
      ANI     SM400  ; 始终ON
      INCP    D10076  ; 气缸77报警计数
      MRD
      AND>=   D10100 K78  ; 气缸个数设定
      ANI     SM400  ; 始终ON
      INCP    D10077  ; 气缸78报警计数
      MRD
      AND>=   D10100 K79  ; 气缸个数设定
      ANI     SM400  ; 始终ON
      INCP    D10078  ; 气缸79报警计数
      MPP
      AND>=   D10100 K80  ; 气缸个数设定
      ANI     SM400  ; 始终ON
      INCP    D10079  ; 气缸80报警计数
581   LD      SM400  ; 始终ON
      WSUM    D10000 D10082 K80  ; 报警总数
586   LD      SM400  ; 始终ON
      MOV     K8 D11010  ; 设定时间下限（时）
      MOV     K0 D11011  ; 设定时间下限（分）
      MOV     K0 D11012  ; 设定时间下限（秒）
      MOV     K23 D11020  ; 设定时间上限（时）
      MOV     K59 D11021  ; 设定时间上限（分）
      MOV     K59 D11022  ; 设定时间上限（秒）
599   LD      SM400  ; 始终ON
      MPS
      AND>=   D8193 D11010  ; 当前-时 / 设定时间下限（时）
      AND<=   D8193 D11020  ; 当前-时 / 设定时间上限（时）
      OUT     M10001
      MPP
      AND=    D8192 D11032  ; 当前-日 / 当前日期保存（日）
      OUT     M10011
613   LDI     M10011
      AND     M10001
      PLS     M10100
      WSFLP   D11030 D10110 K6 K1  ; 当前日期保存（年） / 日期保存（年）
      WSFLP   D11031 D10120 K6 K1  ; 当前日期保存（月） / 日期保存（月）
      WSFLP   D11032 D10130 K6 K1  ; 日期保存（日）
      MOVP    D8190 D11030
      MOVP    D8191 D11031
      MOVP    D8192 D11032
638   LD      M10100
      MPS
      AND>=   D10100 K1  ; 气缸个数设定
      WSFLP   D10000 D10200 K8 K1  ; 气缸1报警记录保存
      MRD
      AND>=   D10100 K2  ; 气缸个数设定
      WSFLP   D10001 D10210 K8 K1  ; 气缸2报警记录保存
      MRD
      AND>=   D10100 K3  ; 气缸个数设定
      WSFLP   D10002 D10220 K8 K1  ; 气缸3报警记录保存
      MRD
      AND>=   D10100 K4  ; 气缸个数设定
      WSFLP   D10003 D10230 K8 K1  ; 气缸4报警记录保存
      MRD
      AND>=   D10100 K5  ; 气缸个数设定
      WSFLP   D10004 D10240 K8 K1  ; 气缸5报警记录保存
      MRD
      AND>=   D10100 K6  ; 气缸个数设定
      WSFLP   D10005 D10250 K8 K1  ; 气缸6报警记录保存
      MRD
      AND>=   D10100 K7  ; 气缸个数设定
      WSFLP   D10006 D10260 K8 K1  ; 气缸7报警记录保存
      MRD
      AND>=   D10100 K8  ; 气缸个数设定
      WSFLP   D10007 D10270 K8 K1  ; 气缸8报警记录保存
      MPP
      WSFLP   D10082 D10090 K8 K1  ; 报警记录1总数
717   LD      M10100
      MPS
      AND>=   D10100 K9  ; 气缸个数设定
      WSFLP   D10008 D10280 K8 K1  ; 气缸9报警记录保存
      MRD
      AND>=   D10100 K10  ; 气缸个数设定
      WSFLP   D10009 D10290 K8 K1  ; 气缸10报警记录保存
      MRD
      AND>=   D10100 K11  ; 气缸个数设定
      WSFLP   D10010 D10300 K8 K1  ; 气缸11报警记录保存
      MRD
      AND>=   D10100 K12  ; 气缸个数设定
      WSFLP   D10011 D10310 K8 K1  ; 气缸12报警记录保存
      MRD
      AND>=   D10100 K13  ; 气缸个数设定
      WSFLP   D10012 D10320 K8 K1  ; 气缸13报警记录保存
      MRD
      AND>=   D10100 K14  ; 气缸个数设定
      WSFLP   D10013 D10330 K8 K1  ; 气缸14报警记录保存
      MRD
      AND>=   D10100 K15  ; 气缸个数设定
      WSFLP   D10014 D10340 K8 K1  ; 气缸15报警记录保存
      MPP
      AND>=   D10100 K16  ; 气缸个数设定
      WSFLP   D10015 D10350 K8 K1  ; 气缸16报警记录保存
790   LD      M10100
      MPS
      AND>=   D10100 K17  ; 气缸个数设定
      WSFLP   D10016 D10360 K8 K1  ; 气缸17报警记录保存
      MRD
      AND>=   D10100 K18  ; 气缸个数设定
      WSFLP   D10017 D10370 K8 K1  ; 气缸18报警记录保存
      MRD
      AND>=   D10100 K19  ; 气缸个数设定
      WSFLP   D10018 D10380 K8 K1  ; 气缸19报警记录保存
      MRD
      AND>=   D10100 K20  ; 气缸个数设定
      WSFLP   D10019 D10390 K8 K1  ; 气缸20报警记录保存
      MRD
      AND>=   D10100 K21  ; 气缸个数设定
      WSFLP   D10020 D10400 K8 K1  ; 气缸21报警记录保存
      MRD
      AND>=   D10100 K22  ; 气缸个数设定
      WSFLP   D10021 D10410 K8 K1  ; 气缸22报警记录保存
      MRD
      AND>=   D10100 K23  ; 气缸个数设定
      WSFLP   D10022 D10420 K8 K1  ; 气缸23报警记录保存
      MPP
      AND>=   D10100 K24  ; 气缸个数设定
      WSFLP   D10023 D10430 K8 K1  ; 气缸24报警记录保存
863   LD      M10100
      MPS
      AND>=   D10100 K25  ; 气缸个数设定
      WSFLP   D10024 D10440 K8 K1  ; 气缸25报警记录保存
      MRD
      AND>=   D10100 K26  ; 气缸个数设定
      WSFLP   D10025 D10450 K8 K1  ; 气缸26报警记录保存
      MRD
      AND>=   D10100 K27  ; 气缸个数设定
      WSFLP   D10026 D10460 K8 K1  ; 气缸27报警记录保存
      MRD
      AND>=   D10100 K28  ; 气缸个数设定
      WSFLP   D10027 D10470 K8 K1  ; 气缸28报警记录保存
      MRD
      AND>=   D10100 K29  ; 气缸个数设定
      WSFLP   D10028 D10480 K8 K1  ; 气缸29报警记录保存
      MRD
      AND>=   D10100 K30  ; 气缸个数设定
      WSFLP   D10029 D10490 K8 K1  ; 气缸30报警记录保存
      MRD
      AND>=   D10100 K31  ; 气缸个数设定
      WSFLP   D10030 D10500 K8 K1  ; 气缸31报警记录保存
      MPP
      AND>=   D10100 K32  ; 气缸个数设定
      WSFLP   D10031 D10510 K8 K1  ; 气缸32报警记录保存
936   LD      M10100
      MPS
      AND>=   D10100 K33  ; 气缸个数设定
      WSFLP   D10032 D10520 K8 K1  ; 气缸33报警记录保存
      MRD
      AND>=   D10100 K34  ; 气缸个数设定
      WSFLP   D10033 D10530 K8 K1  ; 气缸34报警记录保存
      MRD
      AND>=   D10100 K35  ; 气缸个数设定
      WSFLP   D10034 D10540 K8 K1  ; 气缸35报警记录保存
      MRD
      AND>=   D10100 K36  ; 气缸个数设定
      WSFLP   D10035 D10550 K8 K1  ; 气缸36报警记录保存
      MRD
      AND>=   D10100 K37  ; 气缸个数设定
      WSFLP   D10036 D10560 K8 K1  ; 气缸37报警记录保存
      MRD
      AND>=   D10100 K38  ; 气缸个数设定
      WSFLP   D10037 D10570 K8 K1  ; 气缸38报警记录保存
      MRD
      AND>=   D10100 K39  ; 气缸个数设定
      WSFLP   D10038 D10580 K8 K1  ; 气缸39报警记录保存
      MPP
      AND>=   D10100 K40  ; 气缸个数设定
      WSFLP   D10039 D10590 K8 K1  ; 气缸40报警记录保存
1009  LD      M10100
      MPS
      AND>=   D10100 K41  ; 气缸个数设定
      WSFLP   D10040 D10600 K8 K1  ; 气缸41报警记录保存
      MRD
      AND>=   D10100 K42  ; 气缸个数设定
      WSFLP   D10041 D10610 K8 K1  ; 气缸42报警记录保存
      MRD
      AND>=   D10100 K43  ; 气缸个数设定
      WSFLP   D10042 D10620 K8 K1  ; 气缸43报警记录保存
      MRD
      AND>=   D10100 K44  ; 气缸个数设定
      WSFLP   D10043 D10630 K8 K1  ; 气缸44报警记录保存
      MRD
      AND>=   D10100 K45  ; 气缸个数设定
      WSFLP   D10044 D10640 K8 K1  ; 气缸45报警记录保存
      MRD
      AND>=   D10100 K46  ; 气缸个数设定
      WSFLP   D10045 D10650 K8 K1  ; 气缸46报警记录保存
      MRD
      AND>=   D10100 K47  ; 气缸个数设定
      WSFLP   D10046 D10660 K8 K1  ; 气缸47报警记录保存
      MPP
      AND>=   D10100 K48  ; 气缸个数设定
      WSFLP   D10047 D10670 K8 K1  ; 气缸48报警记录保存
1082  LD      M10100
      MPS
      AND>=   D10100 K49  ; 气缸个数设定
      WSFLP   D10048 D10680 K8 K1  ; 气缸49报警记录保存
      MRD
      AND>=   D10100 K50  ; 气缸个数设定
      WSFLP   D10049 D10690 K8 K1  ; 气缸50报警记录保存
      MRD
      AND>=   D10100 K51  ; 气缸个数设定
      WSFLP   D10050 D10700 K8 K1  ; 气缸51报警记录保存
      MRD
      AND>=   D10100 K52  ; 气缸个数设定
      WSFLP   D10051 D10710 K8 K1  ; 气缸52报警记录保存
      MRD
      AND>=   D10100 K53  ; 气缸个数设定
      WSFLP   D10052 D10720 K8 K1  ; 气缸53报警记录保存
      MRD
      AND>=   D10100 K54  ; 气缸个数设定
      WSFLP   D10053 D10730 K8 K1  ; 气缸54报警记录保存
      MRD
      AND>=   D10100 K55  ; 气缸个数设定
      WSFLP   D10054 D10740 K8 K1  ; 气缸55报警记录保存
      MPP
      AND>=   D10100 K56  ; 气缸个数设定
      WSFLP   D10055 D10750 K8 K1  ; 气缸56报警记录保存
1155  LD      M10100
      MPS
      AND>=   D10100 K57  ; 气缸个数设定
      WSFLP   D10056 D10760 K8 K1  ; 气缸57报警记录保存
      MRD
      AND>=   D10100 K58  ; 气缸个数设定
      WSFLP   D10057 D10770 K8 K1  ; 气缸58报警记录保存
      MRD
      AND>=   D10100 K59  ; 气缸个数设定
      WSFLP   D10058 D10780 K8 K1  ; 气缸59报警记录保存
      MRD
      AND>=   D10100 K60  ; 气缸个数设定
      WSFLP   D10059 D10790 K8 K1  ; 气缸60报警记录保存
      MRD
      AND>=   D10100 K61  ; 气缸个数设定
      WSFLP   D10060 D10800 K8 K1  ; 气缸61报警记录保存
      MRD
      AND>=   D10100 K62  ; 气缸个数设定
      WSFLP   D10061 D10810 K8 K1  ; 气缸62报警记录保存
      MRD
      AND>=   D10100 K63  ; 气缸个数设定
      WSFLP   D10062 D10820 K8 K1  ; 气缸63报警记录保存
      MPP
      AND>=   D10100 K64  ; 气缸个数设定
      WSFLP   D10063 D10830 K8 K1  ; 气缸64报警记录保存
1228  LD      M10100
      MPS
      AND>=   D10100 K65  ; 气缸个数设定
      WSFLP   D10064 D10840 K8 K1  ; 气缸65报警记录保存
      MRD
      AND>=   D10100 K66  ; 气缸个数设定
      WSFLP   D10065 D10850 K8 K1  ; 气缸66报警记录保存
      MRD
      AND>=   D10100 K67  ; 气缸个数设定
      WSFLP   D10066 D10860 K8 K1  ; 气缸67报警记录保存
      MRD
      AND>=   D10100 K68  ; 气缸个数设定
      WSFLP   D10067 D10870 K8 K1  ; 气缸68报警记录保存
      MRD
      AND>=   D10100 K69  ; 气缸个数设定
      WSFLP   D10068 D10880 K8 K1  ; 气缸69报警记录保存
      MRD
      AND>=   D10100 K70  ; 气缸个数设定
      WSFLP   D10069 D10890 K8 K1  ; 气缸70报警记录保存
      MRD
      AND>=   D10100 K71  ; 气缸个数设定
      WSFLP   D10070 D10900 K8 K1  ; 其他项1报警记录保存
      MPP
      AND>=   D10100 K72  ; 气缸个数设定
      WSFLP   D10071 D10910 K8 K1  ; 其他项2报警记录保存
1301  LD      M10100
      MPS
      AND>=   D10100 K73  ; 气缸个数设定
      WSFLP   D10072 D10920 K8 K1  ; 其他项3报警记录保存
      MRD
      AND>=   D10100 K74  ; 气缸个数设定
      WSFLP   D10073 D10930 K8 K1  ; 其他项4报警记录保存
      MRD
      AND>=   D10100 K75  ; 气缸个数设定
      WSFLP   D10074 D10940 K8 K1  ; 其他项5报警记录保存
      MRD
      AND>=   D10100 K76  ; 气缸个数设定
      WSFLP   D10075 D10950 K8 K1  ; 其他项6报警记录保存
      MRD
      AND>=   D10100 K77  ; 气缸个数设定
      WSFLP   D10076 D10960 K8 K1  ; 其他项7报警记录保存
      MRD
      AND>=   D10100 K78  ; 气缸个数设定
      WSFLP   D10077 D10970 K8 K1  ; 其他项8报警记录保存
      MRD
      AND>=   D10100 K79  ; 气缸个数设定
      WSFLP   D10078 D10980 K8 K1  ; 其他项9报警记录保存
      MRD
      AND>=   D10100 K80  ; 气缸个数设定
      WSFLP   D10079 D10990 K8 K1  ; 其他项10报警记录保存
      MPP
      FMOV    K0 D10000 K80
1379  LD      SM400  ; 始终ON
      MOV     D8193 D11600  ; 当前时间（时）
      MOV     D8194 D11601  ; 当前-分 / 当前时间（分）
      MOV     D8195 D11602  ; 当前时间（秒）
1386  LD      SM400  ; 始终ON
      MPS
      ?OP402611 D11600 D11400 K7  ; 上班时间（上午）
      ?OP402811 D11600 D11410 K7  ; 下班时间（下午）
      OUT     M10201  ; 在计时范围1
      MRD
      ?OP402611 D11600 D11420 K7  ; 上班时间（下午）
      ?OP402811 D11600 D11430 K7  ; 下班时间（下午）
      OUT     M10211  ; 在计时范围2
      MRD
      ?OP402611 D11600 D11440 K7  ; 上班时间（晚上加班）
      ?OP402811 D11600 D11450 K7  ; 下班时间（晚上加班）
      OUT     M10221  ; 在计时范围3
      MRD
      ?OP402611 D11600 D11460 K7  ; 上班时间（晚班上午）
      ?OP402811 D11600 D11470 K7  ; 下班时间（晚班上午）
      OUT     M10231  ; 在计时范围4
      MRD
      ?OP402611 D11600 D11480 K7  ; 上班时间（晚班下午）
      ?OP402811 D11600 D11490 K7  ; 下班时间（晚班下午）
      OUT     M10241  ; 在计时范围5
      MPP
      ?OP402611 D11600 D11510 K7  ; 下班时间（晚班加班）
      ?OP402811 D11600 D11520 K7
      OUT     M10251  ; 在计时范围6
1447  LD      M10201  ; 在计时范围1
      OR      M10211  ; 在计时范围2
      OR      M10221  ; 在计时范围3
      OR      M10231  ; 在计时范围4
      OR      M10241  ; 在计时范围5
      OR      M10251  ; 在计时范围6
      OUT     M10260  ; 在计时范围内（ON有效）
1454  LD      M10260  ; 在计时范围内（ON有效）
      MPS
      AND     SM400  ; 始终ON
      OUT     M10280  ; 通电时间计数条件
      MRD
      AND     M23  ; 启动
      OUT     M10281  ; 运行时间计数条件
      MRD
      AND     M568
      ANI     SM400  ; 始终ON
      OUT     M10282  ; 试机时间计数条件
      MRD
      AND<>   K2M5250 K0
      OUT     M10283  ; 待料时间计数条件
      MRD
      AND     M800  ; 气缸1-1
      ANI     SM400  ; 始终ON
      OUT     M10284  ; 满料时间计数条件
      MRD
      ANI     M23  ; 启动
      OUT     M10285  ; 待启动时间计数条件
      MPP
      LDD<>   K0 K8M5000  ; 气缸1异常！
      ORD<>   K0 K8M5030  ; 气缸31异常！
      ORD<>   K0 K8M5060
      ORD<>   K0 K8M5090
      ORD<>   K0 K8M5100  ; 1#不良品盒满！
      ORD<>   K0 K8M5130  ; 1#马达驱动器报警！
      ORD<>   K0 K8M5160  ; 11#马达未激磁！
      ORD<>   K0 K8M5190  ; 易损件11保养周期到！
      ANB
      OUT     M10286  ; 故障时间计数条件
1512  LD      SM400  ; 始终ON
      MPS
      AND     M10280  ; 通电时间计数条件
      ANDP    SM412
      DINCP   D11070  ; 当前通电时间
      MRD
      AND     M10281  ; 运行时间计数条件
      AND=    K1M10282 K0  ; 试机时间计数条件
      ANI     M10286  ; 故障时间计数条件
      ANDP    SM412
      DINCP   D11072  ; 当前运行时间
      MRD
      AND     M10284  ; 满料时间计数条件
      ANI     M10285  ; 待启动时间计数条件
      ANI     M10283  ; 待料时间计数条件
      ANI     M10282  ; 试机时间计数条件
      ANI     M10286  ; 故障时间计数条件
      ANDP    SM412
      DINCP   D11078  ; 当前满料时间
      MRD
      AND     M10285  ; 待启动时间计数条件
      ANI     M10283  ; 待料时间计数条件
      ANI     M10282  ; 试机时间计数条件
      ANI     M10286  ; 故障时间计数条件
      ANDP    SM412
      DINCP   D11080  ; 当前待启动时间
      MRD
      AND     M10283  ; 待料时间计数条件
      ANI     M10282  ; 试机时间计数条件
      ANI     M10286  ; 故障时间计数条件
      ANDP    SM412
      DINCP   D11076  ; 当前待料时间
      MRD
      AND     M10282  ; 试机时间计数条件
      ANI     M10286  ; 故障时间计数条件
      ANDP    SM412
      DINCP   D11074  ; 当前试机时间
      MPP
      AND     M10286  ; 故障时间计数条件
      ANDP    SM412
      DINCP   D11082  ; 当前故障时间
1562  LD      M10100
      ORP     M40  ; 产能清除
      FMOV    K0 D1310 K10  ; 当前产能
1568  LD      SM400  ; 始终ON
      D*      D10082 K10000 D11380  ; 报警总数
      MPS
      AND<>   D11000 K0  ; 当天产能
      D/      D11380 D11000 D11384  ; 报警/K
      MPP
      ANDD=   D11380 K0  ; 报警总数
      ANDD=   D11000 K0  ; 当天产能
      DMOV    K0 D11384
1592  LD      M10100
      WSFLP   D11000 D11180 K16 K2  ; 当前产能记录1
      DMOV    K0 D11000
      WSFLP   D11070 D11100 K10 K2  ; 通电时间记录1
      WSFLP   D11072 D11110 K10 K2  ; 运行时间记录1
      WSFLP   D11074 D11120 K10 K2  ; 试机时间记录1
      WSFLP   D11076 D11130 K10 K2  ; 待料时间记录1
      WSFLP   D11078 D11140 K10 K2  ; 满料时间记录1
      WSFLP   D11080 D11150 K10 K2  ; 待启动时间记录1
      WSFLP   D11082 D11160 K10 K2  ; 故障时间记录1
      WSFLP   D11384 D11050 K16 K2  ; 报警/K记录1
      FMOV    K0 D10000 K80
1645  LD      SM400  ; 始终ON
      D/      D11070 K2 D11200  ; 当前通电时间(柱状图)
      D/      D11072 K2 D11210  ; 当前运行时间（柱状图）
      D/      D11074 K2 D11220  ; 当前试机时间（柱状图）
      D/      D11076 K2 D11230  ; 当前待料时间（柱状图）
      D/      D11078 K2 D11240  ; 当前满料时间（柱状图）
      D/      D11080 K2 D11250  ; 当前待启动时间（柱状图）
      D/      D11082 K2 D11260  ; 当前故障时间（柱状图）
1674  LD      M10100
      WSFLP   D11200 D11300 K10 K1  ; 通电时间记录1(柱状图)
      WSFLP   D11210 D11310 K10 K1  ; 运行时间记录1（柱状图）
      WSFLP   D11220 D11320 K10 K1  ; 试机时间记录1（柱状图）
      WSFLP   D11230 D11330 K10 K1  ; 待料时间记录1（柱状图）
      WSFLP   D11240 D11340 K10 K1  ; 满料时间记录1（柱状图）
      WSFLP   D11250 D11350 K10 K1  ; 待启动时间记录1（柱状图）
      WSFLP   D11260 D11360 K10 K1  ; 故障时间记录1（柱状图）
1710  LD      M10100
      FMOV    K0 D11070 K16
1715  LDP     M11720
      AND>    D10100 K27  ; 气缸个数设定
      MOV     K151 D30  ; 人机控制页
1721  LDP     M11721
      LDP     M11722
      AND<=   D10100 K54  ; 气缸个数设定
      ORB
      MOV     K150 D30
1729  LDP     M11722
      AND>    D10100 K54  ; 气缸个数设定
      MOV     K152 D30
1735  LDP     M11723
      AND>    D10100 K27  ; 气缸个数设定
      ORP     M11726
      MOV     K154 D30
1742  LDP     M11723
      AND<=   D10100 K27  ; 气缸个数设定
      LDP     M11725
      AND<=   D10100 K54  ; 气缸个数设定
      ORB
      ORP     M11727
      MOV     K156 D30
1754  LDP     M11724
      MOV     K153 D30
1757  LDP     M11725
      AND>    D10100 K54  ; 气缸个数设定
      MOV     K155 D30
1763  LDP     M11732
      MPS
      AND>    D10100 K54  ; 气缸个数设定
      AND<=   D10100 K80  ; 气缸个数设定
      MOV     K155 D30
      MRD
      AND>    D10100 K27  ; 气缸个数设定
      AND<=   D10100 K54  ; 气缸个数设定
      MOV     K154 D30
      MPP
      AND<=   D10100 K27  ; 气缸个数设定
      MOV     K153 D30
1788  LDP     M11733
      AND>    D10100 K27  ; 气缸个数设定
      ORP     M11736
      MOV     K157 D30
1795  LDP     M11733
      AND<=   D10100 K27  ; 气缸个数设定
      LDP     M11735
      AND<=   D10100 K54  ; 气缸个数设定
      ORB
      ORP     M11737
      MOV     K159 D30
1807  LDP     M11734
      MOV     K156 D30
1810  LDP     M11735
      AND>    D10100 K54  ; 气缸个数设定
      MOV     K158 D30
1816  LDP     M11742
      MPS
      AND>    D10100 K54  ; 气缸个数设定
      AND<=   D10100 K80  ; 气缸个数设定
      MOV     K158 D30
      MRD
      AND>    D10100 K27  ; 气缸个数设定
      AND<=   D10100 K54  ; 气缸个数设定
      MOV     K157 D30
      MPP
      AND<=   D10100 K27  ; 气缸个数设定
      MOV     K156 D30
1841  LDP     M11743
      AND>    D10100 K27  ; 气缸个数设定
      ORP     M11746
      MOV     K160 D30
1848  LDP     M11743
      AND<=   D10100 K27  ; 气缸个数设定
      LDP     M11745
      AND<=   D10100 K54  ; 气缸个数设定
      ORB
      ORP     M11747
      MOV     K162 D30
1860  LDP     M11744
      MOV     K159 D30
1863  LDP     M11745
      AND>    D10100 K54  ; 气缸个数设定
      MOV     K161 D30
1869  LDP     M11752
      MPS
      AND>    D10100 K54  ; 气缸个数设定
      AND<=   D10100 K80  ; 气缸个数设定
      MOV     K161 D30
      MRD
      AND>    D10100 K27  ; 气缸个数设定
      AND<=   D10100 K54  ; 气缸个数设定
      MOV     K160 D30
      MPP
      AND<=   D10100 K27  ; 气缸个数设定
      MOV     K169 D30
1894  LDP     M11753
      AND>    D10100 K27  ; 气缸个数设定
      ORP     M11756
      MOV     K163 D30
1901  LDP     M11753
      AND<=   D10100 K27  ; 气缸个数设定
      LDP     M11755
      AND<=   D10100 K54  ; 气缸个数设定
      ORB
      ORP     M11757
      MOV     K153 D30
1913  LDP     M11754
      MOV     K162 D30
1916  LDP     M11755
      AND>    D10100 K54  ; 气缸个数设定
      MOV     K164 D30
1922  LD      SM400  ; 始终ON
      MOV     D8193 D11600
      MOV     D8194 D11601
      MOV     D8195 D11602
; 各时段产能
1936  LD      SM400  ; 始终ON
      SECOND  D11600 D11605  ; 当前时间（时） / 当前（秒）
      MOV     K1 D11040
1942  LD      SM400  ; 始终ON
      OUT     M10500  ; ON为8:00 OFF为7:50
1944  LDI     SM400  ; 始终ON
      AND>    D999 K0
      MPS
      ANI     T399
      OUT     T399 K20
      MPP
      AND     T399
      DEC     D999
1958  LD      M2
      MPS
      LD      M10500  ; ON为8:00 OFF为7:50
      ANDD>=  D11605 K28800  ; 当前（秒）
      ANDD<   D11605 K32400  ; 当前（秒）
      LDI     M10500  ; ON为8:00 OFF为7:50
      ANDD>=  D11605 K28200  ; 当前（秒）
      ANDD<   D11605 K31800  ; 当前（秒）
      ORB
      ANB
      INCP    D11700  ; 8:00-9:00
      MRD
      LD      M10500  ; ON为8:00 OFF为7:50
      ANDD>=  D11605 K32400  ; 当前（秒）
      ANDD<   D11605 K36000  ; 当前（秒）
      LDI     M10500  ; ON为8:00 OFF为7:50
      ANDD>=  D11605 K31800  ; 当前（秒）
      ANDD<   D11605 K35400  ; 当前（秒）
      ORB
      ANB
      INCP    D11701  ; 9:00-10:00
      MRD
      LD      M10500  ; ON为8:00 OFF为7:50
      ANDD>=  D11605 K36000  ; 当前（秒）
      ANDD<   D11605 K39600  ; 当前（秒）
      LDI     M10500  ; ON为8:00 OFF为7:50
      ANDD>=  D11605 K35400  ; 当前（秒）
      ANDD<   D11605 K39000  ; 当前（秒）
      ORB
      ANB
      INCP    D11702  ; 10:00-11:00
      MRD
      LD      M10500  ; ON为8:00 OFF为7:50
      ANDD>=  D11605 K39600  ; 当前（秒）
      ANDD<   D11605 K43200  ; 当前（秒）
      LDI     M10500  ; ON为8:00 OFF为7:50
      ANDD>=  D11605 K39000  ; 当前（秒）
      ANDD<   D11605 K42600  ; 当前（秒）
      ORB
      ANB
      INCP    D11703  ; 11:00-12:00
      MPP
      LD      M10500  ; ON为8:00 OFF为7:50
      ANDD>=  D11605 K48600  ; 当前（秒）
      ANDD<   D11605 K52200  ; 当前（秒）
      LDI     M10500  ; ON为8:00 OFF为7:50
      ANDD>=  D11605 K48000  ; 当前（秒）
      ANDD<   D11605 K51600  ; 当前（秒）
      ORB
      ANB
      INCP    D11704  ; 13;30-14:30
2074  LD      M2
      MPS
      LD      M10500  ; ON为8:00 OFF为7:50
      ANDD>=  D11605 K52200  ; 当前（秒）
      ANDD<   D11605 K55800  ; 当前（秒）
      LDI     M10500  ; ON为8:00 OFF为7:50
      ANDD>=  D11605 K51600  ; 当前（秒）
      ANDD<   D11605 K55200  ; 当前（秒）
      ORB
      ANB
      INCP    D11705  ; 14:30-15:30
      MRD
      LD      M10500  ; ON为8:00 OFF为7:50
      ANDD>=  D11605 K55800  ; 当前（秒）
      ANDD<   D11605 K59400  ; 当前（秒）
      LDI     M10500  ; ON为8:00 OFF为7:50
      ANDD>=  D11605 K55200  ; 当前（秒）
      ANDD<   D11605 K58800  ; 当前（秒）
      ORB
      ANB
      INCP    D11706  ; 15:30-16:30
      MRD
      LD      M10500  ; ON为8:00 OFF为7:50
      ANDD>=  D11605 K59400  ; 当前（秒）
      ANDD<   D11605 K63000  ; 当前（秒）
      LDI     M10500  ; ON为8:00 OFF为7:50
      ANDD>=  D11605 K58800  ; 当前（秒）
      ANDD<   D11605 K62400  ; 当前（秒）
      ORB
      ANB
      INCP    D11707  ; 16:30-17:30
      MRD
      LD      M10500  ; ON为8:00 OFF为7:50
      ANDD>=  D11605 K64800  ; 当前（秒）
      ANDD<   D11605 K68400  ; 当前（秒）
      LDI     M10500  ; ON为8:00 OFF为7:50
      ANDD>=  D11605 K64200  ; 当前（秒）
      ANDD<   D11605 K67800  ; 当前（秒）
      ORB
      ANB
      INCP    D11708  ; 18:00-19:00
      MPP
      LD      M10500  ; ON为8:00 OFF为7:50
      ANDD>=  D11605 K68400  ; 当前（秒）
      ANDD<   D11605 K72000  ; 当前（秒）
      LDI     M10500  ; ON为8:00 OFF为7:50
      ANDD>=  D11605 K67800  ; 当前（秒）
      ANDD<   D11605 K71400  ; 当前（秒）
      ORB
      ANB
      INCP    D11709  ; 19:00-20:00
2190  LD      M2
      MPS
      LD      M10500  ; ON为8:00 OFF为7:50
      ANDD>=  D11605 K72000  ; 当前（秒）
      ANDD<   D11605 K75600  ; 当前（秒）
      LDI     M10500  ; ON为8:00 OFF为7:50
      ANDD>=  D11605 K71400  ; 当前（秒）
      ANDD<   D11605 K75000  ; 当前（秒）
      ORB
      ANB
      DINCP   D11710  ; 20:00-21:00
      MRD
      LD      M10500  ; ON为8:00 OFF为7:50
      ANDD>=  D11605 K75600  ; 当前（秒）
      ANDD<   D11605 K79200  ; 当前（秒）
      LDI     M10500  ; ON为8:00 OFF为7:50
      ANDD>=  D11605 K75000  ; 当前（秒）
      ANDD<   D11605 K78600  ; 当前（秒）
      ORB
      ANB
      INCP    D11711  ; 21:00-22:00
      MRD
      LD      M10500  ; ON为8:00 OFF为7:50
      ANDD>=  D11605 K79200  ; 当前（秒）
      ANDD<   D11605 K82800  ; 当前（秒）
      LDI     M10500  ; ON为8:00 OFF为7:50
      ANDD>=  D11605 K78600  ; 当前（秒）
      ANDD<   D11605 K82200  ; 当前（秒）
      ORB
      ANB
      INCP    D11712  ; 22:00-23:00
      MRD
      LD      M10500  ; ON为8:00 OFF为7:50
      ANDD>=  D11605 K82800  ; 当前（秒）
      ANDD<   D11605 K86399  ; 当前（秒）
      LDI     M10500  ; ON为8:00 OFF为7:50
      ANDD>=  D11605 K82200  ; 当前（秒）
      ANDD<   D11605 K85800  ; 当前（秒）
      ORB
      ANB
      INCP    D11713  ; 23:00-24:00
      MPP
      LD      M10500  ; ON为8:00 OFF为7:50
      ANDD>=  D11605 K5400  ; 当前（秒）
      ANDD<   D11605 K9000  ; 当前（秒）
      LDI     M10500  ; ON为8:00 OFF为7:50
      ANDD>=  D11605 K4800  ; 当前（秒）
      ANDD<   D11605 K8400  ; 当前（秒）
      ORB
      ANB
      INCP    D11714  ; 1:30-2:30
2306  LD      M2
      MPS
      LD      M10500  ; ON为8:00 OFF为7:50
      ANDD>=  D11605 K9000  ; 当前（秒）
      ANDD<   D11605 K12600  ; 当前（秒）
      LDI     M10500  ; ON为8:00 OFF为7:50
      ANDD>=  D11605 K8400  ; 当前（秒）
      ANDD<   D11605 K12000  ; 当前（秒）
      ORB
      ANB
      INCP    D11715  ; 2:30-3:30
      MRD
      LD      M10500  ; ON为8:00 OFF为7:50
      ANDD>=  D11605 K12600  ; 当前（秒）
      ANDD<   D11605 K16200  ; 当前（秒）
      LDI     M10500  ; ON为8:00 OFF为7:50
      ANDD>=  D11605 K12000  ; 当前（秒）
      ANDD<   D11605 K15600  ; 当前（秒）
      ORB
      ANB
      INCP    D11716  ; 3:30-4:30
      MRD
      LD      M10500  ; ON为8:00 OFF为7:50
      ANDD>=  D11605 K16200  ; 当前（秒）
      ANDD<   D11605 K19800  ; 当前（秒）
      LDI     M10500  ; ON为8:00 OFF为7:50
      ANDD>=  D11605 K15600  ; 当前（秒）
      ANDD<   D11605 K19200  ; 当前（秒）
      ORB
      ANB
      INCP    D11717  ; 4:30-5:30
      MRD
      LD      M10500  ; ON为8:00 OFF为7:50
      ANDD>=  D11605 K21600  ; 当前（秒）
      ANDD<   D11605 K25200  ; 当前（秒）
      LDI     M10500  ; ON为8:00 OFF为7:50
      ANDD>=  D11605 K21000  ; 当前（秒）
      ANDD<   D11605 K24600  ; 当前（秒）
      ORB
      ANB
      INCP    D11718  ; 6:00-7:00
      MPP
      LD      M10500  ; ON为8:00 OFF为7:50
      ANDD>=  D11605 K25200  ; 当前（秒）
      ANDD<   D11605 K28800  ; 当前（秒）
      LDI     M10500  ; ON为8:00 OFF为7:50
      ANDD>=  D11605 K24600  ; 当前（秒）
      ANDD<   D11605 K28200  ; 当前（秒）
      ORB
      ANB
      INCP    D11719  ; 7:00-8:00
2422  LD      M10100
      WSFLP   D11700 D11800 K8 K1
      WSFLP   D11701 D11810 K8 K1
      WSFLP   D11702 D11820 K8 K1
      WSFLP   D11703 D11830 K8 K1
      WSFLP   D11704 D11840 K8 K1
2448  LD      M10100
      WSFLP   D11705 D11850 K8 K1
      WSFLP   D11706 D11860 K8 K1
      WSFLP   D11707 D11870 K8 K1
      WSFLP   D11708 D11880 K8 K1
      WSFLP   D11709 D11890 K8 K1
2474  LD      M10100
      WSFLP   D11710 D11900 K8 K1
      WSFLP   D11711 D11910 K8 K1
      WSFLP   D11712 D11920 K8 K1
      WSFLP   D11713 D11930 K8 K1
      WSFLP   D11714 D11940 K8 K1
2500  LD      M10100
      WSFLP   D11715 D11950 K8 K1
      WSFLP   D11716 D11960 K8 K1
      WSFLP   D11717 D11970 K8 K1
      WSFLP   D11718 D11980 K8 K1
      WSFLP   D11719 D11990 K8 K1
      FMOV    K0 D11700 K20
2530  END
END_PROGRAM

PROGRAM 易损件
0     LD      M7090  ; M7090
      ?OP4C0E K30000 D8150 K20
6     LD      M7091  ; M7091
      ?OP4C0E K3000000 D8150 K20
12    LD      M7092  ; M7092
      FMOV    K0 D8100 K50
      FMOV    K0 D8500 K200
21    LD      M7093  ; M7093
      MOVP    K149 D30  ; 人机控制页
      FMOV    K0 D8200 K200
28    LD      SM400  ; 始终ON
      DMOVP   K665877 D8002
      DMOVP   K666412 D8006
      MOV     K100 D8040
37    LDI     M2
      MPS
      AND     M7000  ; M7000
      DINCP   D8100
      ANDD>=  D8100 D8150
      SET     M5180  ; 易损件1保养周期到！
      MRD
      AND     M7001  ; M7001
      DINCP   D8102
      ANDD>=  D8102 D8152
      SET     M5181  ; 易损件2保养周期到！
      MRD
      AND     M7002  ; M7002
      DINCP   D8104
      ANDD>=  D8104 D8154
      SET     M5182  ; 易损件3保养周期到！
      MRD
      AND     M7003  ; M7003
      DINCP   D8106
      ANDD>=  D8106 D8156
      SET     M5183  ; 易损件4保养周期到！
      MRD
      AND     M7004  ; M7004
      DINCP   D8108
      ANDD>=  D8108 D8158
      SET     M5184  ; 易损件5保养周期到！
      MRD
      AND     M7005  ; M7005
      DINCP   D8110
      ANDD>=  D8110 D8160
      SET     M5185  ; 易损件6保养周期到！
      MRD
      AND     M7006  ; M7006
      DINCP   D8112
      ANDD>=  D8112 D8162
      SET     M5186  ; 易损件7保养周期到！
      MRD
      AND     M7007  ; M7007
      DINCP   D8114
      ANDD>=  D8114 D8164
      SET     M5187  ; 易损件8保养周期到！
      MRD
      AND     M7008  ; M7008
      DINCP   D8116
      ANDD>=  D8116 D8166
      SET     M5188  ; 易损件9保养周期到！
      MPP
      AND     M7009  ; M7009
      DINCP   D8118
      ANDD>=  D8118 D8168
      SET     M5189  ; 易损件10保养周期到！
118   LDI     M2
      MPS
      AND     M7010  ; M7010
      DINCP   D8120
      ANDD>=  D8120 D8170
      SET     M5190  ; 易损件11保养周期到！
      MRD
      AND     M7011  ; M7011
      DINCP   D8122
      ANDD>=  D8122 D8172
      SET     M5191  ; 易损件12保养周期到！
      MRD
      AND     M7012  ; M7012
      DINCP   D8124
      ANDD>=  D8124 D8174
      SET     M5192  ; 易损件13保养周期到！
      MRD
      AND     M7013  ; M7013
      DINCP   D8126
      ANDD>=  D8126 D8176
      SET     M5193  ; 易损件14保养周期到！
      MRD
      AND     M7014  ; M7014
      DINCP   D8128
      ANDD>=  D8128 D8178
      SET     M5194  ; 易损件15保养周期到！
      MRD
      AND     M7015  ; M7015
      DINCP   D8130
      ANDD>=  D8130 D8180
      SET     M5195  ; 易损件16保养周期到！
      MRD
      AND     M7016  ; M7016
      DINCP   D8132
      ANDD>=  D8132 D8182
      SET     M5196  ; 易损件17保养周期到！
      MRD
      AND     M7017  ; M7017
      DINCP   D8134
      ANDD>=  D8134 D8184
      SET     M5197  ; 易损件18保养周期到！
      MRD
      AND     M7018  ; M7018
      DINCP   D8136
      ANDD>=  D8136 D8186
      SET     M5198  ; 易损件19保养周期到！
      MPP
      AND     M7019  ; M7019
      DINCP   D8138
      ANDD>=  D8138 D8188
      SET     M5199  ; 易损件20保养周期到！
199   LDD<>   K0 K5M7100  ; M7100
      OUTH    T245 K50
207   LD      SM410
      +       D8040 D8044 D8050Z6
      INC     Z6
      INC     D8044
      AND>=   Z6 K50
      MOV     K0 Z6
      MOV     K1 D8044
220   LD>=    D8042 K1
      OUT     M7000  ; M7000
224   LD>=    D8042 K2
      OUT     M7001  ; M7001
228   LD>=    D8042 K3
      OUT     M7002  ; M7002
232   LD>=    D8042 K4
      OUT     M7003  ; M7003
236   LD>=    D8042 K5
      OUT     M7004  ; M7004
240   LD>=    D8042 K6
      OUT     M7005  ; M7005
244   LD>=    D8042 K7
      OUT     M7006  ; M7006
248   LD>=    D8042 K8
      OUT     M7007  ; M7007
252   LD>=    D8042 K9
      OUT     M7008  ; M7008
256   LD>=    D8042 K10
      OUT     M7009  ; M7009
260   LD>=    D8042 K11
      OUT     M7010  ; M7010
264   LD>=    D8042 K12
      OUT     M7011  ; M7011
268   LD>=    D8042 K13
      OUT     M7012  ; M7012
272   LD>=    D8042 K14
      OUT     M7013  ; M7013
276   LD>=    D8042 K15
      OUT     M7014  ; M7014
280   LD>=    D8042 K16
      OUT     M7015  ; M7015
284   LD>=    D8042 K17
      OUT     M7016  ; M7016
288   LD>=    D8042 K18
      OUT     M7017  ; M7017
292   LD>=    D8042 K19
      OUT     M7018  ; M7018
296   LD>=    D8042 K20
      OUT     M7019  ; M7019
300   LDD<>   K0 K8M7100  ; M7100
      ORD<>   K0 K8M7130  ; M7130
      ORD<>   K0 K5M7160  ; M7160
      ORD<>   K0 K5M7180  ; M7180
      ORD=    D8000 D8002
      ORD=    D8004 D8006
      MPS
      AND     SM402
      MOVP    K100 D8040
      MPP
      CALL    P2
329   LDP     M7169  ; M7169
      FF      M7170  ; M7170
332   LD      M7170  ; M7170
      DATEWRP D8190
335   LD<>    K149 D10
      RST     M7170  ; M7170
      DATERD  D8190
341   FEND
      P2
343   LDD=    D8000 D8002
      MOV     D8050 D30
      DMOV    K0 D8000
351   LDD=    D8004 D8006
      MOV     K149 D30
      DMOV    K0 D8004
359   LD      M7100  ; M7100
      AND     T245
      AND     M7000  ; M7000
      OUT     M7180  ; M7180
      DSFLP   D8500 K10
      DSFLP   D8500 K10
      DMOV    D8100 D8500
      MOV     K0 Z7
373   LD      M7101  ; M7101
      AND     T245
      AND     M7001  ; M7001
      OUT     M7181  ; M7181
      DSFLP   D8510 K10
      DSFLP   D8510 K10
      DMOV    D8102 D8510
      MOV     K15 Z7
387   LD      M7102  ; M7102
      AND     T245
      AND     M7002  ; M7002
      OUT     M7182  ; M7182
      DSFLP   D8520 K10
      DSFLP   D8520 K10
      DMOV    D8104 D8520
      MOV     K30 Z7
401   LD      M7103  ; M7103
      AND     T245
      AND     M7003  ; M7003
      OUT     M7183  ; M7183
      DSFLP   D8530 K10
      DSFLP   D8530 K10
      DMOV    D8106 D8530
      MOV     K45 Z7
415   LD      M7104  ; M7104
      AND     T245
      AND     M7004  ; M7004
      OUT     M7184  ; M7184
      DSFLP   D8540 K10
      DSFLP   D8540 K10
      DMOV    D8108 D8540
      MOV     K60 Z7
429   LD      M7105  ; M7105
      AND     T245
      AND     M7005  ; M7005
      OUT     M7185  ; M7185
      DSFLP   D8550 K10
      DSFLP   D8550 K10
      DMOV    D8110 D8550
      MOV     K75 Z7
443   LD      M7106  ; M7106
      AND     T245
      AND     M7006  ; M7006
      OUT     M7186  ; M7186
      DSFLP   D8560 K10
      DSFLP   D8560 K10
      DMOV    D8112 D8560
      MOV     K90 Z7
457   LD      M7107  ; M7107
      AND     T245
      AND     M7007  ; M7007
      OUT     M7187  ; M7187
      DSFLP   D8570 K10
      DSFLP   D8570 K10
      DMOV    D8114 D8570
      MOV     K105 Z7
471   LD      M7108  ; M7108
      AND     T245
      AND     M7008  ; M7008
      OUT     M7188  ; M7188
      DSFLP   D8580 K10
      DSFLP   D8580 K10
      DMOV    D8116 D8580
      MOV     K120 Z7
485   LD      M7109  ; M7109
      AND     T245
      AND     M7009  ; M7009
      OUT     M7189  ; M7189
      DSFLP   D8590 K10
      DSFLP   D8590 K10
      DMOV    D8118 D8590
      MOV     K135 Z7
499   LD      M7110  ; M7110
      AND     T245
      AND     M7010  ; M7010
      OUT     M7190  ; M7190
      DSFLP   D8600 K10
      DSFLP   D8600 K10
      DMOV    D8120 D8600
      MOV     K150 Z7
513   LD      M7111  ; M7111
      AND     T245
      AND     M7011  ; M7011
      OUT     M7191  ; M7191
      DSFLP   D8610 K10
      DSFLP   D8610 K10
      DMOV    D8122 D8610
      MOV     K165 Z7
527   LD      M7112  ; M7112
      AND     T245
      AND     M7012  ; M7012
      OUT     M7192  ; M7192
      DSFLP   D8620 K10
      DSFLP   D8620 K10
      DMOV    D8124 D8620
      MOV     K180 Z7
541   LD      M7113  ; M7113
      AND     T245
      AND     M7013  ; M7013
      OUT     M7193  ; M7193
      DSFLP   D8630 K10
      DSFLP   D8630 K10
      DMOV    D8126 D8630
      MOV     K195 Z7
555   LD      M7114  ; M7114
      AND     T245
      AND     M7014  ; M7014
      OUT     M7194  ; M7194
      DSFLP   D8640 K10
      DSFLP   D8640 K10
      DMOV    D8128 D8640
      MOV     K210 Z7
569   LD      M7115  ; M7115
      AND     T245
      AND     M7015  ; M7015
      OUT     M7195  ; M7195
      DSFLP   D8650 K10
      DSFLP   D8650 K10
      DMOV    D8130 D8650
      MOV     K225 Z7
583   LD      M7116  ; M7116
      AND     T245
      AND     M7016  ; M7016
      OUT     M7196  ; M7196
      DSFLP   D8660 K10
      DSFLP   D8660 K10
      DMOV    D8132 D8660
      MOV     K240 Z7
597   LD      M7117  ; M7117
      AND     T245
      AND     M7017  ; M7017
      OUT     M7197  ; M7197
      DSFLP   D8670 K10
      DSFLP   D8670 K10
      DMOV    D8134 D8670
      MOV     K255 Z7
611   LD      M7118  ; M7118
      AND     T245
      AND     M7018  ; M7018
      OUT     M7198  ; M7198
      DSFLP   D8680 K10
      DSFLP   D8680 K10
      DMOV    D8136 D8680
      MOV     K270 Z7
625   LD      M7119  ; M7119
      AND     T245
      AND     M7019  ; M7019
      OUT     M7199  ; M7199
      DSFLP   D8690 K10
      DSFLP   D8690 K10
      DMOV    D8138 D8690
      MOV     K285 Z7
639   LDD<>   K0 K5M7180  ; M7180
      DSFLP   D8200Z7 K5
      MOV     D8190 D8200Z7
      DSFLP   D8205Z7 K5
      MOV     D8191 D8205Z7
      DSFLP   D8210Z7 K5
      MOVP    D8192 D8210Z7  ; 当前-日
658   LDF     M7180  ; M7180
      FMOVP   K0 D8100 K2
663   LDF     M7181  ; M7181
      FMOVP   K0 D8102 K2
668   LDF     M7182  ; M7182
      FMOVP   K0 D8104 K2
673   LDF     M7183  ; M7183
      FMOVP   K0 D8106 K2
678   LDF     M7184  ; M7184
      FMOVP   K0 D8108 K2
683   LDF     M7185  ; M7185
      FMOVP   K0 D8110 K2
688   LDF     M7186  ; M7186
      FMOVP   K0 D8112 K2
693   LDF     M7187  ; M7187
      FMOVP   K0 D8114 K2
698   LDF     M7188  ; M7188
      FMOVP   K0 D8116 K2
703   LDF     M7189  ; M7189
      FMOVP   K0 D8118 K2
708   LDF     M7190  ; M7190
      FMOVP   K0 D8120 K2
713   LDF     M7191  ; M7191
      FMOVP   K0 D8122 K2
718   LDF     M7192  ; M7192
      FMOVP   K0 D8124 K2
723   LDF     M7193  ; M7193
      FMOVP   K0 D8126 K2
728   LDF     M7194  ; M7194
      FMOVP   K0 D8128 K2
733   LDF     M7195  ; M7195
      FMOVP   K0 D8130 K2
738   LDF     M7196  ; M7196
      FMOVP   K0 D8132 K2
743   LDF     M7197  ; M7197
      FMOVP   K0 D8134 K2
748   LDF     M7198  ; M7198
      FMOVP   K0 D8136 K2
753   LDF     M7199  ; M7199
      FMOVP   K0 D8138 K2
758   LD      M7120  ; M7120
      MOVP    D8050 D30
761   LD      M7121  ; M7121
      AND>    D8042 K5
      MOVP    D8051 D30
767   LD      M7122  ; M7122
      AND>    D8042 K10
      MOVP    D8052 D30
773   LD      M7123  ; M7123
      AND>    D8042 K15
      MOVP    D8053 D30
779   LD      M7124  ; M7124
      AND     M7000  ; M7000
      OR      M7180  ; M7180
      MOVP    D8054 D30
784   LD      M7125  ; M7125
      AND     M7001  ; M7001
      OR      M7181  ; M7181
      MOVP    D8055 D30
789   LD      M7126  ; M7126
      AND     M7002  ; M7002
      OR      M7182  ; M7182
      MOVP    D8056 D30
794   LD      M7127  ; M7127
      AND     M7003  ; M7003
      OR      M7183  ; M7183
      MOVP    D8057 D30
799   LD      M7128  ; M7128
      AND     M7004  ; M7004
      OR      M7184  ; M7184
      MOVP    D8058 D30
804   LD      M7129  ; M7129
      AND     M7005  ; M7005
      OR      M7185  ; M7185
      MOVP    D8059 D30
809   LD      M7130  ; M7130
      AND     M7006  ; M7006
      OR      M7186  ; M7186
      MOVP    D8060 D30
814   LD      M7131  ; M7131
      AND     M7007  ; M7007
      OR      M7187  ; M7187
      MOVP    D8061 D30
819   LD      M7132  ; M7132
      AND     M7008  ; M7008
      OR      M7188  ; M7188
      MOVP    D8062 D30
824   LD      M7133  ; M7133
      AND     M7009  ; M7009
      OR      M7189  ; M7189
      MOVP    D8063 D30
829   LD      M7134  ; M7134
      AND     M7010  ; M7010
      OR      M7190  ; M7190
      MOVP    D8064 D30
834   LD      M7135  ; M7135
      AND     M7011  ; M7011
      OR      M7191  ; M7191
      MOVP    D8065 D30
839   LD      M7136  ; M7136
      AND     M7012  ; M7012
      OR      M7192  ; M7192
      MOVP    D8066 D30
844   LD      M7137  ; M7137
      AND     M7013  ; M7013
      OR      M7193  ; M7193
      MOVP    D8067 D30
849   LD      M7138  ; M7138
      AND     M7014  ; M7014
      OR      M7194  ; M7194
      MOVP    D8068 D30
854   LD      M7139  ; M7139
      AND     M7015  ; M7015
      OR      M7195  ; M7195
      MOVP    D8069 D30
859   LD      M7140  ; M7140
      AND     M7016  ; M7016
      OR      M7196  ; M7196
      MOVP    D8070 D30
864   LD      M7141  ; M7141
      AND     M7017  ; M7017
      OR      M7197  ; M7197
      MOVP    D8071 D30
869   LD      M7142  ; M7142
      AND     M7018  ; M7018
      OR      M7198  ; M7198
      MOVP    D8072 D30
874   LD      M7143  ; M7143
      AND     M7019  ; M7019
      OR      M7199  ; M7199
      MOVP    D8073 D30
879   LD      M7144  ; M7144
      MOVP    D8074 D30
882   LD      M7145  ; M7145
      MOVP    D8075 D30
885   LD      M7146  ; M7146
      MOVP    D8076 D30
888   LD      M7147  ; M7147
      MOVP    D8077 D30
891   LD      M7148  ; M7148
      MOVP    D8078 D30
894   LD      M7149  ; M7149
      MOVP    D8079 D30
897   LD      M7150  ; M7150
      MOVP    D8080 D30
900   LD      M7151  ; M7151
      MOVP    D8081 D30
903   LD      M7152  ; M7152
      MOVP    D8082 D30
906   LD      M7153  ; M7153
      MOVP    D8083 D30
909   LD      M7154  ; M7154
      MOVP    D8084 D30
912   LD      M7155  ; M7155
      MOVP    D8085 D30
915   LD      M7156  ; M7156
      MOVP    D8086 D30
918   LD      M7157  ; M7157
      MOVP    D8087 D30
921   LD      M7158  ; M7158
      MOVP    D8088 D30
924   LD      M7159  ; M7159
      MOVP    D8089 D30
927   LD      M7160  ; M7160
      MOVP    D8090 D30
930   LD      M7161  ; M7161
      MOVP    D8091 D30
933   LD      M7162  ; M7162
      MOVP    D8092 D30
936   LD      M7163  ; M7163
      MOVP    D8093 D30
939   LD      M7164  ; M7164
      MOVP    D8094 D30
942   LD      M7165  ; M7165
      MOVP    D8095 D30
945   LD      M7166  ; M7166
      MOVP    D8096 D30
948   LD      M7167  ; M7167
      MOVP    D8097 D30
951   LD      M7168  ; M7168
      MOVP    D8098 D30
954   RET
955   END
END_PROGRAM

PROGRAM 短路管制
0     LD      SM400  ; 始终ON
      MPS
      ?OP402611 D11600 D3760 K7  ; 当前时间（时）
      ?OP402811 D11600 D3770 K7
      OUT     M4200  ; 白班时间段
      INV
      OUT     M4201  ; 夜班时间段
      MRD
      ANDP    L400
      FF      L401  ; 白班
      MRD
      ANDP    L402
      FF      L403  ; 夜班
      MPP
      LDI     L401  ; 白班
      AND     M4200  ; 白班时间段
      LDI     L403  ; 夜班
      AND     M4201  ; 夜班时间段
      ORB
      ANB
      OUT     M4209  ; 在时段内
29    LD      SM400  ; 始终ON
      MPS
      AND=    D10 K95
      LDD=    D3800 D3802  ; 输入密码 / 设置密码
      ORD=    D3800 K666412  ; 输入密码
      ANB
      MOVP    K96 D30  ; 人机控制页
      DMOV    K0 D3800
      MPP
      *       D3812 K360 D3814  ; 自动清零（小时） / 自动清零（秒）
      *       D3816 K600 D3818  ; 暂时清零次数 / 暂时清零秒数
54    LD      SM400  ; 始终ON
      MPS
      AND     M20  ; 手动状态
      MOV     K0 D3830  ; 初始化不计数
      MPP
      AND     M2
      AND<    D3830 K20  ; 初始化不计数
      INCP    D3830
66    LD      M4209  ; 在时段内
      MPS
      ANI     L590  ; 试机开关
      AND     M4215  ; 短路PLS
      AND<>   D3810 K0  ; 短路数设置
      AND>=   D3830 K3  ; 初始化不计数
      INCP    D3820  ; 短路计数、
      MRD
      AND>=   D3820 D3810  ; 短路计数、 / 短路数设置
      AND<>   D3810 K0  ; 短路数设置
      OUT     M4216  ; 短路超上限
      MRD
      ANI     L590  ; 试机开关
      AND     M23  ; 启动
      AND     SM412
      MPS
      AND     M4216  ; 短路超上限
      INCP    D3822  ; 临时生产计时
      INCP    D3824  ; 临时生产10分钟
      MPP
      ANI     M4216  ; 短路超上限
      INCP    D3826  ; 清除周期计时
      MRD
      AND>=   D3822 D3818  ; 临时生产计时 / 暂时清零秒数
      OUT     M4217  ; 临时生产次数超
      MRD
      AND>=   D3824 K600  ; 临时生产10分钟
      OUT     M4218  ; 10分钟停机一次
      MPP
      AND>=   D3826 D3814  ; 清除周期计时 / 自动清零（秒）
      ANI     M4216  ; 短路超上限
      FMOV    K0 D3820 K10
119   LD      M4216  ; 短路超上限
      ANI     M5327  ; 短路不良超上限，报警停机！
      OUT     M5326  ; 短路不良超上限，可临时生产！
122   LD      M4217  ; 临时生产次数超
      OR      M4218  ; 10分钟停机一次
      ORP     M4216  ; 短路超上限
      RST     D3824  ; 临时生产10分钟
      SET     M5327  ; 短路不良超上限，报警停机！
      MPS
      MEP
      MOVP    K97 D30
      MPP
      RST     M23  ; 启动
      SET     M24  ; 停止
135   LDP     M4219  ; 短路报警清除
      AND     M4216  ; 短路超上限
      PLS     M4220
139   LD      M1  ; 报警清除
      OR      M4220
      RST     M5327  ; 短路不良超上限，报警停机！
142   LD      M4220
      DMOV    K0 D3800
      MOV     K97 D30
      FMOV    K0 D3820 K10
      WSFLP   D8192 D3700 K20 K1  ; 当前-日
      WSFLP   D8193 D3720 K20 K1  ; 当前-时
      WSFLP   D8194 D3740 K20 K1  ; 当前-分
167   END
END_PROGRAM

PROGRAM 试机品点检
; 点检项目设定
8     LD      SM400  ; 始终ON
      MOV     K1 D7500  ; 点检项目1
      MOV     K2 D7501  ; 点检项目2
      MOV     K3 D7502  ; 点检项目3
      MOV     K0 D7503  ; 点检项目4
      MOV     K0 D7504  ; 点检项目5
      MOV     K0 D7505  ; 点检项目6
      MOV     K0 D7506
23    LD      L10  ; 点检时间到
      MPS
      AND     M23  ; 启动
      OUT     T10 K900
      MRD
      AND     T10
      PLS     M7  ; 单动脉冲
      MOVP    K93 D30  ; 人机控制页
      SET     M7500  ; 点检项目不通过
      MRD
      ANI     L590  ; 试机开关
      OUT     M5328  ; 点检时间到，请开始点检
      MPP
      AND     L590  ; 试机开关
      OUT     M5329  ; 点检时间到，点检中
43    LD      SM400  ; 始终ON
      MPS
      ?OP402611 D11600 D7200 K7  ; 当前时间（时）
      ?OP402811 D11600 D7210 K7
      OUT     M7600  ; 上午
      MRD
      ?OP402611 D11600 D7210 K7
      ?OP402811 D11600 D7220 K7
      OUT     M7601  ; 下午
      MRD
      ?OP402611 D11600 D7220 K7
      ?OP402811 D11600 D7230 K7
      OUT     M7602  ; 加班
      MRD
      ?OP402611 D11600 D7230 K7
      OUT     M7603  ; 上半夜
      MRD
      ?OP402611 D11600 D7240 K7
      ?OP402811 D11600 D7250 K7
      OUT     M7604  ; 下半夜
      MRD
      ?OP402611 D11600 D7250 K7
      ?OP402811 D11600 D7200 K7
      OUT     M7605  ; 加班
      MPP
      AND<>   K2M7600 D7509  ; 上午
      SET     L10  ; 点检时间到
      AND     L10  ; 点检时间到
      MOV     K2M7600 D7509
109   LDI     L590  ; 试机开关
      LD      M7500  ; 点检项目不通过
      AND     M7501  ; 重新点检
      ORB
      FMOVP   K0 D7470 K10  ; 点检项目1显示数
      RST     M7500  ; 点检项目不通过
118   LD>=    D7470 D7460  ; 点检项目1显示数 / 点检项目1设置数
      OUT     M7510  ; 点检项目1
122   LD>=    D7471 D7461  ; 点检项目2显示数 / 点检项目2设置数
      OUT     M7511  ; 点检项目2
126   LD>=    D7472 D7462  ; 点检项目3显示数 / 点检项目3设置数
      OUT     M7512  ; 点检项目3
130   LD>=    D7473 D7463  ; 点检项目4显示数 / 点检项目4设置数
      OUT     M7513  ; 点检项目4
134   LD>=    D7474 D7464  ; 点检项目5显示数 / 点检项目5设置数
      OUT     M7514  ; 点检项目5
138   LD>=    D7475 D7465  ; 点检项目6显示数 / 点检项目6设置数
      OUT     M7515  ; 点检项目6
142   LD>=    D7476 D7466  ; 点检项目7显示数 / 点检项目7设置数
      OUT     M7516  ; 点检项目7
146   LD      L590  ; 试机开关
      AND     M7510  ; 点检项目1
      AND     M7511  ; 点检项目2
      AND     M7512  ; 点检项目3
      AND     M7513  ; 点检项目4
      AND     M7514  ; 点检项目5
      AND     M7515  ; 点检项目6
      AND     M7516  ; 点检项目7
      OUT     M7519  ; 点检通过
155   LDP     M7519  ; 点检通过
      ORP     M7502  ; 点检确认（隐藏按钮）
      RST     L10  ; 点检时间到
      RST     M7500  ; 点检项目不通过
      RST     L590  ; 试机开关
      WSFLP   D11599 D7300 K30 K1
      WSFLP   D11600 D7330 K30 K1
      WSFLP   D11601 D7360 K30 K1  ; 当前时间（分）
175   END
END_PROGRAM

PROGRAM 11#模块轴11
0     LDP     T175  ; 11轴
      LD      M20  ; 手动状态
      ANDP    M2201  ; 11#复原
      ORB
      LD      T175  ; 11轴
      ANDP    M20  ; 手动状态
      ORF     M20  ; 手动状态
      AND     M2900  ; 11#在原点位置
      ORB
      ORF     M2200  ; 11#伺服ON
      AND     B60F  ; 11#复原中
      BKRST   B600 K10  ; 11#复原开始
      SET     B600  ; 11#复原开始
15    LD=     K0 K3B600  ; 11#复原开始
      OUT     B60F  ; 11#复原中
      INV
      OUT     M2601  ; 11#轴复原中
21    LD      B600  ; 11#复原开始
      SET     B601
      RST     B600  ; 11#复原开始
24    LD      B601
      RST     B600  ; 11#复原开始
      MOV     K9001 D1602
      MOV     K0 U6\G1521
      ZP.PSTRT1 "U6" D1600 M2215  ; 11#原点完成
      SET     B602
42    LD      B602
      RST     B601
      AND     M2215  ; 11#原点完成
      MOV     K1 U3\G1521
      SET     B603
50    LD      B603
      RST     B602
      OUT     T178 K2
      AND     T178
      SET     B604
58    LD      B604
      RST     B603
      PLS     M2214  ; 11#回原点定位
      ANI     M2214  ; 11#回原点定位
      SET     B605
64    LD      B605
      RST     B604
      AND     M2217  ; 11#轴定位完成
      SET     B606
68    LD      B606
      RST     B605
      DMOV    K0 U6\G1506
      MOV     K9003 U6\G1500
      MPS
      ANDP    B606
      SET     Y70  ; 3#轴1定位启动
      MPP
      RST     B606
84    LD      Y70  ; 3#轴1定位启动
      OUT     T179 K2
      AND     T179
      RST     Y70  ; 3#轴1定位启动
91    LD      M20  ; 手动状态
      AND     SM400  ; 始终ON
      MPS
      ANDP    M2202  ; 11#手动折料
      SET     M2210  ; 11#折料
      MRD
      ANDP    M2300  ; 11#位置1（手动）
      ANDD<>  D1200 D2400  ; 11#当前值 / 11#轴位置1
      SET     M2330  ; 11#位置1
      MRD
      ANDP    M2301  ; 11#位置2（手动）
      ANDD<>  D1200 D2402  ; 11#当前值 / 11#轴位置2
      SET     M2331  ; 11#位置2
      MRD
      ANDP    M2302  ; 11#位置3（手动）
      ANDD<>  D1200 D2404  ; 11#当前值 / 11#轴位置3
      SET     M2332  ; 11#位置3
      MRD
      ANDP    M1903  ; 10#位置4（手动）
      ANDD<>  D1200 D2406  ; 11#当前值 / 11#轴位置4
      SET     M2333  ; 11#位置4
      MRD
      ANDP    M2304  ; 11#位置5（手动）
      ANDD<>  D1200 D2408  ; 11#当前值 / 11#轴位置5
      SET     M2334  ; 11#位置5
      MRD
      ANDP    M2305  ; 11#位置6（手动）
      ANDD<>  D1200 D2410  ; 11#当前值 / 11#轴位置6
      SET     M2335  ; 11#位置6
      MRD
      ANDP    M2306  ; 11#位置7（手动）
      ANDD<>  D1200 D2412  ; 11#当前值 / 11#轴位置7
      SET     M2336  ; 11#位置7
      MRD
      ANDP    M2307  ; 11#位置8（手动）
      ANDD<>  D1200 D2414  ; 11#当前值 / 11#轴位置8
      SET     M2337  ; 11#位置8
      MRD
      ANDP    M2308  ; 11#位置9（手动）
      ANDD<>  D1200 D2416  ; 11#当前值 / 11#轴位置9
      SET     M2338  ; 11#位置9
      MPP
      ANDP    M2309  ; 11#位置10（手动）
      ANDD<>  D1200 D2418  ; 11#当前值 / 11#轴位置10
      SET     M2339  ; 11#位置10
156   LDI     M2611  ; 12#轴复原中
      AND     SM400  ; 始终ON
      MPS
      ANDP    M2210  ; 11#折料
      *       D1210 D1208 D1218  ; 11#每转脉冲 / 11#次数 / 11#折料位置
      MRD
      ANDP    M2330  ; 11#位置1
      DMOV    D2400 D1610  ; 11#位置
      MRD
      ANDP    M2331  ; 11#位置2
      DMOV    D2402 D1610
      MRD
      ANDP    M2332  ; 11#位置3
      DMOV    D2404 D1610
      MRD
      ANDP    M2333  ; 11#位置4
      DMOV    D2406 D1610
      MRD
      ANDP    M2334  ; 11#位置5
      DMOV    D2408 D1610
      MRD
      ANDP    M2335  ; 11#位置6
      DMOV    D2410 D1610
      MRD
      ANDP    M2336  ; 11#位置7
      DMOV    D2412 D1610
      MRD
      ANDP    M2337  ; 11#位置8
      DMOV    D2414 D1610
      MRD
      ANDP    M2338  ; 11#位置9
      DMOV    D2416 D1610
      MPP
      ANDP    M2339  ; 11#位置10
      DMOV    D2418 D1610
203   LD      SM400  ; 始终ON
      MPS
      AND     M20  ; 手动状态
      DMOV    D1204 D1612  ; 11#手动频率 / 11#速度
      MRD
      ANI     M20  ; 手动状态
      DMOV    D1206 D1612  ; 11#自动速度
      MPP
      DMOV    D1612 U6\G2004
      DMOV    D1202 U6\G2006  ; 11#原点位置
      DMOV    D1612 U6\G2014
      DMOV    D1218 U6\G2016
      DMOV    D1612 U6\G2024
      DMOV    D1610 U6\G2026
237   LD      M2214  ; 11#回原点定位
      OR      M2210  ; 11#折料
      OR<>    K0 K4M2330  ; 11#位置1
      MPS
      AND     M2214  ; 11#回原点定位
      MOVP    K1 D1608  ; 11#模式
      MRD
      AND     M2210  ; 11#折料
      MOVP    K2 D1608
      MRD
      AND<>   K0 K4M2330  ; 11#位置1
      MOVP    K3 D1608
      MRD
      MEP
      ZP.PSTRT1 U6 D1606 M2217  ; 11#轴定位
      MPP
      AND     M2217  ; 11#轴定位完成
      BKRST   M2330 K20
      BKRST   M2210 K5
274   LDD=    D1200 D2400  ; 11#当前值 / 11#轴位置1
      OUT     M2900  ; 11#在原点位置
278   LDD=    D1200 D2400  ; 11#当前值 / 11#轴位置1
      OUT     M2901  ; 11#在位置1
282   LDD=    D1200 D2402  ; 11#当前值 / 11#轴位置2
      OUT     M2902  ; 11#在位置2
286   LDD=    D1200 D2404  ; 11#当前值 / 11#轴位置3
      OUT     M2903  ; 11#在位置3
290   LDD=    D1200 D2406  ; 11#当前值 / 11#轴位置4
      OUT     M2904  ; 11#在位置4
294   LDD=    D1200 D2408  ; 11#当前值 / 11#轴位置5
      OUT     M2905  ; 11#在位置5
298   LDD=    D1200 D2410  ; 11#当前值 / 11#轴位置6
      OUT     M2906  ; 11#在位置6
302   LDD=    D1200 D2412  ; 11#当前值 / 11#轴位置7
      OUT     M2907  ; 11#在位置7
306   LDD=    D1200 D2414  ; 11#当前值 / 11#轴位置8
      OUT     M2908  ; 11#在位置8
310   LDD=    D1200 D2416  ; 11#当前值 / 11#轴位置9
      OUT     M2909  ; 11#在位置9
314   LDD=    D1200 D2418  ; 11#当前值 / 11#轴位置10
      OUT     M2910  ; 11#在位置10
318   LD      M20  ; 手动状态
      MPS
      LD      M2205  ; 11#JOG+
      OR      M2206  ; 11#JOG-
      ANB
      ANI     X6C  ; 11#忙
      SET     M2207  ; 11#JOG
      MRD
      ANI     M2205  ; 11#JOG+
      ANI     M2206  ; 11#JOG-
      RST     M2207  ; 11#JOG
      MRD
      AND     M2205  ; 11#JOG+
      AND     M2207  ; 11#JOG
      ANI     Y69  ; 11#反向JOG
      OUT     Y68  ; 11#正向JOG
      MPP
      AND     M2206  ; 11#JOG-
      AND     M2207  ; 11#JOG
      ANI     Y68  ; 11#正向JOG
      OUT     Y69  ; 11#反向JOG
339   END
END_PROGRAM

PROGRAM 12#模块轴12
0     LDP     T185  ; 12轴
      LD      M20  ; 手动状态
      ANDP    M2221  ; 12#复原
      ORB
      LD      T185  ; 12轴
      ANDP    M20  ; 手动状态
      ORF     M20  ; 手动状态
      AND     M2920  ; 12#在原点位置
      ORB
      ORF     M2220  ; 12#伺服ON
      AND     B61F  ; 12#复原中
      BKRST   B610 K10  ; 12#复原开始
      SET     B610  ; 12#复原开始
15    LD=     K0 K3B610  ; 12#复原开始
      OUT     B61F  ; 12#复原中
      INV
      OUT     M2611  ; 12#轴复原中
21    LD      B610  ; 12#复原开始
      SET     B611
      RST     B610  ; 12#复原开始
24    LD      B611
      RST     B610  ; 12#复原开始
      MOV     K9001 D1622
      MOV     K0 U6\G1621
      ZP.PSTRT2 "U6" D1620 M2235  ; 12#原点完成
      SET     B612
42    LD      B612
      RST     B611
      AND     M2235  ; 12#原点完成
      MOV     K1 U3\G1621
      SET     B613
50    LD      B613
      RST     B602
      OUT     T188 K2
      AND     T188
      SET     B614
58    LD      B614
      RST     B613
      PLS     M2234  ; 12#回原点定位
      ANI     M2234  ; 12#回原点定位
      SET     B615
64    LD      B615
      RST     B614
      AND     M2217  ; 11#轴定位完成
      SET     B616
68    LD      B616
      RST     B615
      DMOV    K0 U6\G1606
      MOV     K9003 U6\G1600
      MPS
      ANDP    B616
      SET     Y71  ; 3#轴2定位启动
      MPP
      RST     B616
84    LD      Y71  ; 3#轴2定位启动
      OUT     T189 K2
      AND     T189
      RST     Y71  ; 3#轴2定位启动
91    LD      M20  ; 手动状态
      AND     SM400  ; 始终ON
      MPS
      ANDP    M2222  ; 12#手动折料
      SET     M2230  ; 12#折料
      MRD
      ANDP    M2400  ; 12#位置1（手动）
      ANDD<>  D1220 D2440  ; 12#当前值 / 12#轴位置1
      SET     M2430  ; 12#位置1
      MRD
      ANDP    M2401  ; 12#位置2（手动）
      ANDD<>  D1220 D2442  ; 12#当前值 / 12#轴位置2
      SET     M2431  ; 12#位置2
      MRD
      ANDP    M2402  ; 12#位置3（手动）
      ANDD<>  D1220 D2444  ; 12#当前值 / 12#轴位置3
      SET     M2432  ; 12#位置3
      MRD
      ANDP    M1403  ; 5#位置4（手动）
      ANDD<>  D1220 D2446  ; 12#当前值 / 12#轴位置4
      SET     M2433  ; 12#位置4
      MRD
      ANDP    M2404  ; 12#位置5（手动）
      ANDD<>  D1220 D2448  ; 12#当前值 / 12#轴位置5
      SET     M2434  ; 12#位置5
      MRD
      ANDP    M2405  ; 12#位置6（手动）
      ANDD<>  D1220 D2450  ; 12#当前值 / 12#轴位置6
      SET     M2435  ; 12#位置6
      MRD
      ANDP    M2406  ; 12#位置7（手动）
      ANDD<>  D1220 D2452  ; 12#当前值 / 12#轴位置7
      SET     M2436  ; 12#位置7
      MRD
      ANDP    M2407  ; 12#位置8（手动）
      ANDD<>  D1220 D2454  ; 12#当前值 / 12#轴位置8
      SET     M2437  ; 12#位置8
      MRD
      ANDP    M2408  ; 12#位置9（手动）
      ANDD<>  D1220 D2456  ; 12#当前值 / 12#轴位置9
      SET     M2438  ; 12#位置9
      MPP
      ANDP    M2409  ; 12#位置10（手动）
      ANDD<>  D1220 D2458  ; 12#当前值 / 12#轴位置10
      SET     M2439  ; 12#位置10
156   LDI     M2611  ; 12#轴复原中
      AND     SM400  ; 始终ON
      MPS
      ANDP    M2230  ; 12#折料
      *       D1230 D1228 D1238  ; 12#每转脉冲 / 12#次数 / 12#折料位置
      MRD
      ANDP    M2430  ; 12#位置1
      DMOV    D2440 D1630  ; 12#位置
      MRD
      ANDP    M2431  ; 12#位置2
      DMOV    D2442 D1630
      MRD
      ANDP    M2432  ; 12#位置3
      DMOV    D2444 D1630
      MRD
      ANDP    M2433  ; 12#位置4
      DMOV    D2446 D1630
      MRD
      ANDP    M2434  ; 12#位置5
      DMOV    D2448 D1630
      MRD
      ANDP    M2435  ; 12#位置6
      DMOV    D2450 D1630
      MRD
      ANDP    M2436  ; 12#位置7
      DMOV    D2452 D1630
      MRD
      ANDP    M2437  ; 12#位置8
      DMOV    D2454 D1630
      MRD
      ANDP    M2438  ; 12#位置9
      DMOV    D2456 D1630
      MPP
      ANDP    M2439  ; 12#位置10
      DMOV    D2458 D1630
203   LD      SM400  ; 始终ON
      MPS
      AND     M20  ; 手动状态
      DMOV    D1224 D1632  ; 12#手动频率 / 12#速度
      MRD
      ANI     M20  ; 手动状态
      DMOV    D1226 D1632  ; 12#自动速度
      MPP
      DMOV    D1632 U6\G8004
      DMOV    D1222 U6\G8006  ; 12#原点位置
      DMOV    D1632 U6\G8014
      DMOV    D1238 U6\G8016
      DMOV    D1632 U6\G8024
      DMOV    D1630 U6\G8026
237   LD      M2234  ; 12#回原点定位
      OR      M2230  ; 12#折料
      OR<>    K0 K4M2430  ; 12#位置1
      MPS
      AND     M2234  ; 12#回原点定位
      MOVP    K1 D1628  ; 12#模式
      MRD
      AND     M2230  ; 12#折料
      MOVP    K2 D1628
      MRD
      AND<>   K0 K4M2430  ; 12#位置1
      MOVP    K3 D1628
      MRD
      MEP
      ZP.PSTRT1 U6 D1626 M2237  ; 12#轴定位 / 12#轴定位完成
      MPP
      AND     M2237  ; 12#轴定位完成
      BKRST   M2430 K20
      BKRST   M2230 K5
274   LDD=    D1220 D2440  ; 12#当前值 / 12#轴位置1
      OUT     M2920  ; 12#在原点位置
278   LDD=    D1220 D2440  ; 12#当前值 / 12#轴位置1
      OUT     M2921  ; 12#在位置1
282   LDD=    D1220 D2442  ; 12#当前值 / 12#轴位置2
      OUT     M2922  ; 12#在位置2
286   LDD=    D1220 D2444  ; 12#当前值 / 12#轴位置3
      OUT     M2923  ; 12#在位置3
290   LDD=    D1220 D2446  ; 12#当前值 / 12#轴位置4
      OUT     M2924  ; 12#在位置4
294   LDD=    D1220 D2448  ; 12#当前值 / 12#轴位置5
      OUT     M2925  ; 12#在位置5
298   LDD=    D1220 D2450  ; 12#当前值 / 12#轴位置6
      OUT     M2926  ; 12#在位置6
302   LDD=    D1220 D2452  ; 12#当前值 / 12#轴位置7
      OUT     M2927  ; 12#在位置7
306   LDD=    D1220 D2454  ; 12#当前值 / 12#轴位置8
      OUT     M2928  ; 12#在位置8
310   LDD=    D1220 D2456  ; 12#当前值 / 12#轴位置9
      OUT     M2929  ; 12#在位置9
314   LDD=    D1220 D2458  ; 12#当前值 / 12#轴位置10
      OUT     M2930  ; 12#在位置10
318   LD      M20  ; 手动状态
      MPS
      LD      M2225  ; 12#JOG+
      OR      M2226  ; 12#JOG-
      ANB
      ANI     X6D  ; 12#忙
      SET     M2227  ; 12#JOG
      MRD
      ANI     M2225  ; 12#JOG+
      ANI     M2226  ; 12#JOG-
      RST     M2227  ; 12#JOG
      MRD
      AND     M2225  ; 12#JOG+
      AND     M2227  ; 12#JOG
      ANI     Y6B  ; 12#反向JOG
      OUT     Y6A  ; 12#正向JOG
      MPP
      AND     M2226  ; 12#JOG-
      AND     M2227  ; 12#JOG
      ANI     Y6A  ; 12#正向JOG
      OUT     Y6B  ; 12#反向JOG
339   END
END_PROGRAM
